###############################################################
#  Generated by:      Cadence Innovus 20.13-s083_1
#  OS:                Linux x86_64(Host ID caddyxtra)
#  Generated on:      Fri Jun 18 21:39:54 2021
#  Design:            user_project_wrapper
#  Command:           write_lef_abstract -specifyTopLayer 6 -PGPinLayers {5 6} -noCutObs -stripePin results/user_project_wrapper.lef
###############################################################

VERSION 5.8 ;

BUSBITCHARS "[]" ;
DIVIDERCHAR "/" ;

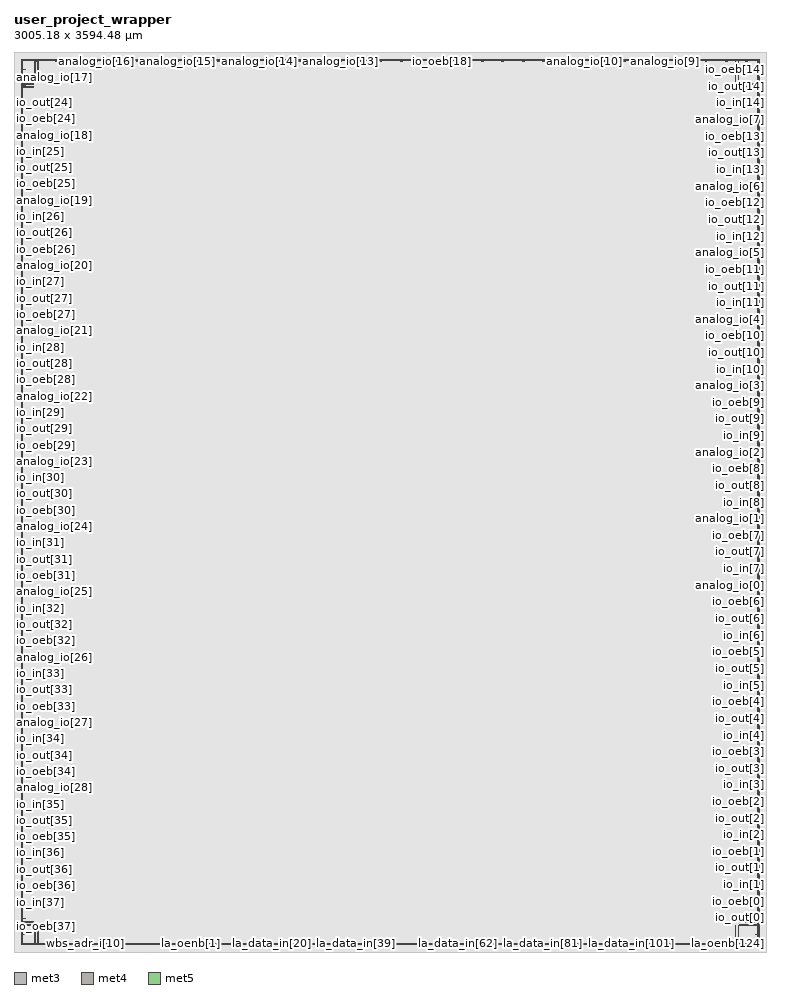
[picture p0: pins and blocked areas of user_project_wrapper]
MACRO user_project_wrapper
  CLASS BLOCK ;
  SIZE 3005.180000 BY 3594.480000 ;
  FOREIGN user_project_wrapper 0.000000 0.000000 ;
  ORIGIN 0 0 ;
  SYMMETRY X Y R90 ;
  PIN wb_clk_i
    DIRECTION INPUT ;
    USE SIGNAL ;
    ANTENNAPARTIALMETALAREA 0.2754 LAYER met3  ;
    ANTENNAPARTIALMETALSIDEAREA 1.464 LAYER met3  ;
    ANTENNAMODEL OXIDE1 ;
    ANTENNAGATEAREA 0.576 LAYER met3  ;
    ANTENNAMAXAREACAR 2.39566 LAYER met3  ;
    ANTENNAMAXSIDEAREACAR 9.93403 LAYER met3  ;
    ANTENNAMAXCUTCAR 0.158681 LAYER via3  ;
    PORT
      LAYER met3 ;
        RECT 45.490000 32.600000 52.690000 33.800000 ;
    END
  END wb_clk_i
  PIN wb_rst_i
    DIRECTION INPUT ;
    USE SIGNAL ;
    ANTENNAPARTIALMETALAREA 8.4594 LAYER met3  ;
    ANTENNAPARTIALMETALSIDEAREA 45.112 LAYER met3  ;
    ANTENNAMODEL OXIDE1 ;
    ANTENNAGATEAREA 1.33 LAYER met3  ;
    ANTENNAMAXAREACAR 19.705 LAYER met3  ;
    ANTENNAMAXSIDEAREACAR 99.8519 LAYER met3  ;
    ANTENNAMAXCUTCAR 0.0687218 LAYER via3  ;
    PORT
      LAYER met3 ;
        RECT 51.010000 32.600000 58.210000 33.800000 ;
    END
  END wb_rst_i
  PIN wbs_stb_i
    DIRECTION INPUT ;
    USE SIGNAL ;
    ANTENNAPARTIALMETALAREA 7.6608 LAYER met3  ;
    ANTENNAPARTIALMETALSIDEAREA 41.328 LAYER met3  ;
    PORT
      LAYER met3 ;
        RECT 68.950000 32.600000 76.150000 33.800000 ;
    END
  END wbs_stb_i
  PIN wbs_cyc_i
    DIRECTION INPUT ;
    USE SIGNAL ;
    ANTENNAPARTIALMETALAREA 8.2614 LAYER met3  ;
    ANTENNAPARTIALMETALSIDEAREA 44.056 LAYER met3  ;
    PORT
      LAYER met3 ;
        RECT 62.970000 32.600000 70.170000 33.800000 ;
    END
  END wbs_cyc_i
  PIN wbs_we_i
    DIRECTION INPUT ;
    USE SIGNAL ;
    ANTENNAPARTIALMETALAREA 7.4328 LAYER met3  ;
    ANTENNAPARTIALMETALSIDEAREA 40.112 LAYER met3  ;
    PORT
      LAYER met3 ;
        RECT 74.930000 32.600000 82.130000 33.800000 ;
    END
  END wbs_we_i
  PIN wbs_sel_i[3]
    DIRECTION INPUT ;
    USE SIGNAL ;
    ANTENNAPARTIALMETALAREA 7.4334 LAYER met3  ;
    ANTENNAPARTIALMETALSIDEAREA 39.64 LAYER met3  ;
    PORT
      LAYER met3 ;
        RECT 169.230000 32.600000 176.430000 33.800000 ;
    END
  END wbs_sel_i[3]
  PIN wbs_sel_i[2]
    DIRECTION INPUT ;
    USE SIGNAL ;
    ANTENNAPARTIALMETALAREA 7.2054 LAYER met3  ;
    ANTENNAPARTIALMETALSIDEAREA 38.424 LAYER met3  ;
    PORT
      LAYER met3 ;
        RECT 145.770000 32.600000 152.970000 33.800000 ;
    END
  END wbs_sel_i[2]
  PIN wbs_sel_i[1]
    DIRECTION INPUT ;
    USE SIGNAL ;
    ANTENNAPARTIALMETALAREA 7.9074 LAYER met3  ;
    ANTENNAPARTIALMETALSIDEAREA 42.168 LAYER met3  ;
    PORT
      LAYER met3 ;
        RECT 122.310000 32.600000 129.510000 33.800000 ;
    END
  END wbs_sel_i[1]
  PIN wbs_sel_i[0]
    DIRECTION INPUT ;
    USE SIGNAL ;
    PORT
      LAYER met3 ;
        RECT 98.390000 32.600000 105.590000 33.800000 ;
    END
  END wbs_sel_i[0]
  PIN wbs_dat_i[31]
    DIRECTION INPUT ;
    USE SIGNAL ;
    ANTENNAPARTIALMETALAREA 2.8494 LAYER met3  ;
    ANTENNAPARTIALMETALSIDEAREA 15.192 LAYER met3  ;
    PORT
      LAYER met3 ;
        RECT 660.050000 32.600000 667.250000 33.800000 ;
    END
  END wbs_dat_i[31]
  PIN wbs_dat_i[30]
    DIRECTION INPUT ;
    USE SIGNAL ;
    ANTENNAPARTIALMETALAREA 3.0654 LAYER met3  ;
    ANTENNAPARTIALMETALSIDEAREA 16.344 LAYER met3  ;
    PORT
      LAYER met3 ;
        RECT 642.110000 32.600000 649.310000 33.800000 ;
    END
  END wbs_dat_i[30]
  PIN wbs_dat_i[29]
    DIRECTION INPUT ;
    USE SIGNAL ;
    ANTENNAPARTIALMETALAREA 3.5694 LAYER met3  ;
    ANTENNAPARTIALMETALSIDEAREA 19.032 LAYER met3  ;
    PORT
      LAYER met3 ;
        RECT 624.630000 32.600000 631.830000 33.800000 ;
    END
  END wbs_dat_i[29]
  PIN wbs_dat_i[28]
    DIRECTION INPUT ;
    USE SIGNAL ;
    ANTENNAPARTIALMETALAREA 3.7674 LAYER met3  ;
    ANTENNAPARTIALMETALSIDEAREA 20.088 LAYER met3  ;
    PORT
      LAYER met3 ;
        RECT 606.690000 32.600000 613.890000 33.800000 ;
    END
  END wbs_dat_i[28]
  PIN wbs_dat_i[27]
    DIRECTION INPUT ;
    USE SIGNAL ;
    ANTENNAPARTIALMETALAREA 3.9054 LAYER met3  ;
    ANTENNAPARTIALMETALSIDEAREA 20.824 LAYER met3  ;
    PORT
      LAYER met3 ;
        RECT 589.210000 32.600000 596.410000 33.800000 ;
    END
  END wbs_dat_i[27]
  PIN wbs_dat_i[26]
    DIRECTION INPUT ;
    USE SIGNAL ;
    ANTENNAPARTIALMETALAREA 3.9834 LAYER met3  ;
    ANTENNAPARTIALMETALSIDEAREA 21.24 LAYER met3  ;
    PORT
      LAYER met3 ;
        RECT 571.270000 32.600000 578.470000 33.800000 ;
    END
  END wbs_dat_i[26]
  PIN wbs_dat_i[25]
    DIRECTION INPUT ;
    USE SIGNAL ;
    ANTENNAPARTIALMETALAREA 3.5874 LAYER met3  ;
    ANTENNAPARTIALMETALSIDEAREA 19.128 LAYER met3  ;
    PORT
      LAYER met3 ;
        RECT 553.790000 32.600000 560.990000 33.800000 ;
    END
  END wbs_dat_i[25]
  PIN wbs_dat_i[24]
    DIRECTION INPUT ;
    USE SIGNAL ;
    ANTENNAPARTIALMETALAREA 4.3194 LAYER met3  ;
    ANTENNAPARTIALMETALSIDEAREA 23.032 LAYER met3  ;
    PORT
      LAYER met3 ;
        RECT 535.850000 32.600000 543.050000 33.800000 ;
    END
  END wbs_dat_i[24]
  PIN wbs_dat_i[23]
    DIRECTION INPUT ;
    USE SIGNAL ;
    ANTENNAPARTIALMETALAREA 4.1364 LAYER met3  ;
    ANTENNAPARTIALMETALSIDEAREA 22.056 LAYER met3  ;
    PORT
      LAYER met3 ;
        RECT 518.370000 32.600000 525.570000 33.800000 ;
    END
  END wbs_dat_i[23]
  PIN wbs_dat_i[22]
    DIRECTION INPUT ;
    USE SIGNAL ;
    PORT
      LAYER met3 ;
        RECT 500.430000 32.600000 507.630000 33.800000 ;
    END
  END wbs_dat_i[22]
  PIN wbs_dat_i[21]
    DIRECTION INPUT ;
    USE SIGNAL ;
    ANTENNAPARTIALMETALAREA 4.8114 LAYER met3  ;
    ANTENNAPARTIALMETALSIDEAREA 25.656 LAYER met3  ;
    PORT
      LAYER met3 ;
        RECT 482.490000 32.600000 489.690000 33.800000 ;
    END
  END wbs_dat_i[21]
  PIN wbs_dat_i[20]
    DIRECTION INPUT ;
    USE SIGNAL ;
    ANTENNAPARTIALMETALAREA 4.6884 LAYER met3  ;
    ANTENNAPARTIALMETALSIDEAREA 25 LAYER met3  ;
    PORT
      LAYER met3 ;
        RECT 465.010000 32.600000 472.210000 33.800000 ;
    END
  END wbs_dat_i[20]
  PIN wbs_dat_i[19]
    DIRECTION INPUT ;
    USE SIGNAL ;
    ANTENNAPARTIALMETALAREA 4.7214 LAYER met3  ;
    ANTENNAPARTIALMETALSIDEAREA 25.176 LAYER met3  ;
    PORT
      LAYER met3 ;
        RECT 447.070000 32.600000 454.270000 33.800000 ;
    END
  END wbs_dat_i[19]
  PIN wbs_dat_i[18]
    DIRECTION INPUT ;
    USE SIGNAL ;
    ANTENNAPARTIALMETALAREA 4.6884 LAYER met3  ;
    ANTENNAPARTIALMETALSIDEAREA 25 LAYER met3  ;
    PORT
      LAYER met3 ;
        RECT 429.590000 32.600000 436.790000 33.800000 ;
    END
  END wbs_dat_i[18]
  PIN wbs_dat_i[17]
    DIRECTION INPUT ;
    USE SIGNAL ;
    ANTENNAPARTIALMETALAREA 5.4234 LAYER met3  ;
    ANTENNAPARTIALMETALSIDEAREA 28.92 LAYER met3  ;
    PORT
      LAYER met3 ;
        RECT 411.650000 32.600000 418.850000 33.800000 ;
    END
  END wbs_dat_i[17]
  PIN wbs_dat_i[16]
    DIRECTION INPUT ;
    USE SIGNAL ;
    ANTENNAPARTIALMETALAREA 5.4234 LAYER met3  ;
    ANTENNAPARTIALMETALSIDEAREA 28.92 LAYER met3  ;
    PORT
      LAYER met3 ;
        RECT 394.170000 32.600000 401.370000 33.800000 ;
    END
  END wbs_dat_i[16]
  PIN wbs_dat_i[15]
    DIRECTION INPUT ;
    USE SIGNAL ;
    PORT
      LAYER met3 ;
        RECT 376.230000 32.600000 383.430000 33.800000 ;
    END
  END wbs_dat_i[15]
  PIN wbs_dat_i[14]
    DIRECTION INPUT ;
    USE SIGNAL ;
    ANTENNAPARTIALMETALAREA 5.4114 LAYER met3  ;
    ANTENNAPARTIALMETALSIDEAREA 28.856 LAYER met3  ;
    PORT
      LAYER met3 ;
        RECT 358.750000 32.600000 365.950000 33.800000 ;
    END
  END wbs_dat_i[14]
  PIN wbs_dat_i[13]
    DIRECTION INPUT ;
    USE SIGNAL ;
    ANTENNAPARTIALMETALAREA 5.9154 LAYER met3  ;
    ANTENNAPARTIALMETALSIDEAREA 31.544 LAYER met3  ;
    PORT
      LAYER met3 ;
        RECT 340.810000 32.600000 348.010000 33.800000 ;
    END
  END wbs_dat_i[13]
  PIN wbs_dat_i[12]
    DIRECTION INPUT ;
    USE SIGNAL ;
    ANTENNAPARTIALMETALAREA 5.9118 LAYER met3  ;
    ANTENNAPARTIALMETALSIDEAREA 32 LAYER met3  ;
    PORT
      LAYER met3 ;
        RECT 322.870000 32.600000 330.070000 33.800000 ;
    END
  END wbs_dat_i[12]
  PIN wbs_dat_i[11]
    DIRECTION INPUT ;
    USE SIGNAL ;
    PORT
      LAYER met3 ;
        RECT 305.390000 32.600000 312.590000 33.800000 ;
    END
  END wbs_dat_i[11]
  PIN wbs_dat_i[10]
    DIRECTION INPUT ;
    USE SIGNAL ;
    ANTENNAPARTIALMETALAREA 6.1014 LAYER met3  ;
    ANTENNAPARTIALMETALSIDEAREA 32.536 LAYER met3  ;
    PORT
      LAYER met3 ;
        RECT 287.450000 32.600000 294.650000 33.800000 ;
    END
  END wbs_dat_i[10]
  PIN wbs_dat_i[9]
    DIRECTION INPUT ;
    USE SIGNAL ;
    ANTENNAPARTIALMETALAREA 6.5274 LAYER met3  ;
    ANTENNAPARTIALMETALSIDEAREA 34.808 LAYER met3  ;
    PORT
      LAYER met3 ;
        RECT 269.970000 32.600000 277.170000 33.800000 ;
    END
  END wbs_dat_i[9]
  PIN wbs_dat_i[8]
    DIRECTION INPUT ;
    USE SIGNAL ;
    PORT
      LAYER met3 ;
        RECT 252.030000 32.600000 259.230000 33.800000 ;
    END
  END wbs_dat_i[8]
  PIN wbs_dat_i[7]
    DIRECTION INPUT ;
    USE SIGNAL ;
    ANTENNAPARTIALMETALAREA 6.6462 LAYER met3  ;
    ANTENNAPARTIALMETALSIDEAREA 35.912 LAYER met3  ;
    PORT
      LAYER met3 ;
        RECT 234.550000 32.600000 241.750000 33.800000 ;
    END
  END wbs_dat_i[7]
  PIN wbs_dat_i[6]
    DIRECTION INPUT ;
    USE SIGNAL ;
    PORT
      LAYER met3 ;
        RECT 216.610000 32.600000 223.810000 33.800000 ;
    END
  END wbs_dat_i[6]
  PIN wbs_dat_i[5]
    DIRECTION INPUT ;
    USE SIGNAL ;
    ANTENNAPARTIALMETALAREA 6.6498 LAYER met3  ;
    ANTENNAPARTIALMETALSIDEAREA 35.936 LAYER met3  ;
    PORT
      LAYER met3 ;
        RECT 199.130000 32.600000 206.330000 33.800000 ;
    END
  END wbs_dat_i[5]
  PIN wbs_dat_i[4]
    DIRECTION INPUT ;
    USE SIGNAL ;
    ANTENNAPARTIALMETALAREA 6.5304 LAYER met3  ;
    ANTENNAPARTIALMETALSIDEAREA 34.824 LAYER met3  ;
    PORT
      LAYER met3 ;
        RECT 181.190000 32.600000 188.390000 33.800000 ;
    END
  END wbs_dat_i[4]
  PIN wbs_dat_i[3]
    DIRECTION INPUT ;
    USE SIGNAL ;
    ANTENNAPARTIALMETALAREA 6.6498 LAYER met3  ;
    ANTENNAPARTIALMETALSIDEAREA 35.936 LAYER met3  ;
    PORT
      LAYER met3 ;
        RECT 157.730000 32.600000 164.930000 33.800000 ;
    END
  END wbs_dat_i[3]
  PIN wbs_dat_i[2]
    DIRECTION INPUT ;
    USE SIGNAL ;
    PORT
      LAYER met3 ;
        RECT 133.810000 32.600000 141.010000 33.800000 ;
    END
  END wbs_dat_i[2]
  PIN wbs_dat_i[1]
    DIRECTION INPUT ;
    USE SIGNAL ;
    ANTENNAPARTIALMETALAREA 7.2948 LAYER met3  ;
    ANTENNAPARTIALMETALSIDEAREA 39.376 LAYER met3  ;
    PORT
      LAYER met3 ;
        RECT 110.350000 32.600000 117.550000 33.800000 ;
    END
  END wbs_dat_i[1]
  PIN wbs_dat_i[0]
    DIRECTION INPUT ;
    USE SIGNAL ;
    ANTENNAPARTIALMETALAREA 7.3584 LAYER met3  ;
    ANTENNAPARTIALMETALSIDEAREA 39.24 LAYER met3  ;
    PORT
      LAYER met3 ;
        RECT 86.430000 32.600000 93.630000 33.800000 ;
    END
  END wbs_dat_i[0]
  PIN wbs_adr_i[31]
    DIRECTION INPUT ;
    USE SIGNAL ;
    ANTENNAPARTIALMETALAREA 2.9274 LAYER met3  ;
    ANTENNAPARTIALMETALSIDEAREA 15.608 LAYER met3  ;
    PORT
      LAYER met3 ;
        RECT 654.070000 32.600000 661.270000 33.800000 ;
    END
  END wbs_adr_i[31]
  PIN wbs_adr_i[30]
    DIRECTION INPUT ;
    USE SIGNAL ;
    ANTENNAPARTIALMETALAREA 3.1254 LAYER met3  ;
    ANTENNAPARTIALMETALSIDEAREA 16.664 LAYER met3  ;
    PORT
      LAYER met3 ;
        RECT 636.590000 32.600000 643.790000 33.800000 ;
    END
  END wbs_adr_i[30]
  PIN wbs_adr_i[29]
    DIRECTION INPUT ;
    USE SIGNAL ;
    ANTENNAPARTIALMETALAREA 3.6294 LAYER met3  ;
    ANTENNAPARTIALMETALSIDEAREA 19.352 LAYER met3  ;
    PORT
      LAYER met3 ;
        RECT 618.650000 32.600000 625.850000 33.800000 ;
    END
  END wbs_adr_i[29]
  PIN wbs_adr_i[28]
    DIRECTION INPUT ;
    USE SIGNAL ;
    ANTENNAPARTIALMETALAREA 3.8454 LAYER met3  ;
    ANTENNAPARTIALMETALSIDEAREA 20.504 LAYER met3  ;
    PORT
      LAYER met3 ;
        RECT 600.710000 32.600000 607.910000 33.800000 ;
    END
  END wbs_adr_i[28]
  PIN wbs_adr_i[27]
    DIRECTION INPUT ;
    USE SIGNAL ;
    ANTENNAPARTIALMETALAREA 3.8454 LAYER met3  ;
    ANTENNAPARTIALMETALSIDEAREA 20.504 LAYER met3  ;
    PORT
      LAYER met3 ;
        RECT 583.230000 32.600000 590.430000 33.800000 ;
    END
  END wbs_adr_i[27]
  PIN wbs_adr_i[26]
    DIRECTION INPUT ;
    USE SIGNAL ;
    ANTENNAPARTIALMETALAREA 4.1814 LAYER met3  ;
    ANTENNAPARTIALMETALSIDEAREA 22.296 LAYER met3  ;
    PORT
      LAYER met3 ;
        RECT 565.290000 32.600000 572.490000 33.800000 ;
    END
  END wbs_adr_i[26]
  PIN wbs_adr_i[25]
    DIRECTION INPUT ;
    USE SIGNAL ;
    ANTENNAPARTIALMETALAREA 3.6774 LAYER met3  ;
    ANTENNAPARTIALMETALSIDEAREA 19.608 LAYER met3  ;
    PORT
      LAYER met3 ;
        RECT 547.810000 32.600000 555.010000 33.800000 ;
    END
  END wbs_adr_i[25]
  PIN wbs_adr_i[24]
    DIRECTION INPUT ;
    USE SIGNAL ;
    ANTENNAPARTIALMETALAREA 3.7068 LAYER met3  ;
    ANTENNAPARTIALMETALSIDEAREA 20.24 LAYER met3  ;
    PORT
      LAYER met3 ;
        RECT 529.870000 32.600000 537.070000 33.800000 ;
    END
  END wbs_adr_i[24]
  PIN wbs_adr_i[23]
    DIRECTION INPUT ;
    USE SIGNAL ;
    ANTENNAPARTIALMETALAREA 4.3974 LAYER met3  ;
    ANTENNAPARTIALMETALSIDEAREA 23.448 LAYER met3  ;
    PORT
      LAYER met3 ;
        RECT 512.390000 32.600000 519.590000 33.800000 ;
    END
  END wbs_adr_i[23]
  PIN wbs_adr_i[22]
    DIRECTION INPUT ;
    USE SIGNAL ;
    ANTENNAPARTIALMETALAREA 4.7334 LAYER met3  ;
    ANTENNAPARTIALMETALSIDEAREA 25.24 LAYER met3  ;
    PORT
      LAYER met3 ;
        RECT 494.450000 32.600000 501.650000 33.800000 ;
    END
  END wbs_adr_i[22]
  PIN wbs_adr_i[21]
    DIRECTION INPUT ;
    USE SIGNAL ;
    ANTENNAPARTIALMETALAREA 4.4124 LAYER met3  ;
    ANTENNAPARTIALMETALSIDEAREA 23.528 LAYER met3  ;
    PORT
      LAYER met3 ;
        RECT 476.970000 32.600000 484.170000 33.800000 ;
    END
  END wbs_adr_i[21]
  PIN wbs_adr_i[20]
    DIRECTION INPUT ;
    USE SIGNAL ;
    ANTENNAPARTIALMETALAREA 4.9494 LAYER met3  ;
    ANTENNAPARTIALMETALSIDEAREA 26.392 LAYER met3  ;
    PORT
      LAYER met3 ;
        RECT 459.030000 32.600000 466.230000 33.800000 ;
    END
  END wbs_adr_i[20]
  PIN wbs_adr_i[19]
    DIRECTION INPUT ;
    USE SIGNAL ;
    PORT
      LAYER met3 ;
        RECT 441.090000 32.600000 448.290000 33.800000 ;
    END
  END wbs_adr_i[19]
  PIN wbs_adr_i[18]
    DIRECTION INPUT ;
    USE SIGNAL ;
    ANTENNAPARTIALMETALAREA 5.2254 LAYER met3  ;
    ANTENNAPARTIALMETALSIDEAREA 27.864 LAYER met3  ;
    PORT
      LAYER met3 ;
        RECT 423.610000 32.600000 430.810000 33.800000 ;
    END
  END wbs_adr_i[18]
  PIN wbs_adr_i[17]
    DIRECTION INPUT ;
    USE SIGNAL ;
    ANTENNAPARTIALMETALAREA 4.9008 LAYER met3  ;
    ANTENNAPARTIALMETALSIDEAREA 26.608 LAYER met3  ;
    PORT
      LAYER met3 ;
        RECT 405.670000 32.600000 412.870000 33.800000 ;
    END
  END wbs_adr_i[17]
  PIN wbs_adr_i[16]
    DIRECTION INPUT ;
    USE SIGNAL ;
    ANTENNAPARTIALMETALAREA 5.5014 LAYER met3  ;
    ANTENNAPARTIALMETALSIDEAREA 29.336 LAYER met3  ;
    PORT
      LAYER met3 ;
        RECT 388.190000 32.600000 395.390000 33.800000 ;
    END
  END wbs_adr_i[16]
  PIN wbs_adr_i[15]
    DIRECTION INPUT ;
    USE SIGNAL ;
    ANTENNAPARTIALMETALAREA 5.6994 LAYER met3  ;
    ANTENNAPARTIALMETALSIDEAREA 30.392 LAYER met3  ;
    PORT
      LAYER met3 ;
        RECT 370.250000 32.600000 377.450000 33.800000 ;
    END
  END wbs_adr_i[15]
  PIN wbs_adr_i[14]
    DIRECTION INPUT ;
    USE SIGNAL ;
    ANTENNAPARTIALMETALAREA 5.8374 LAYER met3  ;
    ANTENNAPARTIALMETALSIDEAREA 31.128 LAYER met3  ;
    PORT
      LAYER met3 ;
        RECT 352.770000 32.600000 359.970000 33.800000 ;
    END
  END wbs_adr_i[14]
  PIN wbs_adr_i[13]
    DIRECTION INPUT ;
    USE SIGNAL ;
    ANTENNAPARTIALMETALAREA 5.7924 LAYER met3  ;
    ANTENNAPARTIALMETALSIDEAREA 30.888 LAYER met3  ;
    PORT
      LAYER met3 ;
        RECT 334.830000 32.600000 342.030000 33.800000 ;
    END
  END wbs_adr_i[13]
  PIN wbs_adr_i[12]
    DIRECTION INPUT ;
    USE SIGNAL ;
    ANTENNAPARTIALMETALAREA 5.65343 LAYER met3  ;
    ANTENNAPARTIALMETALSIDEAREA 30.144 LAYER met3  ;
    PORT
      LAYER met3 ;
        RECT 317.350000 32.600000 324.550000 33.800000 ;
    END
  END wbs_adr_i[12]
  PIN wbs_adr_i[11]
    DIRECTION INPUT ;
    USE SIGNAL ;
    ANTENNAPARTIALMETALAREA 6.3894 LAYER met3  ;
    ANTENNAPARTIALMETALSIDEAREA 34.072 LAYER met3  ;
    PORT
      LAYER met3 ;
        RECT 299.410000 32.600000 306.610000 33.800000 ;
    END
  END wbs_adr_i[11]
  PIN wbs_adr_i[10]
    DIRECTION INPUT ;
    USE SIGNAL ;
    ANTENNAPARTIALMETALAREA 6.4638 LAYER met3  ;
    ANTENNAPARTIALMETALSIDEAREA 34.944 LAYER met3  ;
    PORT
      LAYER met3 ;
        RECT 281.930000 32.600000 289.130000 33.800000 ;
    END
  END wbs_adr_i[10]
  PIN wbs_adr_i[9]
    DIRECTION INPUT ;
    USE SIGNAL ;
    ANTENNAPARTIALMETALAREA 6.6054 LAYER met3  ;
    ANTENNAPARTIALMETALSIDEAREA 35.224 LAYER met3  ;
    PORT
      LAYER met3 ;
        RECT 263.990000 32.600000 271.190000 33.800000 ;
    END
  END wbs_adr_i[9]
  PIN wbs_adr_i[8]
    DIRECTION INPUT ;
    USE SIGNAL ;
    ANTENNAPARTIALMETALAREA 6.8034 LAYER met3  ;
    ANTENNAPARTIALMETALSIDEAREA 36.28 LAYER met3  ;
    PORT
      LAYER met3 ;
        RECT 246.050000 32.600000 253.250000 33.800000 ;
    END
  END wbs_adr_i[8]
  PIN wbs_adr_i[7]
    DIRECTION INPUT ;
    USE SIGNAL ;
    PORT
      LAYER met3 ;
        RECT 228.570000 32.600000 235.770000 33.800000 ;
    END
  END wbs_adr_i[7]
  PIN wbs_adr_i[6]
    DIRECTION INPUT ;
    USE SIGNAL ;
    ANTENNAPARTIALMETALAREA 7.0794 LAYER met3  ;
    ANTENNAPARTIALMETALSIDEAREA 37.752 LAYER met3  ;
    PORT
      LAYER met3 ;
        RECT 210.630000 32.600000 217.830000 33.800000 ;
    END
  END wbs_adr_i[6]
  PIN wbs_adr_i[5]
    DIRECTION INPUT ;
    USE SIGNAL ;
    ANTENNAPARTIALMETALAREA 6.3708 LAYER met3  ;
    ANTENNAPARTIALMETALSIDEAREA 34.448 LAYER met3  ;
    PORT
      LAYER met3 ;
        RECT 193.150000 32.600000 200.350000 33.800000 ;
    END
  END wbs_adr_i[5]
  PIN wbs_adr_i[4]
    DIRECTION INPUT ;
    USE SIGNAL ;
    ANTENNAPARTIALMETALAREA 7.1244 LAYER met3  ;
    ANTENNAPARTIALMETALSIDEAREA 37.992 LAYER met3  ;
    PORT
      LAYER met3 ;
        RECT 175.210000 32.600000 182.410000 33.800000 ;
    END
  END wbs_adr_i[4]
  PIN wbs_adr_i[3]
    DIRECTION INPUT ;
    USE SIGNAL ;
    ANTENNAPARTIALMETALAREA 6.8328 LAYER met3  ;
    ANTENNAPARTIALMETALSIDEAREA 36.912 LAYER met3  ;
    PORT
      LAYER met3 ;
        RECT 151.750000 32.600000 158.950000 33.800000 ;
    END
  END wbs_adr_i[3]
  PIN wbs_adr_i[2]
    DIRECTION INPUT ;
    USE SIGNAL ;
    PORT
      LAYER met3 ;
        RECT 127.830000 32.600000 135.030000 33.800000 ;
    END
  END wbs_adr_i[2]
  PIN wbs_adr_i[1]
    DIRECTION INPUT ;
    USE SIGNAL ;
    ANTENNAPARTIALMETALAREA 7.4814 LAYER met3  ;
    ANTENNAPARTIALMETALSIDEAREA 39.896 LAYER met3  ;
    PORT
      LAYER met3 ;
        RECT 104.370000 32.600000 111.570000 33.800000 ;
    END
  END wbs_adr_i[1]
  PIN wbs_adr_i[0]
    DIRECTION INPUT ;
    USE SIGNAL ;
    ANTENNAPARTIALMETALAREA 8.0904 LAYER met3  ;
    ANTENNAPARTIALMETALSIDEAREA 43.144 LAYER met3  ;
    PORT
      LAYER met3 ;
        RECT 80.910000 32.600000 88.110000 33.800000 ;
    END
  END wbs_adr_i[0]
  PIN wbs_ack_o
    DIRECTION OUTPUT ;
    USE SIGNAL ;
    PORT
      LAYER met3 ;
        RECT 56.990000 32.600000 64.190000 33.800000 ;
    END
  END wbs_ack_o
  PIN wbs_dat_o[31]
    DIRECTION OUTPUT ;
    USE SIGNAL ;
    PORT
      LAYER met3 ;
        RECT 666.030000 32.600000 673.230000 33.800000 ;
    END
  END wbs_dat_o[31]
  PIN wbs_dat_o[30]
    DIRECTION OUTPUT ;
    USE SIGNAL ;
    PORT
      LAYER met3 ;
        RECT 648.090000 32.600000 655.290000 33.800000 ;
    END
  END wbs_dat_o[30]
  PIN wbs_dat_o[29]
    DIRECTION OUTPUT ;
    USE SIGNAL ;
    PORT
      LAYER met3 ;
        RECT 630.610000 32.600000 637.810000 33.800000 ;
    END
  END wbs_dat_o[29]
  PIN wbs_dat_o[28]
    DIRECTION OUTPUT ;
    USE SIGNAL ;
    PORT
      LAYER met3 ;
        RECT 612.670000 32.600000 619.870000 33.800000 ;
    END
  END wbs_dat_o[28]
  PIN wbs_dat_o[27]
    DIRECTION OUTPUT ;
    USE SIGNAL ;
    PORT
      LAYER met3 ;
        RECT 595.190000 32.600000 602.390000 33.800000 ;
    END
  END wbs_dat_o[27]
  PIN wbs_dat_o[26]
    DIRECTION OUTPUT ;
    USE SIGNAL ;
    PORT
      LAYER met3 ;
        RECT 577.250000 32.600000 584.450000 33.800000 ;
    END
  END wbs_dat_o[26]
  PIN wbs_dat_o[25]
    DIRECTION OUTPUT ;
    USE SIGNAL ;
    PORT
      LAYER met3 ;
        RECT 559.310000 32.600000 566.510000 33.800000 ;
    END
  END wbs_dat_o[25]
  PIN wbs_dat_o[24]
    DIRECTION OUTPUT ;
    USE SIGNAL ;
    PORT
      LAYER met3 ;
        RECT 541.830000 32.600000 549.030000 33.800000 ;
    END
  END wbs_dat_o[24]
  PIN wbs_dat_o[23]
    DIRECTION OUTPUT ;
    USE SIGNAL ;
    PORT
      LAYER met3 ;
        RECT 523.890000 32.600000 531.090000 33.800000 ;
    END
  END wbs_dat_o[23]
  PIN wbs_dat_o[22]
    DIRECTION OUTPUT ;
    USE SIGNAL ;
    PORT
      LAYER met3 ;
        RECT 506.410000 32.600000 513.610000 33.800000 ;
    END
  END wbs_dat_o[22]
  PIN wbs_dat_o[21]
    DIRECTION OUTPUT ;
    USE SIGNAL ;
    PORT
      LAYER met3 ;
        RECT 488.470000 32.600000 495.670000 33.800000 ;
    END
  END wbs_dat_o[21]
  PIN wbs_dat_o[20]
    DIRECTION OUTPUT ;
    USE SIGNAL ;
    PORT
      LAYER met3 ;
        RECT 470.990000 32.600000 478.190000 33.800000 ;
    END
  END wbs_dat_o[20]
  PIN wbs_dat_o[19]
    DIRECTION OUTPUT ;
    USE SIGNAL ;
    PORT
      LAYER met3 ;
        RECT 453.050000 32.600000 460.250000 33.800000 ;
    END
  END wbs_dat_o[19]
  PIN wbs_dat_o[18]
    DIRECTION OUTPUT ;
    USE SIGNAL ;
    PORT
      LAYER met3 ;
        RECT 435.570000 32.600000 442.770000 33.800000 ;
    END
  END wbs_dat_o[18]
  PIN wbs_dat_o[17]
    DIRECTION OUTPUT ;
    USE SIGNAL ;
    PORT
      LAYER met3 ;
        RECT 417.630000 32.600000 424.830000 33.800000 ;
    END
  END wbs_dat_o[17]
  PIN wbs_dat_o[16]
    DIRECTION OUTPUT ;
    USE SIGNAL ;
    PORT
      LAYER met3 ;
        RECT 400.150000 32.600000 407.350000 33.800000 ;
    END
  END wbs_dat_o[16]
  PIN wbs_dat_o[15]
    DIRECTION OUTPUT ;
    USE SIGNAL ;
    PORT
      LAYER met3 ;
        RECT 382.210000 32.600000 389.410000 33.800000 ;
    END
  END wbs_dat_o[15]
  PIN wbs_dat_o[14]
    DIRECTION OUTPUT ;
    USE SIGNAL ;
    PORT
      LAYER met3 ;
        RECT 364.270000 32.600000 371.470000 33.800000 ;
    END
  END wbs_dat_o[14]
  PIN wbs_dat_o[13]
    DIRECTION OUTPUT ;
    USE SIGNAL ;
    PORT
      LAYER met3 ;
        RECT 346.790000 32.600000 353.990000 33.800000 ;
    END
  END wbs_dat_o[13]
  PIN wbs_dat_o[12]
    DIRECTION OUTPUT ;
    USE SIGNAL ;
    PORT
      LAYER met3 ;
        RECT 328.850000 32.600000 336.050000 33.800000 ;
    END
  END wbs_dat_o[12]
  PIN wbs_dat_o[11]
    DIRECTION OUTPUT ;
    USE SIGNAL ;
    PORT
      LAYER met3 ;
        RECT 311.370000 32.600000 318.570000 33.800000 ;
    END
  END wbs_dat_o[11]
  PIN wbs_dat_o[10]
    DIRECTION OUTPUT ;
    USE SIGNAL ;
    PORT
      LAYER met3 ;
        RECT 293.430000 32.600000 300.630000 33.800000 ;
    END
  END wbs_dat_o[10]
  PIN wbs_dat_o[9]
    DIRECTION OUTPUT ;
    USE SIGNAL ;
    PORT
      LAYER met3 ;
        RECT 275.950000 32.600000 283.150000 33.800000 ;
    END
  END wbs_dat_o[9]
  PIN wbs_dat_o[8]
    DIRECTION OUTPUT ;
    USE SIGNAL ;
    PORT
      LAYER met3 ;
        RECT 258.010000 32.600000 265.210000 33.800000 ;
    END
  END wbs_dat_o[8]
  PIN wbs_dat_o[7]
    DIRECTION OUTPUT ;
    USE SIGNAL ;
    PORT
      LAYER met3 ;
        RECT 240.530000 32.600000 247.730000 33.800000 ;
    END
  END wbs_dat_o[7]
  PIN wbs_dat_o[6]
    DIRECTION OUTPUT ;
    USE SIGNAL ;
    PORT
      LAYER met3 ;
        RECT 222.590000 32.600000 229.790000 33.800000 ;
    END
  END wbs_dat_o[6]
  PIN wbs_dat_o[5]
    DIRECTION OUTPUT ;
    USE SIGNAL ;
    PORT
      LAYER met3 ;
        RECT 204.650000 32.600000 211.850000 33.800000 ;
    END
  END wbs_dat_o[5]
  PIN wbs_dat_o[4]
    DIRECTION OUTPUT ;
    USE SIGNAL ;
    PORT
      LAYER met3 ;
        RECT 187.170000 32.600000 194.370000 33.800000 ;
    END
  END wbs_dat_o[4]
  PIN wbs_dat_o[3]
    DIRECTION OUTPUT ;
    USE SIGNAL ;
    PORT
      LAYER met3 ;
        RECT 163.710000 32.600000 170.910000 33.800000 ;
    END
  END wbs_dat_o[3]
  PIN wbs_dat_o[2]
    DIRECTION OUTPUT ;
    USE SIGNAL ;
    PORT
      LAYER met3 ;
        RECT 139.790000 32.600000 146.990000 33.800000 ;
    END
  END wbs_dat_o[2]
  PIN wbs_dat_o[1]
    DIRECTION OUTPUT ;
    USE SIGNAL ;
    PORT
      LAYER met3 ;
        RECT 116.330000 32.600000 123.530000 33.800000 ;
    END
  END wbs_dat_o[1]
  PIN wbs_dat_o[0]
    DIRECTION OUTPUT ;
    USE SIGNAL ;
    PORT
      LAYER met3 ;
        RECT 92.410000 32.600000 99.610000 33.800000 ;
    END
  END wbs_dat_o[0]
  PIN la_data_in[127]
    DIRECTION INPUT ;
    USE SIGNAL ;
    ANTENNAPARTIALMETALAREA 16.6794 LAYER met3  ;
    ANTENNAPARTIALMETALSIDEAREA 88.952 LAYER met3  ;
    PORT
      LAYER met3 ;
        RECT 2924.170000 32.600000 2931.370000 33.800000 ;
    END
  END la_data_in[127]
  PIN la_data_in[126]
    DIRECTION INPUT ;
    USE SIGNAL ;
    ANTENNAPARTIALMETALAREA 0.2754 LAYER met3  ;
    ANTENNAPARTIALMETALSIDEAREA 1.464 LAYER met3  ;
    PORT
      LAYER met3 ;
        RECT 2906.230000 32.600000 2913.430000 33.800000 ;
    END
  END la_data_in[126]
  PIN la_data_in[125]
    DIRECTION INPUT ;
    USE SIGNAL ;
    ANTENNAPARTIALMETALAREA 0.4584 LAYER met3  ;
    ANTENNAPARTIALMETALSIDEAREA 2.44 LAYER met3  ;
    PORT
      LAYER met3 ;
        RECT 2888.290000 32.600000 2895.490000 33.800000 ;
    END
  END la_data_in[125]
  PIN la_data_in[124]
    DIRECTION INPUT ;
    USE SIGNAL ;
    ANTENNAPARTIALMETALAREA 0.2754 LAYER met3  ;
    ANTENNAPARTIALMETALSIDEAREA 1.464 LAYER met3  ;
    PORT
      LAYER met3 ;
        RECT 2870.810000 32.600000 2878.010000 33.800000 ;
    END
  END la_data_in[124]
  PIN la_data_in[123]
    DIRECTION INPUT ;
    USE SIGNAL ;
    ANTENNAPARTIALMETALAREA 15.8064 LAYER met3  ;
    ANTENNAPARTIALMETALSIDEAREA 84.296 LAYER met3  ;
    PORT
      LAYER met3 ;
        RECT 2852.870000 32.600000 2860.070000 33.800000 ;
    END
  END la_data_in[123]
  PIN la_data_in[122]
    DIRECTION INPUT ;
    USE SIGNAL ;
    ANTENNAPARTIALMETALAREA 16.1082 LAYER met3  ;
    ANTENNAPARTIALMETALSIDEAREA 86.376 LAYER met3  ;
    PORT
      LAYER met3 ;
        RECT 2835.390000 32.600000 2842.590000 33.800000 ;
    END
  END la_data_in[122]
  PIN la_data_in[121]
    DIRECTION INPUT ;
    USE SIGNAL ;
    ANTENNAPARTIALMETALAREA 0.2754 LAYER met3  ;
    ANTENNAPARTIALMETALSIDEAREA 1.464 LAYER met3  ;
    PORT
      LAYER met3 ;
        RECT 2817.450000 32.600000 2824.650000 33.800000 ;
    END
  END la_data_in[121]
  PIN la_data_in[120]
    DIRECTION INPUT ;
    USE SIGNAL ;
    ANTENNAPARTIALMETALAREA 14.6088 LAYER met3  ;
    ANTENNAPARTIALMETALSIDEAREA 78.384 LAYER met3  ;
    PORT
      LAYER met3 ;
        RECT 2799.970000 32.600000 2807.170000 33.800000 ;
    END
  END la_data_in[120]
  PIN la_data_in[119]
    DIRECTION INPUT ;
    USE SIGNAL ;
    ANTENNAPARTIALMETALAREA 14.3748 LAYER met3  ;
    ANTENNAPARTIALMETALSIDEAREA 77.136 LAYER met3  ;
    PORT
      LAYER met3 ;
        RECT 2782.030000 32.600000 2789.230000 33.800000 ;
    END
  END la_data_in[119]
  PIN la_data_in[118]
    DIRECTION INPUT ;
    USE SIGNAL ;
    ANTENNAPARTIALMETALAREA 15.7992 LAYER met3  ;
    ANTENNAPARTIALMETALSIDEAREA 84.728 LAYER met3  ;
    PORT
      LAYER met3 ;
        RECT 2764.550000 32.600000 2771.750000 33.800000 ;
    END
  END la_data_in[118]
  PIN la_data_in[117]
    DIRECTION INPUT ;
    USE SIGNAL ;
    ANTENNAPARTIALMETALAREA 0.2754 LAYER met3  ;
    ANTENNAPARTIALMETALSIDEAREA 1.464 LAYER met3  ;
    PORT
      LAYER met3 ;
        RECT 2746.610000 32.600000 2753.810000 33.800000 ;
    END
  END la_data_in[117]
  PIN la_data_in[116]
    DIRECTION INPUT ;
    USE SIGNAL ;
    ANTENNAPARTIALMETALAREA 0.2754 LAYER met3  ;
    ANTENNAPARTIALMETALSIDEAREA 1.464 LAYER met3  ;
    PORT
      LAYER met3 ;
        RECT 2728.670000 32.600000 2735.870000 33.800000 ;
    END
  END la_data_in[116]
  PIN la_data_in[115]
    DIRECTION INPUT ;
    USE SIGNAL ;
    ANTENNAPARTIALMETALAREA 14.9268 LAYER met3  ;
    ANTENNAPARTIALMETALSIDEAREA 80.08 LAYER met3  ;
    PORT
      LAYER met3 ;
        RECT 2711.190000 32.600000 2718.390000 33.800000 ;
    END
  END la_data_in[115]
  PIN la_data_in[114]
    DIRECTION INPUT ;
    USE SIGNAL ;
    PORT
      LAYER met3 ;
        RECT 2693.250000 32.600000 2700.450000 33.800000 ;
    END
  END la_data_in[114]
  PIN la_data_in[113]
    DIRECTION INPUT ;
    USE SIGNAL ;
    ANTENNAPARTIALMETALAREA 15.2922 LAYER met3  ;
    ANTENNAPARTIALMETALSIDEAREA 82.024 LAYER met3  ;
    PORT
      LAYER met3 ;
        RECT 2675.770000 32.600000 2682.970000 33.800000 ;
    END
  END la_data_in[113]
  PIN la_data_in[112]
    DIRECTION INPUT ;
    USE SIGNAL ;
    ANTENNAPARTIALMETALAREA 0.2754 LAYER met3  ;
    ANTENNAPARTIALMETALSIDEAREA 1.464 LAYER met3  ;
    PORT
      LAYER met3 ;
        RECT 2657.830000 32.600000 2665.030000 33.800000 ;
    END
  END la_data_in[112]
  PIN la_data_in[111]
    DIRECTION INPUT ;
    USE SIGNAL ;
    ANTENNAPARTIALMETALAREA 13.6848 LAYER met3  ;
    ANTENNAPARTIALMETALSIDEAREA 73.456 LAYER met3  ;
    PORT
      LAYER met3 ;
        RECT 2640.350000 32.600000 2647.550000 33.800000 ;
    END
  END la_data_in[111]
  PIN la_data_in[110]
    DIRECTION INPUT ;
    USE SIGNAL ;
    ANTENNAPARTIALMETALAREA 3.7674 LAYER met3  ;
    ANTENNAPARTIALMETALSIDEAREA 20.088 LAYER met3  ;
    PORT
      LAYER met3 ;
        RECT 2622.410000 32.600000 2629.610000 33.800000 ;
    END
  END la_data_in[110]
  PIN la_data_in[109]
    DIRECTION INPUT ;
    USE SIGNAL ;
    ANTENNAPARTIALMETALAREA 14.1438 LAYER met3  ;
    ANTENNAPARTIALMETALSIDEAREA 75.904 LAYER met3  ;
    PORT
      LAYER met3 ;
        RECT 2604.930000 32.600000 2612.130000 33.800000 ;
    END
  END la_data_in[109]
  PIN la_data_in[108]
    DIRECTION INPUT ;
    USE SIGNAL ;
    ANTENNAPARTIALMETALAREA 13.5984 LAYER met3  ;
    ANTENNAPARTIALMETALSIDEAREA 72.52 LAYER met3  ;
    PORT
      LAYER met3 ;
        RECT 2586.990000 32.600000 2594.190000 33.800000 ;
    END
  END la_data_in[108]
  PIN la_data_in[107]
    DIRECTION INPUT ;
    USE SIGNAL ;
    ANTENNAPARTIALMETALAREA 12.9077 LAYER met3  ;
    ANTENNAPARTIALMETALSIDEAREA 69.288 LAYER met3  ;
    PORT
      LAYER met3 ;
        RECT 2569.510000 32.600000 2576.710000 33.800000 ;
    END
  END la_data_in[107]
  PIN la_data_in[106]
    DIRECTION INPUT ;
    USE SIGNAL ;
    PORT
      LAYER met3 ;
        RECT 2551.570000 32.600000 2558.770000 33.800000 ;
    END
  END la_data_in[106]
  PIN la_data_in[105]
    DIRECTION INPUT ;
    USE SIGNAL ;
    ANTENNAPARTIALMETALAREA 0.2754 LAYER met3  ;
    ANTENNAPARTIALMETALSIDEAREA 1.464 LAYER met3  ;
    PORT
      LAYER met3 ;
        RECT 2533.630000 32.600000 2540.830000 33.800000 ;
    END
  END la_data_in[105]
  PIN la_data_in[104]
    DIRECTION INPUT ;
    USE SIGNAL ;
    ANTENNAPARTIALMETALAREA 13.0878 LAYER met3  ;
    ANTENNAPARTIALMETALSIDEAREA 70.272 LAYER met3  ;
    PORT
      LAYER met3 ;
        RECT 2516.150000 32.600000 2523.350000 33.800000 ;
    END
  END la_data_in[104]
  PIN la_data_in[103]
    DIRECTION INPUT ;
    USE SIGNAL ;
    ANTENNAPARTIALMETALAREA 0.2754 LAYER met3  ;
    ANTENNAPARTIALMETALSIDEAREA 1.464 LAYER met3  ;
    PORT
      LAYER met3 ;
        RECT 2498.210000 32.600000 2505.410000 33.800000 ;
    END
  END la_data_in[103]
  PIN la_data_in[102]
    DIRECTION INPUT ;
    USE SIGNAL ;
    ANTENNAPARTIALMETALAREA 12.2628 LAYER met3  ;
    ANTENNAPARTIALMETALSIDEAREA 65.872 LAYER met3  ;
    PORT
      LAYER met3 ;
        RECT 2480.730000 32.600000 2487.930000 33.800000 ;
    END
  END la_data_in[102]
  PIN la_data_in[101]
    DIRECTION INPUT ;
    USE SIGNAL ;
    ANTENNAPARTIALMETALAREA 12.3114 LAYER met3  ;
    ANTENNAPARTIALMETALSIDEAREA 65.656 LAYER met3  ;
    PORT
      LAYER met3 ;
        RECT 2462.790000 32.600000 2469.990000 33.800000 ;
    END
  END la_data_in[101]
  PIN la_data_in[100]
    DIRECTION INPUT ;
    USE SIGNAL ;
    PORT
      LAYER met3 ;
        RECT 2445.310000 32.600000 2452.510000 33.800000 ;
    END
  END la_data_in[100]
  PIN la_data_in[99]
    DIRECTION INPUT ;
    USE SIGNAL ;
    ANTENNAPARTIALMETALAREA 12.7182 LAYER met3  ;
    ANTENNAPARTIALMETALSIDEAREA 68.296 LAYER met3  ;
    PORT
      LAYER met3 ;
        RECT 2427.370000 32.600000 2434.570000 33.800000 ;
    END
  END la_data_in[99]
  PIN la_data_in[98]
    DIRECTION INPUT ;
    USE SIGNAL ;
    ANTENNAPARTIALMETALAREA 0.2754 LAYER met3  ;
    ANTENNAPARTIALMETALSIDEAREA 1.464 LAYER met3  ;
    PORT
      LAYER met3 ;
        RECT 2409.890000 32.600000 2417.090000 33.800000 ;
    END
  END la_data_in[98]
  PIN la_data_in[97]
    DIRECTION INPUT ;
    USE SIGNAL ;
    ANTENNAPARTIALMETALAREA 12.4422 LAYER met3  ;
    ANTENNAPARTIALMETALSIDEAREA 66.824 LAYER met3  ;
    PORT
      LAYER met3 ;
        RECT 2391.950000 32.600000 2399.150000 33.800000 ;
    END
  END la_data_in[97]
  PIN la_data_in[96]
    DIRECTION INPUT ;
    USE SIGNAL ;
    ANTENNAPARTIALMETALAREA 0.2754 LAYER met3  ;
    ANTENNAPARTIALMETALSIDEAREA 1.464 LAYER met3  ;
    PORT
      LAYER met3 ;
        RECT 2374.010000 32.600000 2381.210000 33.800000 ;
    END
  END la_data_in[96]
  PIN la_data_in[95]
    DIRECTION INPUT ;
    USE SIGNAL ;
    ANTENNAPARTIALMETALAREA 12.4134 LAYER met3  ;
    ANTENNAPARTIALMETALSIDEAREA 66.2 LAYER met3  ;
    PORT
      LAYER met3 ;
        RECT 2356.530000 32.600000 2363.730000 33.800000 ;
    END
  END la_data_in[95]
  PIN la_data_in[94]
    DIRECTION INPUT ;
    USE SIGNAL ;
    ANTENNAPARTIALMETALAREA 11.4318 LAYER met3  ;
    ANTENNAPARTIALMETALSIDEAREA 61.44 LAYER met3  ;
    PORT
      LAYER met3 ;
        RECT 2338.590000 32.600000 2345.790000 33.800000 ;
    END
  END la_data_in[94]
  PIN la_data_in[93]
    DIRECTION INPUT ;
    USE SIGNAL ;
    ANTENNAPARTIALMETALAREA 11.7114 LAYER met3  ;
    ANTENNAPARTIALMETALSIDEAREA 62.456 LAYER met3  ;
    PORT
      LAYER met3 ;
        RECT 2321.110000 32.600000 2328.310000 33.800000 ;
    END
  END la_data_in[93]
  PIN la_data_in[92]
    DIRECTION INPUT ;
    USE SIGNAL ;
    ANTENNAPARTIALMETALAREA 11.2482 LAYER met3  ;
    ANTENNAPARTIALMETALSIDEAREA 60.456 LAYER met3  ;
    PORT
      LAYER met3 ;
        RECT 2303.170000 32.600000 2310.370000 33.800000 ;
    END
  END la_data_in[92]
  PIN la_data_in[91]
    DIRECTION INPUT ;
    USE SIGNAL ;
    ANTENNAPARTIALMETALAREA 11.2482 LAYER met3  ;
    ANTENNAPARTIALMETALSIDEAREA 60.456 LAYER met3  ;
    PORT
      LAYER met3 ;
        RECT 2285.690000 32.600000 2292.890000 33.800000 ;
    END
  END la_data_in[91]
  PIN la_data_in[90]
    DIRECTION INPUT ;
    USE SIGNAL ;
    PORT
      LAYER met3 ;
        RECT 2267.750000 32.600000 2274.950000 33.800000 ;
    END
  END la_data_in[90]
  PIN la_data_in[89]
    DIRECTION INPUT ;
    USE SIGNAL ;
    ANTENNAPARTIALMETALAREA 10.6554 LAYER met3  ;
    ANTENNAPARTIALMETALSIDEAREA 56.824 LAYER met3  ;
    PORT
      LAYER met3 ;
        RECT 2250.270000 32.600000 2257.470000 33.800000 ;
    END
  END la_data_in[89]
  PIN la_data_in[88]
    DIRECTION INPUT ;
    USE SIGNAL ;
    PORT
      LAYER met3 ;
        RECT 2232.330000 32.600000 2239.530000 33.800000 ;
    END
  END la_data_in[88]
  PIN la_data_in[87]
    DIRECTION INPUT ;
    USE SIGNAL ;
    ANTENNAPARTIALMETALAREA 7.8504 LAYER met3  ;
    ANTENNAPARTIALMETALSIDEAREA 41.864 LAYER met3  ;
    PORT
      LAYER met3 ;
        RECT 2214.850000 32.600000 2222.050000 33.800000 ;
    END
  END la_data_in[87]
  PIN la_data_in[86]
    DIRECTION INPUT ;
    USE SIGNAL ;
    ANTENNAPARTIALMETALAREA 10.3464 LAYER met3  ;
    ANTENNAPARTIALMETALSIDEAREA 55.176 LAYER met3  ;
    PORT
      LAYER met3 ;
        RECT 2196.910000 32.600000 2204.110000 33.800000 ;
    END
  END la_data_in[86]
  PIN la_data_in[85]
    DIRECTION INPUT ;
    USE SIGNAL ;
    ANTENNAPARTIALMETALAREA 9.9168 LAYER met3  ;
    ANTENNAPARTIALMETALSIDEAREA 53.36 LAYER met3  ;
    PORT
      LAYER met3 ;
        RECT 2178.970000 32.600000 2186.170000 33.800000 ;
    END
  END la_data_in[85]
  PIN la_data_in[84]
    DIRECTION INPUT ;
    USE SIGNAL ;
    ANTENNAPARTIALMETALAREA 2.1924 LAYER met3  ;
    ANTENNAPARTIALMETALSIDEAREA 11.688 LAYER met3  ;
    PORT
      LAYER met3 ;
        RECT 2161.490000 32.600000 2168.690000 33.800000 ;
    END
  END la_data_in[84]
  PIN la_data_in[83]
    DIRECTION INPUT ;
    USE SIGNAL ;
    PORT
      LAYER met3 ;
        RECT 2143.550000 32.600000 2150.750000 33.800000 ;
    END
  END la_data_in[83]
  PIN la_data_in[82]
    DIRECTION INPUT ;
    USE SIGNAL ;
    ANTENNAPARTIALMETALAREA 5.6808 LAYER met3  ;
    ANTENNAPARTIALMETALSIDEAREA 30.768 LAYER met3  ;
    PORT
      LAYER met3 ;
        RECT 2126.070000 32.600000 2133.270000 33.800000 ;
    END
  END la_data_in[82]
  PIN la_data_in[81]
    DIRECTION INPUT ;
    USE SIGNAL ;
    PORT
      LAYER met3 ;
        RECT 2108.130000 32.600000 2115.330000 33.800000 ;
    END
  END la_data_in[81]
  PIN la_data_in[80]
    DIRECTION INPUT ;
    USE SIGNAL ;
    ANTENNAPARTIALMETALAREA 10.5714 LAYER met3  ;
    ANTENNAPARTIALMETALSIDEAREA 56.376 LAYER met3  ;
    PORT
      LAYER met3 ;
        RECT 2090.650000 32.600000 2097.850000 33.800000 ;
    END
  END la_data_in[80]
  PIN la_data_in[79]
    DIRECTION INPUT ;
    USE SIGNAL ;
    ANTENNAPARTIALMETALAREA 9.7464 LAYER met3  ;
    ANTENNAPARTIALMETALSIDEAREA 51.976 LAYER met3  ;
    PORT
      LAYER met3 ;
        RECT 2072.710000 32.600000 2079.910000 33.800000 ;
    END
  END la_data_in[79]
  PIN la_data_in[78]
    DIRECTION INPUT ;
    USE SIGNAL ;
    PORT
      LAYER met3 ;
        RECT 2055.230000 32.600000 2062.430000 33.800000 ;
    END
  END la_data_in[78]
  PIN la_data_in[77]
    DIRECTION INPUT ;
    USE SIGNAL ;
    ANTENNAPARTIALMETALAREA 8.0334 LAYER met3  ;
    ANTENNAPARTIALMETALSIDEAREA 42.84 LAYER met3  ;
    PORT
      LAYER met3 ;
        RECT 2037.290000 32.600000 2044.490000 33.800000 ;
    END
  END la_data_in[77]
  PIN la_data_in[76]
    DIRECTION INPUT ;
    USE SIGNAL ;
    PORT
      LAYER met3 ;
        RECT 2019.350000 32.600000 2026.550000 33.800000 ;
    END
  END la_data_in[76]
  PIN la_data_in[75]
    DIRECTION INPUT ;
    USE SIGNAL ;
    ANTENNAPARTIALMETALAREA 8.0334 LAYER met3  ;
    ANTENNAPARTIALMETALSIDEAREA 42.84 LAYER met3  ;
    PORT
      LAYER met3 ;
        RECT 2001.870000 32.600000 2009.070000 33.800000 ;
    END
  END la_data_in[75]
  PIN la_data_in[74]
    DIRECTION INPUT ;
    USE SIGNAL ;
    ANTENNAPARTIALMETALAREA 9.0114 LAYER met3  ;
    ANTENNAPARTIALMETALSIDEAREA 48.056 LAYER met3  ;
    PORT
      LAYER met3 ;
        RECT 1983.930000 32.600000 1991.130000 33.800000 ;
    END
  END la_data_in[74]
  PIN la_data_in[73]
    DIRECTION INPUT ;
    USE SIGNAL ;
    ANTENNAPARTIALMETALAREA 8.3094 LAYER met3  ;
    ANTENNAPARTIALMETALSIDEAREA 44.312 LAYER met3  ;
    PORT
      LAYER met3 ;
        RECT 1966.450000 32.600000 1973.650000 33.800000 ;
    END
  END la_data_in[73]
  PIN la_data_in[72]
    DIRECTION INPUT ;
    USE SIGNAL ;
    ANTENNAPARTIALMETALAREA 8.9634 LAYER met3  ;
    ANTENNAPARTIALMETALSIDEAREA 47.8 LAYER met3  ;
    PORT
      LAYER met3 ;
        RECT 1948.510000 32.600000 1955.710000 33.800000 ;
    END
  END la_data_in[72]
  PIN la_data_in[71]
    DIRECTION INPUT ;
    USE SIGNAL ;
    PORT
      LAYER met3 ;
        RECT 1931.030000 32.600000 1938.230000 33.800000 ;
    END
  END la_data_in[71]
  PIN la_data_in[70]
    DIRECTION INPUT ;
    USE SIGNAL ;
    ANTENNAPARTIALMETALAREA 8.1234 LAYER met3  ;
    ANTENNAPARTIALMETALSIDEAREA 43.32 LAYER met3  ;
    PORT
      LAYER met3 ;
        RECT 1913.090000 32.600000 1920.290000 33.800000 ;
    END
  END la_data_in[70]
  PIN la_data_in[69]
    DIRECTION INPUT ;
    USE SIGNAL ;
    ANTENNAPARTIALMETALAREA 7.4034 LAYER met3  ;
    ANTENNAPARTIALMETALSIDEAREA 39.48 LAYER met3  ;
    PORT
      LAYER met3 ;
        RECT 1895.610000 32.600000 1902.810000 33.800000 ;
    END
  END la_data_in[69]
  PIN la_data_in[68]
    DIRECTION INPUT ;
    USE SIGNAL ;
    ANTENNAPARTIALMETALAREA 8.1642 LAYER met3  ;
    ANTENNAPARTIALMETALSIDEAREA 44.008 LAYER met3  ;
    PORT
      LAYER met3 ;
        RECT 1877.670000 32.600000 1884.870000 33.800000 ;
    END
  END la_data_in[68]
  PIN la_data_in[67]
    DIRECTION INPUT ;
    USE SIGNAL ;
    ANTENNAPARTIALMETALAREA 7.7244 LAYER met3  ;
    ANTENNAPARTIALMETALSIDEAREA 41.192 LAYER met3  ;
    PORT
      LAYER met3 ;
        RECT 1860.190000 32.600000 1867.390000 33.800000 ;
    END
  END la_data_in[67]
  PIN la_data_in[66]
    DIRECTION INPUT ;
    USE SIGNAL ;
    ANTENNAPARTIALMETALAREA 7.4484 LAYER met3  ;
    ANTENNAPARTIALMETALSIDEAREA 39.72 LAYER met3  ;
    PORT
      LAYER met3 ;
        RECT 1842.250000 32.600000 1849.450000 33.800000 ;
    END
  END la_data_in[66]
  PIN la_data_in[65]
    DIRECTION INPUT ;
    USE SIGNAL ;
    ANTENNAPARTIALMETALAREA 7.9374 LAYER met3  ;
    ANTENNAPARTIALMETALSIDEAREA 42.328 LAYER met3  ;
    PORT
      LAYER met3 ;
        RECT 1824.310000 32.600000 1831.510000 33.800000 ;
    END
  END la_data_in[65]
  PIN la_data_in[64]
    DIRECTION INPUT ;
    USE SIGNAL ;
    ANTENNAPARTIALMETALAREA 7.4934 LAYER met3  ;
    ANTENNAPARTIALMETALSIDEAREA 39.96 LAYER met3  ;
    PORT
      LAYER met3 ;
        RECT 1806.830000 32.600000 1814.030000 33.800000 ;
    END
  END la_data_in[64]
  PIN la_data_in[63]
    DIRECTION INPUT ;
    USE SIGNAL ;
    ANTENNAPARTIALMETALAREA 6.8778 LAYER met3  ;
    ANTENNAPARTIALMETALSIDEAREA 37.152 LAYER met3  ;
    PORT
      LAYER met3 ;
        RECT 1788.890000 32.600000 1796.090000 33.800000 ;
    END
  END la_data_in[63]
  PIN la_data_in[62]
    DIRECTION INPUT ;
    USE SIGNAL ;
    PORT
      LAYER met3 ;
        RECT 1771.410000 32.600000 1778.610000 33.800000 ;
    END
  END la_data_in[62]
  PIN la_data_in[61]
    DIRECTION INPUT ;
    USE SIGNAL ;
    ANTENNAPARTIALMETALAREA 6.5154 LAYER met3  ;
    ANTENNAPARTIALMETALSIDEAREA 34.744 LAYER met3  ;
    PORT
      LAYER met3 ;
        RECT 1753.470000 32.600000 1760.670000 33.800000 ;
    END
  END la_data_in[61]
  PIN la_data_in[60]
    DIRECTION INPUT ;
    USE SIGNAL ;
    ANTENNAPARTIALMETALAREA 6.8034 LAYER met3  ;
    ANTENNAPARTIALMETALSIDEAREA 36.28 LAYER met3  ;
    PORT
      LAYER met3 ;
        RECT 1735.990000 32.600000 1743.190000 33.800000 ;
    END
  END la_data_in[60]
  PIN la_data_in[59]
    DIRECTION INPUT ;
    USE SIGNAL ;
    PORT
      LAYER met3 ;
        RECT 1718.050000 32.600000 1725.250000 33.800000 ;
    END
  END la_data_in[59]
  PIN la_data_in[58]
    DIRECTION INPUT ;
    USE SIGNAL ;
    ANTENNAPARTIALMETALAREA 6.5274 LAYER met3  ;
    ANTENNAPARTIALMETALSIDEAREA 34.808 LAYER met3  ;
    PORT
      LAYER met3 ;
        RECT 1700.570000 32.600000 1707.770000 33.800000 ;
    END
  END la_data_in[58]
  PIN la_data_in[57]
    DIRECTION INPUT ;
    USE SIGNAL ;
    PORT
      LAYER met3 ;
        RECT 1682.630000 32.600000 1689.830000 33.800000 ;
    END
  END la_data_in[57]
  PIN la_data_in[56]
    DIRECTION INPUT ;
    USE SIGNAL ;
    ANTENNAPARTIALMETALAREA 5.4402 LAYER met3  ;
    ANTENNAPARTIALMETALSIDEAREA 29.48 LAYER met3  ;
    PORT
      LAYER met3 ;
        RECT 1664.690000 32.600000 1671.890000 33.800000 ;
    END
  END la_data_in[56]
  PIN la_data_in[55]
    DIRECTION INPUT ;
    USE SIGNAL ;
    PORT
      LAYER met3 ;
        RECT 1647.210000 32.600000 1654.410000 33.800000 ;
    END
  END la_data_in[55]
  PIN la_data_in[54]
    DIRECTION INPUT ;
    USE SIGNAL ;
    ANTENNAPARTIALMETALAREA 5.6544 LAYER met3  ;
    ANTENNAPARTIALMETALSIDEAREA 30.152 LAYER met3  ;
    PORT
      LAYER met3 ;
        RECT 1629.270000 32.600000 1636.470000 33.800000 ;
    END
  END la_data_in[54]
  PIN la_data_in[53]
    DIRECTION INPUT ;
    USE SIGNAL ;
    ANTENNAPARTIALMETALAREA 5.7444 LAYER met3  ;
    ANTENNAPARTIALMETALSIDEAREA 30.632 LAYER met3  ;
    PORT
      LAYER met3 ;
        RECT 1611.790000 32.600000 1618.990000 33.800000 ;
    END
  END la_data_in[53]
  PIN la_data_in[52]
    DIRECTION INPUT ;
    USE SIGNAL ;
    ANTENNAPARTIALMETALAREA 5.5014 LAYER met3  ;
    ANTENNAPARTIALMETALSIDEAREA 29.336 LAYER met3  ;
    PORT
      LAYER met3 ;
        RECT 1593.850000 32.600000 1601.050000 33.800000 ;
    END
  END la_data_in[52]
  PIN la_data_in[51]
    DIRECTION INPUT ;
    USE SIGNAL ;
    PORT
      LAYER met3 ;
        RECT 1576.370000 32.600000 1583.570000 33.800000 ;
    END
  END la_data_in[51]
  PIN la_data_in[50]
    DIRECTION INPUT ;
    USE SIGNAL ;
    ANTENNAPARTIALMETALAREA 5.2854 LAYER met3  ;
    ANTENNAPARTIALMETALSIDEAREA 28.184 LAYER met3  ;
    PORT
      LAYER met3 ;
        RECT 1558.430000 32.600000 1565.630000 33.800000 ;
    END
  END la_data_in[50]
  PIN la_data_in[49]
    DIRECTION INPUT ;
    USE SIGNAL ;
    ANTENNAPARTIALMETALAREA 4.8594 LAYER met3  ;
    ANTENNAPARTIALMETALSIDEAREA 25.912 LAYER met3  ;
    PORT
      LAYER met3 ;
        RECT 1540.950000 32.600000 1548.150000 33.800000 ;
    END
  END la_data_in[49]
  PIN la_data_in[48]
    DIRECTION INPUT ;
    USE SIGNAL ;
    ANTENNAPARTIALMETALAREA 4.9494 LAYER met3  ;
    ANTENNAPARTIALMETALSIDEAREA 26.392 LAYER met3  ;
    PORT
      LAYER met3 ;
        RECT 1523.010000 32.600000 1530.210000 33.800000 ;
    END
  END la_data_in[48]
  PIN la_data_in[47]
    DIRECTION INPUT ;
    USE SIGNAL ;
    PORT
      LAYER met3 ;
        RECT 1505.530000 32.600000 1512.730000 33.800000 ;
    END
  END la_data_in[47]
  PIN la_data_in[46]
    DIRECTION INPUT ;
    USE SIGNAL ;
    ANTENNAPARTIALMETALAREA 4.6404 LAYER met3  ;
    ANTENNAPARTIALMETALSIDEAREA 24.744 LAYER met3  ;
    PORT
      LAYER met3 ;
        RECT 1487.590000 32.600000 1494.790000 33.800000 ;
    END
  END la_data_in[46]
  PIN la_data_in[45]
    DIRECTION INPUT ;
    USE SIGNAL ;
    ANTENNAPARTIALMETALAREA 4.5354 LAYER met3  ;
    ANTENNAPARTIALMETALSIDEAREA 24.184 LAYER met3  ;
    PORT
      LAYER met3 ;
        RECT 1469.650000 32.600000 1476.850000 33.800000 ;
    END
  END la_data_in[45]
  PIN la_data_in[44]
    DIRECTION INPUT ;
    USE SIGNAL ;
    ANTENNAPARTIALMETALAREA 4.4574 LAYER met3  ;
    ANTENNAPARTIALMETALSIDEAREA 23.768 LAYER met3  ;
    PORT
      LAYER met3 ;
        RECT 1452.170000 32.600000 1459.370000 33.800000 ;
    END
  END la_data_in[44]
  PIN la_data_in[43]
    DIRECTION INPUT ;
    USE SIGNAL ;
    ANTENNAPARTIALMETALAREA 3.6774 LAYER met3  ;
    ANTENNAPARTIALMETALSIDEAREA 19.608 LAYER met3  ;
    PORT
      LAYER met3 ;
        RECT 1434.230000 32.600000 1441.430000 33.800000 ;
    END
  END la_data_in[43]
  PIN la_data_in[42]
    DIRECTION INPUT ;
    USE SIGNAL ;
    ANTENNAPARTIALMETALAREA 4.1814 LAYER met3  ;
    ANTENNAPARTIALMETALSIDEAREA 22.296 LAYER met3  ;
    PORT
      LAYER met3 ;
        RECT 1416.750000 32.600000 1423.950000 33.800000 ;
    END
  END la_data_in[42]
  PIN la_data_in[41]
    DIRECTION INPUT ;
    USE SIGNAL ;
    ANTENNAPARTIALMETALAREA 3.8454 LAYER met3  ;
    ANTENNAPARTIALMETALSIDEAREA 20.504 LAYER met3  ;
    PORT
      LAYER met3 ;
        RECT 1398.810000 32.600000 1406.010000 33.800000 ;
    END
  END la_data_in[41]
  PIN la_data_in[40]
    DIRECTION INPUT ;
    USE SIGNAL ;
    ANTENNAPARTIALMETALAREA 3.8454 LAYER met3  ;
    ANTENNAPARTIALMETALSIDEAREA 20.504 LAYER met3  ;
    PORT
      LAYER met3 ;
        RECT 1381.330000 32.600000 1388.530000 33.800000 ;
    END
  END la_data_in[40]
  PIN la_data_in[39]
    DIRECTION INPUT ;
    USE SIGNAL ;
    ANTENNAPARTIALMETALAREA 3.5694 LAYER met3  ;
    ANTENNAPARTIALMETALSIDEAREA 19.032 LAYER met3  ;
    PORT
      LAYER met3 ;
        RECT 1363.390000 32.600000 1370.590000 33.800000 ;
    END
  END la_data_in[39]
  PIN la_data_in[38]
    DIRECTION INPUT ;
    USE SIGNAL ;
    ANTENNAPARTIALMETALAREA 3.1254 LAYER met3  ;
    ANTENNAPARTIALMETALSIDEAREA 16.664 LAYER met3  ;
    PORT
      LAYER met3 ;
        RECT 1345.910000 32.600000 1353.110000 33.800000 ;
    END
  END la_data_in[38]
  PIN la_data_in[37]
    DIRECTION INPUT ;
    USE SIGNAL ;
    ANTENNAPARTIALMETALAREA 2.9874 LAYER met3  ;
    ANTENNAPARTIALMETALSIDEAREA 15.928 LAYER met3  ;
    PORT
      LAYER met3 ;
        RECT 1327.970000 32.600000 1335.170000 33.800000 ;
    END
  END la_data_in[37]
  PIN la_data_in[36]
    DIRECTION INPUT ;
    USE SIGNAL ;
    ANTENNAPARTIALMETALAREA 2.9274 LAYER met3  ;
    ANTENNAPARTIALMETALSIDEAREA 15.608 LAYER met3  ;
    PORT
      LAYER met3 ;
        RECT 1310.030000 32.600000 1317.230000 33.800000 ;
    END
  END la_data_in[36]
  PIN la_data_in[35]
    DIRECTION INPUT ;
    USE SIGNAL ;
    ANTENNAPARTIALMETALAREA 2.5734 LAYER met3  ;
    ANTENNAPARTIALMETALSIDEAREA 13.72 LAYER met3  ;
    PORT
      LAYER met3 ;
        RECT 1292.550000 32.600000 1299.750000 33.800000 ;
    END
  END la_data_in[35]
  PIN la_data_in[34]
    DIRECTION INPUT ;
    USE SIGNAL ;
    ANTENNAPARTIALMETALAREA 2.1474 LAYER met3  ;
    ANTENNAPARTIALMETALSIDEAREA 11.448 LAYER met3  ;
    PORT
      LAYER met3 ;
        RECT 1274.610000 32.600000 1281.810000 33.800000 ;
    END
  END la_data_in[34]
  PIN la_data_in[33]
    DIRECTION INPUT ;
    USE SIGNAL ;
    ANTENNAPARTIALMETALAREA 2.1144 LAYER met3  ;
    ANTENNAPARTIALMETALSIDEAREA 11.272 LAYER met3  ;
    PORT
      LAYER met3 ;
        RECT 1257.130000 32.600000 1264.330000 33.800000 ;
    END
  END la_data_in[33]
  PIN la_data_in[32]
    DIRECTION INPUT ;
    USE SIGNAL ;
    ANTENNAPARTIALMETALAREA 1.9764 LAYER met3  ;
    ANTENNAPARTIALMETALSIDEAREA 10.536 LAYER met3  ;
    PORT
      LAYER met3 ;
        RECT 1239.190000 32.600000 1246.390000 33.800000 ;
    END
  END la_data_in[32]
  PIN la_data_in[31]
    DIRECTION INPUT ;
    USE SIGNAL ;
    ANTENNAPARTIALMETALAREA 1.7934 LAYER met3  ;
    ANTENNAPARTIALMETALSIDEAREA 9.56 LAYER met3  ;
    PORT
      LAYER met3 ;
        RECT 1221.710000 32.600000 1228.910000 33.800000 ;
    END
  END la_data_in[31]
  PIN la_data_in[30]
    DIRECTION INPUT ;
    USE SIGNAL ;
    ANTENNAPARTIALMETALAREA 1.5174 LAYER met3  ;
    ANTENNAPARTIALMETALSIDEAREA 8.088 LAYER met3  ;
    PORT
      LAYER met3 ;
        RECT 1203.770000 32.600000 1210.970000 33.800000 ;
    END
  END la_data_in[30]
  PIN la_data_in[29]
    DIRECTION INPUT ;
    USE SIGNAL ;
    ANTENNAPARTIALMETALAREA 1.5174 LAYER met3  ;
    ANTENNAPARTIALMETALSIDEAREA 8.088 LAYER met3  ;
    PORT
      LAYER met3 ;
        RECT 1186.290000 32.600000 1193.490000 33.800000 ;
    END
  END la_data_in[29]
  PIN la_data_in[28]
    DIRECTION INPUT ;
    USE SIGNAL ;
    ANTENNAPARTIALMETALAREA 1.2414 LAYER met3  ;
    ANTENNAPARTIALMETALSIDEAREA 6.616 LAYER met3  ;
    PORT
      LAYER met3 ;
        RECT 1168.350000 32.600000 1175.550000 33.800000 ;
    END
  END la_data_in[28]
  PIN la_data_in[27]
    DIRECTION INPUT ;
    USE SIGNAL ;
    ANTENNAPARTIALMETALAREA 1.2414 LAYER met3  ;
    ANTENNAPARTIALMETALSIDEAREA 6.616 LAYER met3  ;
    PORT
      LAYER met3 ;
        RECT 1150.410000 32.600000 1157.610000 33.800000 ;
    END
  END la_data_in[27]
  PIN la_data_in[26]
    DIRECTION INPUT ;
    USE SIGNAL ;
    ANTENNAPARTIALMETALAREA 0.9654 LAYER met3  ;
    ANTENNAPARTIALMETALSIDEAREA 5.144 LAYER met3  ;
    PORT
      LAYER met3 ;
        RECT 1132.930000 32.600000 1140.130000 33.800000 ;
    END
  END la_data_in[26]
  PIN la_data_in[25]
    DIRECTION INPUT ;
    USE SIGNAL ;
    ANTENNAPARTIALMETALAREA 0.9654 LAYER met3  ;
    ANTENNAPARTIALMETALSIDEAREA 5.144 LAYER met3  ;
    PORT
      LAYER met3 ;
        RECT 1114.990000 32.600000 1122.190000 33.800000 ;
    END
  END la_data_in[25]
  PIN la_data_in[24]
    DIRECTION INPUT ;
    USE SIGNAL ;
    ANTENNAPARTIALMETALAREA 0.6894 LAYER met3  ;
    ANTENNAPARTIALMETALSIDEAREA 3.672 LAYER met3  ;
    PORT
      LAYER met3 ;
        RECT 1097.510000 32.600000 1104.710000 33.800000 ;
    END
  END la_data_in[24]
  PIN la_data_in[23]
    DIRECTION INPUT ;
    USE SIGNAL ;
    PORT
      LAYER met3 ;
        RECT 1079.570000 32.600000 1086.770000 33.800000 ;
    END
  END la_data_in[23]
  PIN la_data_in[22]
    DIRECTION INPUT ;
    USE SIGNAL ;
    PORT
      LAYER met3 ;
        RECT 1062.090000 32.600000 1069.290000 33.800000 ;
    END
  END la_data_in[22]
  PIN la_data_in[21]
    DIRECTION INPUT ;
    USE SIGNAL ;
    ANTENNAPARTIALMETALAREA 0.4584 LAYER met3  ;
    ANTENNAPARTIALMETALSIDEAREA 2.44 LAYER met3  ;
    PORT
      LAYER met3 ;
        RECT 1044.150000 32.600000 1051.350000 33.800000 ;
    END
  END la_data_in[21]
  PIN la_data_in[20]
    DIRECTION INPUT ;
    USE SIGNAL ;
    ANTENNAPARTIALMETALAREA 0.4584 LAYER met3  ;
    ANTENNAPARTIALMETALSIDEAREA 2.44 LAYER met3  ;
    PORT
      LAYER met3 ;
        RECT 1026.670000 32.600000 1033.870000 33.800000 ;
    END
  END la_data_in[20]
  PIN la_data_in[19]
    DIRECTION INPUT ;
    USE SIGNAL ;
    ANTENNAPARTIALMETALAREA 0.2754 LAYER met3  ;
    ANTENNAPARTIALMETALSIDEAREA 1.464 LAYER met3  ;
    PORT
      LAYER met3 ;
        RECT 1008.730000 32.600000 1015.930000 33.800000 ;
    END
  END la_data_in[19]
  PIN la_data_in[18]
    DIRECTION INPUT ;
    USE SIGNAL ;
    PORT
      LAYER met3 ;
        RECT 991.250000 32.600000 998.450000 33.800000 ;
    END
  END la_data_in[18]
  PIN la_data_in[17]
    DIRECTION INPUT ;
    USE SIGNAL ;
    ANTENNAPARTIALMETALAREA 0.2754 LAYER met3  ;
    ANTENNAPARTIALMETALSIDEAREA 1.464 LAYER met3  ;
    PORT
      LAYER met3 ;
        RECT 973.310000 32.600000 980.510000 33.800000 ;
    END
  END la_data_in[17]
  PIN la_data_in[16]
    DIRECTION INPUT ;
    USE SIGNAL ;
    ANTENNAPARTIALMETALAREA 0.2754 LAYER met3  ;
    ANTENNAPARTIALMETALSIDEAREA 1.464 LAYER met3  ;
    PORT
      LAYER met3 ;
        RECT 955.370000 32.600000 962.570000 33.800000 ;
    END
  END la_data_in[16]
  PIN la_data_in[15]
    DIRECTION INPUT ;
    USE SIGNAL ;
    ANTENNAPARTIALMETALAREA 0.2754 LAYER met3  ;
    ANTENNAPARTIALMETALSIDEAREA 1.464 LAYER met3  ;
    PORT
      LAYER met3 ;
        RECT 937.890000 32.600000 945.090000 33.800000 ;
    END
  END la_data_in[15]
  PIN la_data_in[14]
    DIRECTION INPUT ;
    USE SIGNAL ;
    ANTENNAPARTIALMETALAREA 0.4584 LAYER met3  ;
    ANTENNAPARTIALMETALSIDEAREA 2.44 LAYER met3  ;
    PORT
      LAYER met3 ;
        RECT 919.950000 32.600000 927.150000 33.800000 ;
    END
  END la_data_in[14]
  PIN la_data_in[13]
    DIRECTION INPUT ;
    USE SIGNAL ;
    ANTENNAPARTIALMETALAREA 0.2754 LAYER met3  ;
    ANTENNAPARTIALMETALSIDEAREA 1.464 LAYER met3  ;
    PORT
      LAYER met3 ;
        RECT 902.470000 32.600000 909.670000 33.800000 ;
    END
  END la_data_in[13]
  PIN la_data_in[12]
    DIRECTION INPUT ;
    USE SIGNAL ;
    PORT
      LAYER met3 ;
        RECT 884.530000 32.600000 891.730000 33.800000 ;
    END
  END la_data_in[12]
  PIN la_data_in[11]
    DIRECTION INPUT ;
    USE SIGNAL ;
    ANTENNAPARTIALMETALAREA 0.2754 LAYER met3  ;
    ANTENNAPARTIALMETALSIDEAREA 1.464 LAYER met3  ;
    PORT
      LAYER met3 ;
        RECT 867.050000 32.600000 874.250000 33.800000 ;
    END
  END la_data_in[11]
  PIN la_data_in[10]
    DIRECTION INPUT ;
    USE SIGNAL ;
    ANTENNAPARTIALMETALAREA 0.6894 LAYER met3  ;
    ANTENNAPARTIALMETALSIDEAREA 3.672 LAYER met3  ;
    PORT
      LAYER met3 ;
        RECT 849.110000 32.600000 856.310000 33.800000 ;
    END
  END la_data_in[10]
  PIN la_data_in[9]
    DIRECTION INPUT ;
    USE SIGNAL ;
    ANTENNAPARTIALMETALAREA 0.2754 LAYER met3  ;
    ANTENNAPARTIALMETALSIDEAREA 1.464 LAYER met3  ;
    PORT
      LAYER met3 ;
        RECT 831.630000 32.600000 838.830000 33.800000 ;
    END
  END la_data_in[9]
  PIN la_data_in[8]
    DIRECTION INPUT ;
    USE SIGNAL ;
    ANTENNAPARTIALMETALAREA 1.2414 LAYER met3  ;
    ANTENNAPARTIALMETALSIDEAREA 6.616 LAYER met3  ;
    PORT
      LAYER met3 ;
        RECT 813.690000 32.600000 820.890000 33.800000 ;
    END
  END la_data_in[8]
  PIN la_data_in[7]
    DIRECTION INPUT ;
    USE SIGNAL ;
    ANTENNAPARTIALMETALAREA 0.4584 LAYER met3  ;
    ANTENNAPARTIALMETALSIDEAREA 2.44 LAYER met3  ;
    PORT
      LAYER met3 ;
        RECT 795.750000 32.600000 802.950000 33.800000 ;
    END
  END la_data_in[7]
  PIN la_data_in[6]
    DIRECTION INPUT ;
    USE SIGNAL ;
    ANTENNAPARTIALMETALAREA 1.5174 LAYER met3  ;
    ANTENNAPARTIALMETALSIDEAREA 8.088 LAYER met3  ;
    PORT
      LAYER met3 ;
        RECT 778.270000 32.600000 785.470000 33.800000 ;
    END
  END la_data_in[6]
  PIN la_data_in[5]
    DIRECTION INPUT ;
    USE SIGNAL ;
    PORT
      LAYER met3 ;
        RECT 760.330000 32.600000 767.530000 33.800000 ;
    END
  END la_data_in[5]
  PIN la_data_in[4]
    DIRECTION INPUT ;
    USE SIGNAL ;
    ANTENNAPARTIALMETALAREA 1.7934 LAYER met3  ;
    ANTENNAPARTIALMETALSIDEAREA 9.56 LAYER met3  ;
    PORT
      LAYER met3 ;
        RECT 742.850000 32.600000 750.050000 33.800000 ;
    END
  END la_data_in[4]
  PIN la_data_in[3]
    DIRECTION INPUT ;
    USE SIGNAL ;
    ANTENNAPARTIALMETALAREA 0.6894 LAYER met3  ;
    ANTENNAPARTIALMETALSIDEAREA 3.672 LAYER met3  ;
    PORT
      LAYER met3 ;
        RECT 724.910000 32.600000 732.110000 33.800000 ;
    END
  END la_data_in[3]
  PIN la_data_in[2]
    DIRECTION INPUT ;
    USE SIGNAL ;
    ANTENNAPARTIALMETALAREA 2.0094 LAYER met3  ;
    ANTENNAPARTIALMETALSIDEAREA 10.712 LAYER met3  ;
    PORT
      LAYER met3 ;
        RECT 707.430000 32.600000 714.630000 33.800000 ;
    END
  END la_data_in[2]
  PIN la_data_in[1]
    DIRECTION INPUT ;
    USE SIGNAL ;
    ANTENNAPARTIALMETALAREA 2.3454 LAYER met3  ;
    ANTENNAPARTIALMETALSIDEAREA 12.504 LAYER met3  ;
    PORT
      LAYER met3 ;
        RECT 689.490000 32.600000 696.690000 33.800000 ;
    END
  END la_data_in[1]
  PIN la_data_in[0]
    DIRECTION INPUT ;
    USE SIGNAL ;
    ANTENNAPARTIALMETALAREA 2.8494 LAYER met3  ;
    ANTENNAPARTIALMETALSIDEAREA 15.192 LAYER met3  ;
    PORT
      LAYER met3 ;
        RECT 672.010000 32.600000 679.210000 33.800000 ;
    END
  END la_data_in[0]
  PIN la_data_out[127]
    DIRECTION OUTPUT ;
    USE SIGNAL ;
    PORT
      LAYER met3 ;
        RECT 2929.690000 32.600000 2936.890000 33.800000 ;
    END
  END la_data_out[127]
  PIN la_data_out[126]
    DIRECTION OUTPUT ;
    USE SIGNAL ;
    PORT
      LAYER met3 ;
        RECT 2912.210000 32.600000 2919.410000 33.800000 ;
    END
  END la_data_out[126]
  PIN la_data_out[125]
    DIRECTION OUTPUT ;
    USE SIGNAL ;
    PORT
      LAYER met3 ;
        RECT 2894.270000 32.600000 2901.470000 33.800000 ;
    END
  END la_data_out[125]
  PIN la_data_out[124]
    DIRECTION OUTPUT ;
    USE SIGNAL ;
    PORT
      LAYER met3 ;
        RECT 2876.790000 32.600000 2883.990000 33.800000 ;
    END
  END la_data_out[124]
  PIN la_data_out[123]
    DIRECTION OUTPUT ;
    USE SIGNAL ;
    PORT
      LAYER met3 ;
        RECT 2858.850000 32.600000 2866.050000 33.800000 ;
    END
  END la_data_out[123]
  PIN la_data_out[122]
    DIRECTION OUTPUT ;
    USE SIGNAL ;
    PORT
      LAYER met3 ;
        RECT 2841.370000 32.600000 2848.570000 33.800000 ;
    END
  END la_data_out[122]
  PIN la_data_out[121]
    DIRECTION OUTPUT ;
    USE SIGNAL ;
    PORT
      LAYER met3 ;
        RECT 2823.430000 32.600000 2830.630000 33.800000 ;
    END
  END la_data_out[121]
  PIN la_data_out[120]
    DIRECTION OUTPUT ;
    USE SIGNAL ;
    PORT
      LAYER met3 ;
        RECT 2805.950000 32.600000 2813.150000 33.800000 ;
    END
  END la_data_out[120]
  PIN la_data_out[119]
    DIRECTION OUTPUT ;
    USE SIGNAL ;
    PORT
      LAYER met3 ;
        RECT 2788.010000 32.600000 2795.210000 33.800000 ;
    END
  END la_data_out[119]
  PIN la_data_out[118]
    DIRECTION OUTPUT ;
    USE SIGNAL ;
    PORT
      LAYER met3 ;
        RECT 2770.070000 32.600000 2777.270000 33.800000 ;
    END
  END la_data_out[118]
  PIN la_data_out[117]
    DIRECTION OUTPUT ;
    USE SIGNAL ;
    PORT
      LAYER met3 ;
        RECT 2752.590000 32.600000 2759.790000 33.800000 ;
    END
  END la_data_out[117]
  PIN la_data_out[116]
    DIRECTION OUTPUT ;
    USE SIGNAL ;
    PORT
      LAYER met3 ;
        RECT 2734.650000 32.600000 2741.850000 33.800000 ;
    END
  END la_data_out[116]
  PIN la_data_out[115]
    DIRECTION OUTPUT ;
    USE SIGNAL ;
    PORT
      LAYER met3 ;
        RECT 2717.170000 32.600000 2724.370000 33.800000 ;
    END
  END la_data_out[115]
  PIN la_data_out[114]
    DIRECTION OUTPUT ;
    USE SIGNAL ;
    PORT
      LAYER met3 ;
        RECT 2699.230000 32.600000 2706.430000 33.800000 ;
    END
  END la_data_out[114]
  PIN la_data_out[113]
    DIRECTION OUTPUT ;
    USE SIGNAL ;
    PORT
      LAYER met3 ;
        RECT 2681.750000 32.600000 2688.950000 33.800000 ;
    END
  END la_data_out[113]
  PIN la_data_out[112]
    DIRECTION OUTPUT ;
    USE SIGNAL ;
    PORT
      LAYER met3 ;
        RECT 2663.810000 32.600000 2671.010000 33.800000 ;
    END
  END la_data_out[112]
  PIN la_data_out[111]
    DIRECTION OUTPUT ;
    USE SIGNAL ;
    PORT
      LAYER met3 ;
        RECT 2646.330000 32.600000 2653.530000 33.800000 ;
    END
  END la_data_out[111]
  PIN la_data_out[110]
    DIRECTION OUTPUT ;
    USE SIGNAL ;
    PORT
      LAYER met3 ;
        RECT 2628.390000 32.600000 2635.590000 33.800000 ;
    END
  END la_data_out[110]
  PIN la_data_out[109]
    DIRECTION OUTPUT ;
    USE SIGNAL ;
    PORT
      LAYER met3 ;
        RECT 2610.450000 32.600000 2617.650000 33.800000 ;
    END
  END la_data_out[109]
  PIN la_data_out[108]
    DIRECTION OUTPUT ;
    USE SIGNAL ;
    PORT
      LAYER met3 ;
        RECT 2592.970000 32.600000 2600.170000 33.800000 ;
    END
  END la_data_out[108]
  PIN la_data_out[107]
    DIRECTION OUTPUT ;
    USE SIGNAL ;
    PORT
      LAYER met3 ;
        RECT 2575.030000 32.600000 2582.230000 33.800000 ;
    END
  END la_data_out[107]
  PIN la_data_out[106]
    DIRECTION OUTPUT ;
    USE SIGNAL ;
    PORT
      LAYER met3 ;
        RECT 2557.550000 32.600000 2564.750000 33.800000 ;
    END
  END la_data_out[106]
  PIN la_data_out[105]
    DIRECTION OUTPUT ;
    USE SIGNAL ;
    PORT
      LAYER met3 ;
        RECT 2539.610000 32.600000 2546.810000 33.800000 ;
    END
  END la_data_out[105]
  PIN la_data_out[104]
    DIRECTION OUTPUT ;
    USE SIGNAL ;
    PORT
      LAYER met3 ;
        RECT 2522.130000 32.600000 2529.330000 33.800000 ;
    END
  END la_data_out[104]
  PIN la_data_out[103]
    DIRECTION OUTPUT ;
    USE SIGNAL ;
    PORT
      LAYER met3 ;
        RECT 2504.190000 32.600000 2511.390000 33.800000 ;
    END
  END la_data_out[103]
  PIN la_data_out[102]
    DIRECTION OUTPUT ;
    USE SIGNAL ;
    PORT
      LAYER met3 ;
        RECT 2486.710000 32.600000 2493.910000 33.800000 ;
    END
  END la_data_out[102]
  PIN la_data_out[101]
    DIRECTION OUTPUT ;
    USE SIGNAL ;
    PORT
      LAYER met3 ;
        RECT 2468.770000 32.600000 2475.970000 33.800000 ;
    END
  END la_data_out[101]
  PIN la_data_out[100]
    DIRECTION OUTPUT ;
    USE SIGNAL ;
    PORT
      LAYER met3 ;
        RECT 2451.290000 32.600000 2458.490000 33.800000 ;
    END
  END la_data_out[100]
  PIN la_data_out[99]
    DIRECTION OUTPUT ;
    USE SIGNAL ;
    PORT
      LAYER met3 ;
        RECT 2433.350000 32.600000 2440.550000 33.800000 ;
    END
  END la_data_out[99]
  PIN la_data_out[98]
    DIRECTION OUTPUT ;
    USE SIGNAL ;
    PORT
      LAYER met3 ;
        RECT 2415.410000 32.600000 2422.610000 33.800000 ;
    END
  END la_data_out[98]
  PIN la_data_out[97]
    DIRECTION OUTPUT ;
    USE SIGNAL ;
    PORT
      LAYER met3 ;
        RECT 2397.930000 32.600000 2405.130000 33.800000 ;
    END
  END la_data_out[97]
  PIN la_data_out[96]
    DIRECTION OUTPUT ;
    USE SIGNAL ;
    PORT
      LAYER met3 ;
        RECT 2379.990000 32.600000 2387.190000 33.800000 ;
    END
  END la_data_out[96]
  PIN la_data_out[95]
    DIRECTION OUTPUT ;
    USE SIGNAL ;
    PORT
      LAYER met3 ;
        RECT 2362.510000 32.600000 2369.710000 33.800000 ;
    END
  END la_data_out[95]
  PIN la_data_out[94]
    DIRECTION OUTPUT ;
    USE SIGNAL ;
    PORT
      LAYER met3 ;
        RECT 2344.570000 32.600000 2351.770000 33.800000 ;
    END
  END la_data_out[94]
  PIN la_data_out[93]
    DIRECTION OUTPUT ;
    USE SIGNAL ;
    PORT
      LAYER met3 ;
        RECT 2327.090000 32.600000 2334.290000 33.800000 ;
    END
  END la_data_out[93]
  PIN la_data_out[92]
    DIRECTION OUTPUT ;
    USE SIGNAL ;
    PORT
      LAYER met3 ;
        RECT 2309.150000 32.600000 2316.350000 33.800000 ;
    END
  END la_data_out[92]
  PIN la_data_out[91]
    DIRECTION OUTPUT ;
    USE SIGNAL ;
    PORT
      LAYER met3 ;
        RECT 2291.670000 32.600000 2298.870000 33.800000 ;
    END
  END la_data_out[91]
  PIN la_data_out[90]
    DIRECTION OUTPUT ;
    USE SIGNAL ;
    PORT
      LAYER met3 ;
        RECT 2273.730000 32.600000 2280.930000 33.800000 ;
    END
  END la_data_out[90]
  PIN la_data_out[89]
    DIRECTION OUTPUT ;
    USE SIGNAL ;
    PORT
      LAYER met3 ;
        RECT 2255.790000 32.600000 2262.990000 33.800000 ;
    END
  END la_data_out[89]
  PIN la_data_out[88]
    DIRECTION OUTPUT ;
    USE SIGNAL ;
    PORT
      LAYER met3 ;
        RECT 2238.310000 32.600000 2245.510000 33.800000 ;
    END
  END la_data_out[88]
  PIN la_data_out[87]
    DIRECTION OUTPUT ;
    USE SIGNAL ;
    PORT
      LAYER met3 ;
        RECT 2220.370000 32.600000 2227.570000 33.800000 ;
    END
  END la_data_out[87]
  PIN la_data_out[86]
    DIRECTION OUTPUT ;
    USE SIGNAL ;
    PORT
      LAYER met3 ;
        RECT 2202.890000 32.600000 2210.090000 33.800000 ;
    END
  END la_data_out[86]
  PIN la_data_out[85]
    DIRECTION OUTPUT ;
    USE SIGNAL ;
    PORT
      LAYER met3 ;
        RECT 2184.950000 32.600000 2192.150000 33.800000 ;
    END
  END la_data_out[85]
  PIN la_data_out[84]
    DIRECTION OUTPUT ;
    USE SIGNAL ;
    PORT
      LAYER met3 ;
        RECT 2167.470000 32.600000 2174.670000 33.800000 ;
    END
  END la_data_out[84]
  PIN la_data_out[83]
    DIRECTION OUTPUT ;
    USE SIGNAL ;
    PORT
      LAYER met3 ;
        RECT 2149.530000 32.600000 2156.730000 33.800000 ;
    END
  END la_data_out[83]
  PIN la_data_out[82]
    DIRECTION OUTPUT ;
    USE SIGNAL ;
    PORT
      LAYER met3 ;
        RECT 2132.050000 32.600000 2139.250000 33.800000 ;
    END
  END la_data_out[82]
  PIN la_data_out[81]
    DIRECTION OUTPUT ;
    USE SIGNAL ;
    PORT
      LAYER met3 ;
        RECT 2114.110000 32.600000 2121.310000 33.800000 ;
    END
  END la_data_out[81]
  PIN la_data_out[80]
    DIRECTION OUTPUT ;
    USE SIGNAL ;
    PORT
      LAYER met3 ;
        RECT 2096.630000 32.600000 2103.830000 33.800000 ;
    END
  END la_data_out[80]
  PIN la_data_out[79]
    DIRECTION OUTPUT ;
    USE SIGNAL ;
    PORT
      LAYER met3 ;
        RECT 2078.690000 32.600000 2085.890000 33.800000 ;
    END
  END la_data_out[79]
  PIN la_data_out[78]
    DIRECTION OUTPUT ;
    USE SIGNAL ;
    PORT
      LAYER met3 ;
        RECT 2060.750000 32.600000 2067.950000 33.800000 ;
    END
  END la_data_out[78]
  PIN la_data_out[77]
    DIRECTION OUTPUT ;
    USE SIGNAL ;
    PORT
      LAYER met3 ;
        RECT 2043.270000 32.600000 2050.470000 33.800000 ;
    END
  END la_data_out[77]
  PIN la_data_out[76]
    DIRECTION OUTPUT ;
    USE SIGNAL ;
    PORT
      LAYER met3 ;
        RECT 2025.330000 32.600000 2032.530000 33.800000 ;
    END
  END la_data_out[76]
  PIN la_data_out[75]
    DIRECTION OUTPUT ;
    USE SIGNAL ;
    PORT
      LAYER met3 ;
        RECT 2007.850000 32.600000 2015.050000 33.800000 ;
    END
  END la_data_out[75]
  PIN la_data_out[74]
    DIRECTION OUTPUT ;
    USE SIGNAL ;
    PORT
      LAYER met3 ;
        RECT 1989.910000 32.600000 1997.110000 33.800000 ;
    END
  END la_data_out[74]
  PIN la_data_out[73]
    DIRECTION OUTPUT ;
    USE SIGNAL ;
    PORT
      LAYER met3 ;
        RECT 1972.430000 32.600000 1979.630000 33.800000 ;
    END
  END la_data_out[73]
  PIN la_data_out[72]
    DIRECTION OUTPUT ;
    USE SIGNAL ;
    PORT
      LAYER met3 ;
        RECT 1954.490000 32.600000 1961.690000 33.800000 ;
    END
  END la_data_out[72]
  PIN la_data_out[71]
    DIRECTION OUTPUT ;
    USE SIGNAL ;
    PORT
      LAYER met3 ;
        RECT 1937.010000 32.600000 1944.210000 33.800000 ;
    END
  END la_data_out[71]
  PIN la_data_out[70]
    DIRECTION OUTPUT ;
    USE SIGNAL ;
    PORT
      LAYER met3 ;
        RECT 1919.070000 32.600000 1926.270000 33.800000 ;
    END
  END la_data_out[70]
  PIN la_data_out[69]
    DIRECTION OUTPUT ;
    USE SIGNAL ;
    PORT
      LAYER met3 ;
        RECT 1901.130000 32.600000 1908.330000 33.800000 ;
    END
  END la_data_out[69]
  PIN la_data_out[68]
    DIRECTION OUTPUT ;
    USE SIGNAL ;
    PORT
      LAYER met3 ;
        RECT 1883.650000 32.600000 1890.850000 33.800000 ;
    END
  END la_data_out[68]
  PIN la_data_out[67]
    DIRECTION OUTPUT ;
    USE SIGNAL ;
    PORT
      LAYER met3 ;
        RECT 1865.710000 32.600000 1872.910000 33.800000 ;
    END
  END la_data_out[67]
  PIN la_data_out[66]
    DIRECTION OUTPUT ;
    USE SIGNAL ;
    PORT
      LAYER met3 ;
        RECT 1848.230000 32.600000 1855.430000 33.800000 ;
    END
  END la_data_out[66]
  PIN la_data_out[65]
    DIRECTION OUTPUT ;
    USE SIGNAL ;
    PORT
      LAYER met3 ;
        RECT 1830.290000 32.600000 1837.490000 33.800000 ;
    END
  END la_data_out[65]
  PIN la_data_out[64]
    DIRECTION OUTPUT ;
    USE SIGNAL ;
    PORT
      LAYER met3 ;
        RECT 1812.810000 32.600000 1820.010000 33.800000 ;
    END
  END la_data_out[64]
  PIN la_data_out[63]
    DIRECTION OUTPUT ;
    USE SIGNAL ;
    PORT
      LAYER met3 ;
        RECT 1794.870000 32.600000 1802.070000 33.800000 ;
    END
  END la_data_out[63]
  PIN la_data_out[62]
    DIRECTION OUTPUT ;
    USE SIGNAL ;
    PORT
      LAYER met3 ;
        RECT 1777.390000 32.600000 1784.590000 33.800000 ;
    END
  END la_data_out[62]
  PIN la_data_out[61]
    DIRECTION OUTPUT ;
    USE SIGNAL ;
    PORT
      LAYER met3 ;
        RECT 1759.450000 32.600000 1766.650000 33.800000 ;
    END
  END la_data_out[61]
  PIN la_data_out[60]
    DIRECTION OUTPUT ;
    USE SIGNAL ;
    PORT
      LAYER met3 ;
        RECT 1741.970000 32.600000 1749.170000 33.800000 ;
    END
  END la_data_out[60]
  PIN la_data_out[59]
    DIRECTION OUTPUT ;
    USE SIGNAL ;
    PORT
      LAYER met3 ;
        RECT 1724.030000 32.600000 1731.230000 33.800000 ;
    END
  END la_data_out[59]
  PIN la_data_out[58]
    DIRECTION OUTPUT ;
    USE SIGNAL ;
    PORT
      LAYER met3 ;
        RECT 1706.090000 32.600000 1713.290000 33.800000 ;
    END
  END la_data_out[58]
  PIN la_data_out[57]
    DIRECTION OUTPUT ;
    USE SIGNAL ;
    PORT
      LAYER met3 ;
        RECT 1688.610000 32.600000 1695.810000 33.800000 ;
    END
  END la_data_out[57]
  PIN la_data_out[56]
    DIRECTION OUTPUT ;
    USE SIGNAL ;
    PORT
      LAYER met3 ;
        RECT 1670.670000 32.600000 1677.870000 33.800000 ;
    END
  END la_data_out[56]
  PIN la_data_out[55]
    DIRECTION OUTPUT ;
    USE SIGNAL ;
    PORT
      LAYER met3 ;
        RECT 1653.190000 32.600000 1660.390000 33.800000 ;
    END
  END la_data_out[55]
  PIN la_data_out[54]
    DIRECTION OUTPUT ;
    USE SIGNAL ;
    PORT
      LAYER met3 ;
        RECT 1635.250000 32.600000 1642.450000 33.800000 ;
    END
  END la_data_out[54]
  PIN la_data_out[53]
    DIRECTION OUTPUT ;
    USE SIGNAL ;
    PORT
      LAYER met3 ;
        RECT 1617.770000 32.600000 1624.970000 33.800000 ;
    END
  END la_data_out[53]
  PIN la_data_out[52]
    DIRECTION OUTPUT ;
    USE SIGNAL ;
    PORT
      LAYER met3 ;
        RECT 1599.830000 32.600000 1607.030000 33.800000 ;
    END
  END la_data_out[52]
  PIN la_data_out[51]
    DIRECTION OUTPUT ;
    USE SIGNAL ;
    PORT
      LAYER met3 ;
        RECT 1582.350000 32.600000 1589.550000 33.800000 ;
    END
  END la_data_out[51]
  PIN la_data_out[50]
    DIRECTION OUTPUT ;
    USE SIGNAL ;
    PORT
      LAYER met3 ;
        RECT 1564.410000 32.600000 1571.610000 33.800000 ;
    END
  END la_data_out[50]
  PIN la_data_out[49]
    DIRECTION OUTPUT ;
    USE SIGNAL ;
    PORT
      LAYER met3 ;
        RECT 1546.470000 32.600000 1553.670000 33.800000 ;
    END
  END la_data_out[49]
  PIN la_data_out[48]
    DIRECTION OUTPUT ;
    USE SIGNAL ;
    PORT
      LAYER met3 ;
        RECT 1528.990000 32.600000 1536.190000 33.800000 ;
    END
  END la_data_out[48]
  PIN la_data_out[47]
    DIRECTION OUTPUT ;
    USE SIGNAL ;
    PORT
      LAYER met3 ;
        RECT 1511.050000 32.600000 1518.250000 33.800000 ;
    END
  END la_data_out[47]
  PIN la_data_out[46]
    DIRECTION OUTPUT ;
    USE SIGNAL ;
    PORT
      LAYER met3 ;
        RECT 1493.570000 32.600000 1500.770000 33.800000 ;
    END
  END la_data_out[46]
  PIN la_data_out[45]
    DIRECTION OUTPUT ;
    USE SIGNAL ;
    PORT
      LAYER met3 ;
        RECT 1475.630000 32.600000 1482.830000 33.800000 ;
    END
  END la_data_out[45]
  PIN la_data_out[44]
    DIRECTION OUTPUT ;
    USE SIGNAL ;
    PORT
      LAYER met3 ;
        RECT 1458.150000 32.600000 1465.350000 33.800000 ;
    END
  END la_data_out[44]
  PIN la_data_out[43]
    DIRECTION OUTPUT ;
    USE SIGNAL ;
    PORT
      LAYER met3 ;
        RECT 1440.210000 32.600000 1447.410000 33.800000 ;
    END
  END la_data_out[43]
  PIN la_data_out[42]
    DIRECTION OUTPUT ;
    USE SIGNAL ;
    PORT
      LAYER met3 ;
        RECT 1422.730000 32.600000 1429.930000 33.800000 ;
    END
  END la_data_out[42]
  PIN la_data_out[41]
    DIRECTION OUTPUT ;
    USE SIGNAL ;
    PORT
      LAYER met3 ;
        RECT 1404.790000 32.600000 1411.990000 33.800000 ;
    END
  END la_data_out[41]
  PIN la_data_out[40]
    DIRECTION OUTPUT ;
    USE SIGNAL ;
    PORT
      LAYER met3 ;
        RECT 1386.850000 32.600000 1394.050000 33.800000 ;
    END
  END la_data_out[40]
  PIN la_data_out[39]
    DIRECTION OUTPUT ;
    USE SIGNAL ;
    PORT
      LAYER met3 ;
        RECT 1369.370000 32.600000 1376.570000 33.800000 ;
    END
  END la_data_out[39]
  PIN la_data_out[38]
    DIRECTION OUTPUT ;
    USE SIGNAL ;
    PORT
      LAYER met3 ;
        RECT 1351.430000 32.600000 1358.630000 33.800000 ;
    END
  END la_data_out[38]
  PIN la_data_out[37]
    DIRECTION OUTPUT ;
    USE SIGNAL ;
    PORT
      LAYER met3 ;
        RECT 1333.950000 32.600000 1341.150000 33.800000 ;
    END
  END la_data_out[37]
  PIN la_data_out[36]
    DIRECTION OUTPUT ;
    USE SIGNAL ;
    PORT
      LAYER met3 ;
        RECT 1316.010000 32.600000 1323.210000 33.800000 ;
    END
  END la_data_out[36]
  PIN la_data_out[35]
    DIRECTION OUTPUT ;
    USE SIGNAL ;
    PORT
      LAYER met3 ;
        RECT 1298.530000 32.600000 1305.730000 33.800000 ;
    END
  END la_data_out[35]
  PIN la_data_out[34]
    DIRECTION OUTPUT ;
    USE SIGNAL ;
    PORT
      LAYER met3 ;
        RECT 1280.590000 32.600000 1287.790000 33.800000 ;
    END
  END la_data_out[34]
  PIN la_data_out[33]
    DIRECTION OUTPUT ;
    USE SIGNAL ;
    PORT
      LAYER met3 ;
        RECT 1263.110000 32.600000 1270.310000 33.800000 ;
    END
  END la_data_out[33]
  PIN la_data_out[32]
    DIRECTION OUTPUT ;
    USE SIGNAL ;
    PORT
      LAYER met3 ;
        RECT 1245.170000 32.600000 1252.370000 33.800000 ;
    END
  END la_data_out[32]
  PIN la_data_out[31]
    DIRECTION OUTPUT ;
    USE SIGNAL ;
    PORT
      LAYER met3 ;
        RECT 1227.690000 32.600000 1234.890000 33.800000 ;
    END
  END la_data_out[31]
  PIN la_data_out[30]
    DIRECTION OUTPUT ;
    USE SIGNAL ;
    PORT
      LAYER met3 ;
        RECT 1209.750000 32.600000 1216.950000 33.800000 ;
    END
  END la_data_out[30]
  PIN la_data_out[29]
    DIRECTION OUTPUT ;
    USE SIGNAL ;
    PORT
      LAYER met3 ;
        RECT 1191.810000 32.600000 1199.010000 33.800000 ;
    END
  END la_data_out[29]
  PIN la_data_out[28]
    DIRECTION OUTPUT ;
    USE SIGNAL ;
    PORT
      LAYER met3 ;
        RECT 1174.330000 32.600000 1181.530000 33.800000 ;
    END
  END la_data_out[28]
  PIN la_data_out[27]
    DIRECTION OUTPUT ;
    USE SIGNAL ;
    PORT
      LAYER met3 ;
        RECT 1156.390000 32.600000 1163.590000 33.800000 ;
    END
  END la_data_out[27]
  PIN la_data_out[26]
    DIRECTION OUTPUT ;
    USE SIGNAL ;
    PORT
      LAYER met3 ;
        RECT 1138.910000 32.600000 1146.110000 33.800000 ;
    END
  END la_data_out[26]
  PIN la_data_out[25]
    DIRECTION OUTPUT ;
    USE SIGNAL ;
    PORT
      LAYER met3 ;
        RECT 1120.970000 32.600000 1128.170000 33.800000 ;
    END
  END la_data_out[25]
  PIN la_data_out[24]
    DIRECTION OUTPUT ;
    USE SIGNAL ;
    PORT
      LAYER met3 ;
        RECT 1103.490000 32.600000 1110.690000 33.800000 ;
    END
  END la_data_out[24]
  PIN la_data_out[23]
    DIRECTION OUTPUT ;
    USE SIGNAL ;
    PORT
      LAYER met3 ;
        RECT 1085.550000 32.600000 1092.750000 33.800000 ;
    END
  END la_data_out[23]
  PIN la_data_out[22]
    DIRECTION OUTPUT ;
    USE SIGNAL ;
    PORT
      LAYER met3 ;
        RECT 1068.070000 32.600000 1075.270000 33.800000 ;
    END
  END la_data_out[22]
  PIN la_data_out[21]
    DIRECTION OUTPUT ;
    USE SIGNAL ;
    PORT
      LAYER met3 ;
        RECT 1050.130000 32.600000 1057.330000 33.800000 ;
    END
  END la_data_out[21]
  PIN la_data_out[20]
    DIRECTION OUTPUT ;
    USE SIGNAL ;
    PORT
      LAYER met3 ;
        RECT 1032.190000 32.600000 1039.390000 33.800000 ;
    END
  END la_data_out[20]
  PIN la_data_out[19]
    DIRECTION OUTPUT ;
    USE SIGNAL ;
    PORT
      LAYER met3 ;
        RECT 1014.710000 32.600000 1021.910000 33.800000 ;
    END
  END la_data_out[19]
  PIN la_data_out[18]
    DIRECTION OUTPUT ;
    USE SIGNAL ;
    PORT
      LAYER met3 ;
        RECT 996.770000 32.600000 1003.970000 33.800000 ;
    END
  END la_data_out[18]
  PIN la_data_out[17]
    DIRECTION OUTPUT ;
    USE SIGNAL ;
    PORT
      LAYER met3 ;
        RECT 979.290000 32.600000 986.490000 33.800000 ;
    END
  END la_data_out[17]
  PIN la_data_out[16]
    DIRECTION OUTPUT ;
    USE SIGNAL ;
    PORT
      LAYER met3 ;
        RECT 961.350000 32.600000 968.550000 33.800000 ;
    END
  END la_data_out[16]
  PIN la_data_out[15]
    DIRECTION OUTPUT ;
    USE SIGNAL ;
    PORT
      LAYER met3 ;
        RECT 943.870000 32.600000 951.070000 33.800000 ;
    END
  END la_data_out[15]
  PIN la_data_out[14]
    DIRECTION OUTPUT ;
    USE SIGNAL ;
    PORT
      LAYER met3 ;
        RECT 925.930000 32.600000 933.130000 33.800000 ;
    END
  END la_data_out[14]
  PIN la_data_out[13]
    DIRECTION OUTPUT ;
    USE SIGNAL ;
    PORT
      LAYER met3 ;
        RECT 908.450000 32.600000 915.650000 33.800000 ;
    END
  END la_data_out[13]
  PIN la_data_out[12]
    DIRECTION OUTPUT ;
    USE SIGNAL ;
    PORT
      LAYER met3 ;
        RECT 890.510000 32.600000 897.710000 33.800000 ;
    END
  END la_data_out[12]
  PIN la_data_out[11]
    DIRECTION OUTPUT ;
    USE SIGNAL ;
    PORT
      LAYER met3 ;
        RECT 873.030000 32.600000 880.230000 33.800000 ;
    END
  END la_data_out[11]
  PIN la_data_out[10]
    DIRECTION OUTPUT ;
    USE SIGNAL ;
    PORT
      LAYER met3 ;
        RECT 855.090000 32.600000 862.290000 33.800000 ;
    END
  END la_data_out[10]
  PIN la_data_out[9]
    DIRECTION OUTPUT ;
    USE SIGNAL ;
    PORT
      LAYER met3 ;
        RECT 837.150000 32.600000 844.350000 33.800000 ;
    END
  END la_data_out[9]
  PIN la_data_out[8]
    DIRECTION OUTPUT ;
    USE SIGNAL ;
    PORT
      LAYER met3 ;
        RECT 819.670000 32.600000 826.870000 33.800000 ;
    END
  END la_data_out[8]
  PIN la_data_out[7]
    DIRECTION OUTPUT ;
    USE SIGNAL ;
    PORT
      LAYER met3 ;
        RECT 801.730000 32.600000 808.930000 33.800000 ;
    END
  END la_data_out[7]
  PIN la_data_out[6]
    DIRECTION OUTPUT ;
    USE SIGNAL ;
    PORT
      LAYER met3 ;
        RECT 784.250000 32.600000 791.450000 33.800000 ;
    END
  END la_data_out[6]
  PIN la_data_out[5]
    DIRECTION OUTPUT ;
    USE SIGNAL ;
    PORT
      LAYER met3 ;
        RECT 766.310000 32.600000 773.510000 33.800000 ;
    END
  END la_data_out[5]
  PIN la_data_out[4]
    DIRECTION OUTPUT ;
    USE SIGNAL ;
    PORT
      LAYER met3 ;
        RECT 748.830000 32.600000 756.030000 33.800000 ;
    END
  END la_data_out[4]
  PIN la_data_out[3]
    DIRECTION OUTPUT ;
    USE SIGNAL ;
    PORT
      LAYER met3 ;
        RECT 730.890000 32.600000 738.090000 33.800000 ;
    END
  END la_data_out[3]
  PIN la_data_out[2]
    DIRECTION OUTPUT ;
    USE SIGNAL ;
    PORT
      LAYER met3 ;
        RECT 713.410000 32.600000 720.610000 33.800000 ;
    END
  END la_data_out[2]
  PIN la_data_out[1]
    DIRECTION OUTPUT ;
    USE SIGNAL ;
    PORT
      LAYER met3 ;
        RECT 695.470000 32.600000 702.670000 33.800000 ;
    END
  END la_data_out[1]
  PIN la_data_out[0]
    DIRECTION OUTPUT ;
    USE SIGNAL ;
    PORT
      LAYER met3 ;
        RECT 677.530000 32.600000 684.730000 33.800000 ;
    END
  END la_data_out[0]
  PIN la_oenb[127]
    DIRECTION INPUT ;
    USE SIGNAL ;
    ANTENNAPARTIALMETALAREA 16.3548 LAYER met3  ;
    ANTENNAPARTIALMETALSIDEAREA 87.696 LAYER met3  ;
    PORT
      LAYER met3 ;
        RECT 2935.670000 32.600000 2942.870000 33.800000 ;
    END
  END la_oenb[127]
  PIN la_oenb[126]
    DIRECTION INPUT ;
    USE SIGNAL ;
    ANTENNAPARTIALMETALAREA 16.7208 LAYER met3  ;
    ANTENNAPARTIALMETALSIDEAREA 89.648 LAYER met3  ;
    PORT
      LAYER met3 ;
        RECT 2918.190000 32.600000 2925.390000 33.800000 ;
    END
  END la_oenb[126]
  PIN la_oenb[125]
    DIRECTION INPUT ;
    USE SIGNAL ;
    ANTENNAPARTIALMETALAREA 15.8952 LAYER met3  ;
    ANTENNAPARTIALMETALSIDEAREA 85.24 LAYER met3  ;
    PORT
      LAYER met3 ;
        RECT 2900.250000 32.600000 2907.450000 33.800000 ;
    END
  END la_oenb[125]
  PIN la_oenb[124]
    DIRECTION INPUT ;
    USE SIGNAL ;
    ANTENNAPARTIALMETALAREA 16.9482 LAYER met3  ;
    ANTENNAPARTIALMETALSIDEAREA 90.856 LAYER met3  ;
    PORT
      LAYER met3 ;
        RECT 2882.770000 32.600000 2889.970000 33.800000 ;
    END
  END la_oenb[124]
  PIN la_oenb[123]
    DIRECTION INPUT ;
    USE SIGNAL ;
    ANTENNAPARTIALMETALAREA 16.1082 LAYER met3  ;
    ANTENNAPARTIALMETALSIDEAREA 86.376 LAYER met3  ;
    PORT
      LAYER met3 ;
        RECT 2864.830000 32.600000 2872.030000 33.800000 ;
    END
  END la_oenb[123]
  PIN la_oenb[122]
    DIRECTION INPUT ;
    USE SIGNAL ;
    ANTENNAPARTIALMETALAREA 0.4584 LAYER met3  ;
    ANTENNAPARTIALMETALSIDEAREA 2.44 LAYER met3  ;
    PORT
      LAYER met3 ;
        RECT 2846.890000 32.600000 2854.090000 33.800000 ;
    END
  END la_oenb[122]
  PIN la_oenb[121]
    DIRECTION INPUT ;
    USE SIGNAL ;
    ANTENNAPARTIALMETALAREA 15.4404 LAYER met3  ;
    ANTENNAPARTIALMETALSIDEAREA 82.344 LAYER met3  ;
    PORT
      LAYER met3 ;
        RECT 2829.410000 32.600000 2836.610000 33.800000 ;
    END
  END la_oenb[121]
  PIN la_oenb[120]
    DIRECTION INPUT ;
    USE SIGNAL ;
    ANTENNAPARTIALMETALAREA 0.2754 LAYER met3  ;
    ANTENNAPARTIALMETALSIDEAREA 1.464 LAYER met3  ;
    PORT
      LAYER met3 ;
        RECT 2811.470000 32.600000 2818.670000 33.800000 ;
    END
  END la_oenb[120]
  PIN la_oenb[119]
    DIRECTION INPUT ;
    USE SIGNAL ;
    ANTENNAPARTIALMETALAREA 15.4338 LAYER met3  ;
    ANTENNAPARTIALMETALSIDEAREA 82.784 LAYER met3  ;
    PORT
      LAYER met3 ;
        RECT 2793.990000 32.600000 2801.190000 33.800000 ;
    END
  END la_oenb[119]
  PIN la_oenb[118]
    DIRECTION INPUT ;
    USE SIGNAL ;
    ANTENNAPARTIALMETALAREA 0.2754 LAYER met3  ;
    ANTENNAPARTIALMETALSIDEAREA 1.464 LAYER met3  ;
    PORT
      LAYER met3 ;
        RECT 2776.050000 32.600000 2783.250000 33.800000 ;
    END
  END la_oenb[118]
  PIN la_oenb[117]
    DIRECTION INPUT ;
    USE SIGNAL ;
    ANTENNAPARTIALMETALAREA 15.8898 LAYER met3  ;
    ANTENNAPARTIALMETALSIDEAREA 85.216 LAYER met3  ;
    PORT
      LAYER met3 ;
        RECT 2758.570000 32.600000 2765.770000 33.800000 ;
    END
  END la_oenb[117]
  PIN la_oenb[116]
    DIRECTION INPUT ;
    USE SIGNAL ;
    ANTENNAPARTIALMETALAREA 15.3858 LAYER met3  ;
    ANTENNAPARTIALMETALSIDEAREA 82.528 LAYER met3  ;
    PORT
      LAYER met3 ;
        RECT 2740.630000 32.600000 2747.830000 33.800000 ;
    END
  END la_oenb[116]
  PIN la_oenb[115]
    DIRECTION INPUT ;
    USE SIGNAL ;
    ANTENNAPARTIALMETALAREA 15.5274 LAYER met3  ;
    ANTENNAPARTIALMETALSIDEAREA 82.808 LAYER met3  ;
    PORT
      LAYER met3 ;
        RECT 2723.150000 32.600000 2730.350000 33.800000 ;
    END
  END la_oenb[115]
  PIN la_oenb[114]
    DIRECTION INPUT ;
    USE SIGNAL ;
    ANTENNAPARTIALMETALAREA 0.2754 LAYER met3  ;
    ANTENNAPARTIALMETALSIDEAREA 1.464 LAYER met3  ;
    PORT
      LAYER met3 ;
        RECT 2705.210000 32.600000 2712.410000 33.800000 ;
    END
  END la_oenb[114]
  PIN la_oenb[113]
    DIRECTION INPUT ;
    USE SIGNAL ;
    ANTENNAPARTIALMETALAREA 14.5608 LAYER met3  ;
    ANTENNAPARTIALMETALSIDEAREA 78.128 LAYER met3  ;
    PORT
      LAYER met3 ;
        RECT 2687.730000 32.600000 2694.930000 33.800000 ;
    END
  END la_oenb[113]
  PIN la_oenb[112]
    DIRECTION INPUT ;
    USE SIGNAL ;
    ANTENNAPARTIALMETALAREA 14.4264 LAYER met3  ;
    ANTENNAPARTIALMETALSIDEAREA 76.936 LAYER met3  ;
    PORT
      LAYER met3 ;
        RECT 2669.790000 32.600000 2676.990000 33.800000 ;
    END
  END la_oenb[112]
  PIN la_oenb[111]
    DIRECTION INPUT ;
    USE SIGNAL ;
    ANTENNAPARTIALMETALAREA 0.2754 LAYER met3  ;
    ANTENNAPARTIALMETALSIDEAREA 1.464 LAYER met3  ;
    PORT
      LAYER met3 ;
        RECT 2651.850000 32.600000 2659.050000 33.800000 ;
    END
  END la_oenb[111]
  PIN la_oenb[110]
    DIRECTION INPUT ;
    USE SIGNAL ;
    ANTENNAPARTIALMETALAREA 14.7402 LAYER met3  ;
    ANTENNAPARTIALMETALSIDEAREA 79.08 LAYER met3  ;
    PORT
      LAYER met3 ;
        RECT 2634.370000 32.600000 2641.570000 33.800000 ;
    END
  END la_oenb[110]
  PIN la_oenb[109]
    DIRECTION INPUT ;
    USE SIGNAL ;
    ANTENNAPARTIALMETALAREA 13.7328 LAYER met3  ;
    ANTENNAPARTIALMETALSIDEAREA 73.712 LAYER met3  ;
    PORT
      LAYER met3 ;
        RECT 2616.430000 32.600000 2623.630000 33.800000 ;
    END
  END la_oenb[109]
  PIN la_oenb[108]
    DIRECTION INPUT ;
    USE SIGNAL ;
    ANTENNAPARTIALMETALAREA 14.0052 LAYER met3  ;
    ANTENNAPARTIALMETALSIDEAREA 75.16 LAYER met3  ;
    PORT
      LAYER met3 ;
        RECT 2598.950000 32.600000 2606.150000 33.800000 ;
    END
  END la_oenb[108]
  PIN la_oenb[107]
    DIRECTION INPUT ;
    USE SIGNAL ;
    ANTENNAPARTIALMETALAREA 0.2754 LAYER met3  ;
    ANTENNAPARTIALMETALSIDEAREA 1.464 LAYER met3  ;
    PORT
      LAYER met3 ;
        RECT 2581.010000 32.600000 2588.210000 33.800000 ;
    END
  END la_oenb[107]
  PIN la_oenb[106]
    DIRECTION INPUT ;
    USE SIGNAL ;
    ANTENNAPARTIALMETALAREA 13.9602 LAYER met3  ;
    ANTENNAPARTIALMETALSIDEAREA 74.92 LAYER met3  ;
    PORT
      LAYER met3 ;
        RECT 2563.530000 32.600000 2570.730000 33.800000 ;
    END
  END la_oenb[106]
  PIN la_oenb[105]
    DIRECTION INPUT ;
    USE SIGNAL ;
    ANTENNAPARTIALMETALAREA 9.7788 LAYER met3  ;
    ANTENNAPARTIALMETALSIDEAREA 52.624 LAYER met3  ;
    PORT
      LAYER met3 ;
        RECT 2545.590000 32.600000 2552.790000 33.800000 ;
    END
  END la_oenb[105]
  PIN la_oenb[104]
    DIRECTION INPUT ;
    USE SIGNAL ;
    ANTENNAPARTIALMETALAREA 14.1144 LAYER met3  ;
    ANTENNAPARTIALMETALSIDEAREA 75.272 LAYER met3  ;
    PORT
      LAYER met3 ;
        RECT 2528.110000 32.600000 2535.310000 33.800000 ;
    END
  END la_oenb[104]
  PIN la_oenb[103]
    DIRECTION INPUT ;
    USE SIGNAL ;
    ANTENNAPARTIALMETALAREA 12.7254 LAYER met3  ;
    ANTENNAPARTIALMETALSIDEAREA 67.864 LAYER met3  ;
    PORT
      LAYER met3 ;
        RECT 2510.170000 32.600000 2517.370000 33.800000 ;
    END
  END la_oenb[103]
  PIN la_oenb[102]
    DIRECTION INPUT ;
    USE SIGNAL ;
    ANTENNAPARTIALMETALAREA 0.2754 LAYER met3  ;
    ANTENNAPARTIALMETALSIDEAREA 1.464 LAYER met3  ;
    PORT
      LAYER met3 ;
        RECT 2492.230000 32.600000 2499.430000 33.800000 ;
    END
  END la_oenb[102]
  PIN la_oenb[101]
    DIRECTION INPUT ;
    USE SIGNAL ;
    ANTENNAPARTIALMETALAREA 11.9388 LAYER met3  ;
    ANTENNAPARTIALMETALSIDEAREA 64.144 LAYER met3  ;
    PORT
      LAYER met3 ;
        RECT 2474.750000 32.600000 2481.950000 33.800000 ;
    END
  END la_oenb[101]
  PIN la_oenb[100]
    DIRECTION INPUT ;
    USE SIGNAL ;
    ANTENNAPARTIALMETALAREA 12.3528 LAYER met3  ;
    ANTENNAPARTIALMETALSIDEAREA 66.352 LAYER met3  ;
    PORT
      LAYER met3 ;
        RECT 2456.810000 32.600000 2464.010000 33.800000 ;
    END
  END la_oenb[100]
  PIN la_oenb[99]
    DIRECTION INPUT ;
    USE SIGNAL ;
    ANTENNAPARTIALMETALAREA 12.6894 LAYER met3  ;
    ANTENNAPARTIALMETALSIDEAREA 67.672 LAYER met3  ;
    PORT
      LAYER met3 ;
        RECT 2439.330000 32.600000 2446.530000 33.800000 ;
    END
  END la_oenb[99]
  PIN la_oenb[98]
    DIRECTION INPUT ;
    USE SIGNAL ;
    ANTENNAPARTIALMETALAREA 12.7224 LAYER met3  ;
    ANTENNAPARTIALMETALSIDEAREA 67.848 LAYER met3  ;
    PORT
      LAYER met3 ;
        RECT 2421.390000 32.600000 2428.590000 33.800000 ;
    END
  END la_oenb[98]
  PIN la_oenb[97]
    DIRECTION INPUT ;
    USE SIGNAL ;
    ANTENNAPARTIALMETALAREA 12.4134 LAYER met3  ;
    ANTENNAPARTIALMETALSIDEAREA 66.2 LAYER met3  ;
    PORT
      LAYER met3 ;
        RECT 2403.910000 32.600000 2411.110000 33.800000 ;
    END
  END la_oenb[97]
  PIN la_oenb[96]
    DIRECTION INPUT ;
    USE SIGNAL ;
    ANTENNAPARTIALMETALAREA 11.8944 LAYER met3  ;
    ANTENNAPARTIALMETALSIDEAREA 63.432 LAYER met3  ;
    PORT
      LAYER met3 ;
        RECT 2385.970000 32.600000 2393.170000 33.800000 ;
    END
  END la_oenb[96]
  PIN la_oenb[95]
    DIRECTION INPUT ;
    USE SIGNAL ;
    ANTENNAPARTIALMETALAREA 11.4798 LAYER met3  ;
    ANTENNAPARTIALMETALSIDEAREA 61.696 LAYER met3  ;
    PORT
      LAYER met3 ;
        RECT 2368.490000 32.600000 2375.690000 33.800000 ;
    END
  END la_oenb[95]
  PIN la_oenb[94]
    DIRECTION INPUT ;
    USE SIGNAL ;
    ANTENNAPARTIALMETALAREA 11.8494 LAYER met3  ;
    ANTENNAPARTIALMETALSIDEAREA 63.192 LAYER met3  ;
    PORT
      LAYER met3 ;
        RECT 2350.550000 32.600000 2357.750000 33.800000 ;
    END
  END la_oenb[94]
  PIN la_oenb[93]
    DIRECTION INPUT ;
    USE SIGNAL ;
    ANTENNAPARTIALMETALAREA 12.2754 LAYER met3  ;
    ANTENNAPARTIALMETALSIDEAREA 65.464 LAYER met3  ;
    PORT
      LAYER met3 ;
        RECT 2333.070000 32.600000 2340.270000 33.800000 ;
    END
  END la_oenb[93]
  PIN la_oenb[92]
    DIRECTION INPUT ;
    USE SIGNAL ;
    PORT
      LAYER met3 ;
        RECT 2315.130000 32.600000 2322.330000 33.800000 ;
    END
  END la_oenb[92]
  PIN la_oenb[91]
    DIRECTION INPUT ;
    USE SIGNAL ;
    ANTENNAPARTIALMETALAREA 10.8822 LAYER met3  ;
    ANTENNAPARTIALMETALSIDEAREA 58.504 LAYER met3  ;
    PORT
      LAYER met3 ;
        RECT 2297.190000 32.600000 2304.390000 33.800000 ;
    END
  END la_oenb[91]
  PIN la_oenb[90]
    DIRECTION INPUT ;
    USE SIGNAL ;
    ANTENNAPARTIALMETALAREA 10.8984 LAYER met3  ;
    ANTENNAPARTIALMETALSIDEAREA 58.12 LAYER met3  ;
    PORT
      LAYER met3 ;
        RECT 2279.710000 32.600000 2286.910000 33.800000 ;
    END
  END la_oenb[90]
  PIN la_oenb[89]
    DIRECTION INPUT ;
    USE SIGNAL ;
    ANTENNAPARTIALMETALAREA 10.1448 LAYER met3  ;
    ANTENNAPARTIALMETALSIDEAREA 54.576 LAYER met3  ;
    PORT
      LAYER met3 ;
        RECT 2261.770000 32.600000 2268.970000 33.800000 ;
    END
  END la_oenb[89]
  PIN la_oenb[88]
    DIRECTION INPUT ;
    USE SIGNAL ;
    ANTENNAPARTIALMETALAREA 10.5588 LAYER met3  ;
    ANTENNAPARTIALMETALSIDEAREA 56.784 LAYER met3  ;
    PORT
      LAYER met3 ;
        RECT 2244.290000 32.600000 2251.490000 33.800000 ;
    END
  END la_oenb[88]
  PIN la_oenb[87]
    DIRECTION INPUT ;
    USE SIGNAL ;
    ANTENNAPARTIALMETALAREA 10.7604 LAYER met3  ;
    ANTENNAPARTIALMETALSIDEAREA 57.384 LAYER met3  ;
    PORT
      LAYER met3 ;
        RECT 2226.350000 32.600000 2233.550000 33.800000 ;
    END
  END la_oenb[87]
  PIN la_oenb[86]
    DIRECTION INPUT ;
    USE SIGNAL ;
    ANTENNAPARTIALMETALAREA 10.2828 LAYER met3  ;
    ANTENNAPARTIALMETALSIDEAREA 55.312 LAYER met3  ;
    PORT
      LAYER met3 ;
        RECT 2208.870000 32.600000 2216.070000 33.800000 ;
    END
  END la_oenb[86]
  PIN la_oenb[85]
    DIRECTION INPUT ;
    USE SIGNAL ;
    PORT
      LAYER met3 ;
        RECT 2190.930000 32.600000 2198.130000 33.800000 ;
    END
  END la_oenb[85]
  PIN la_oenb[84]
    DIRECTION INPUT ;
    USE SIGNAL ;
    ANTENNAPARTIALMETALAREA 9.8688 LAYER met3  ;
    ANTENNAPARTIALMETALSIDEAREA 53.104 LAYER met3  ;
    PORT
      LAYER met3 ;
        RECT 2173.450000 32.600000 2180.650000 33.800000 ;
    END
  END la_oenb[84]
  PIN la_oenb[83]
    DIRECTION INPUT ;
    USE SIGNAL ;
    ANTENNAPARTIALMETALAREA 10.0704 LAYER met3  ;
    ANTENNAPARTIALMETALSIDEAREA 53.704 LAYER met3  ;
    PORT
      LAYER met3 ;
        RECT 2155.510000 32.600000 2162.710000 33.800000 ;
    END
  END la_oenb[83]
  PIN la_oenb[82]
    DIRECTION INPUT ;
    USE SIGNAL ;
    ANTENNAPARTIALMETALAREA 9.3648 LAYER met3  ;
    ANTENNAPARTIALMETALSIDEAREA 50.416 LAYER met3  ;
    PORT
      LAYER met3 ;
        RECT 2137.570000 32.600000 2144.770000 33.800000 ;
    END
  END la_oenb[82]
  PIN la_oenb[81]
    DIRECTION INPUT ;
    USE SIGNAL ;
    ANTENNAPARTIALMETALAREA 9.8724 LAYER met3  ;
    ANTENNAPARTIALMETALSIDEAREA 52.648 LAYER met3  ;
    PORT
      LAYER met3 ;
        RECT 2120.090000 32.600000 2127.290000 33.800000 ;
    END
  END la_oenb[81]
  PIN la_oenb[80]
    DIRECTION INPUT ;
    USE SIGNAL ;
    ANTENNAPARTIALMETALAREA 9.9294 LAYER met3  ;
    ANTENNAPARTIALMETALSIDEAREA 52.952 LAYER met3  ;
    PORT
      LAYER met3 ;
        RECT 2102.150000 32.600000 2109.350000 33.800000 ;
    END
  END la_oenb[80]
  PIN la_oenb[79]
    DIRECTION INPUT ;
    USE SIGNAL ;
    ANTENNAPARTIALMETALAREA 9.9624 LAYER met3  ;
    ANTENNAPARTIALMETALSIDEAREA 53.128 LAYER met3  ;
    PORT
      LAYER met3 ;
        RECT 2084.670000 32.600000 2091.870000 33.800000 ;
    END
  END la_oenb[79]
  PIN la_oenb[78]
    DIRECTION INPUT ;
    USE SIGNAL ;
    ANTENNAPARTIALMETALAREA 9.8694 LAYER met3  ;
    ANTENNAPARTIALMETALSIDEAREA 52.632 LAYER met3  ;
    PORT
      LAYER met3 ;
        RECT 2066.730000 32.600000 2073.930000 33.800000 ;
    END
  END la_oenb[78]
  PIN la_oenb[77]
    DIRECTION INPUT ;
    USE SIGNAL ;
    ANTENNAPARTIALMETALAREA 7.2018 LAYER met3  ;
    ANTENNAPARTIALMETALSIDEAREA 38.88 LAYER met3  ;
    PORT
      LAYER met3 ;
        RECT 2049.250000 32.600000 2056.450000 33.800000 ;
    END
  END la_oenb[77]
  PIN la_oenb[76]
    DIRECTION INPUT ;
    USE SIGNAL ;
    ANTENNAPARTIALMETALAREA 9.2874 LAYER met3  ;
    ANTENNAPARTIALMETALSIDEAREA 49.528 LAYER met3  ;
    PORT
      LAYER met3 ;
        RECT 2031.310000 32.600000 2038.510000 33.800000 ;
    END
  END la_oenb[76]
  PIN la_oenb[75]
    DIRECTION INPUT ;
    USE SIGNAL ;
    PORT
      LAYER met3 ;
        RECT 2013.830000 32.600000 2021.030000 33.800000 ;
    END
  END la_oenb[75]
  PIN la_oenb[74]
    DIRECTION INPUT ;
    USE SIGNAL ;
    ANTENNAPARTIALMETALAREA 8.4888 LAYER met3  ;
    ANTENNAPARTIALMETALSIDEAREA 45.744 LAYER met3  ;
    PORT
      LAYER met3 ;
        RECT 1995.890000 32.600000 2003.090000 33.800000 ;
    END
  END la_oenb[74]
  PIN la_oenb[73]
    DIRECTION INPUT ;
    USE SIGNAL ;
    PORT
      LAYER met3 ;
        RECT 1978.410000 32.600000 1985.610000 33.800000 ;
    END
  END la_oenb[73]
  PIN la_oenb[72]
    DIRECTION INPUT ;
    USE SIGNAL ;
    ANTENNAPARTIALMETALAREA 8.3958 LAYER met3  ;
    ANTENNAPARTIALMETALSIDEAREA 45.248 LAYER met3  ;
    PORT
      LAYER met3 ;
        RECT 1960.470000 32.600000 1967.670000 33.800000 ;
    END
  END la_oenb[72]
  PIN la_oenb[71]
    DIRECTION INPUT ;
    USE SIGNAL ;
    ANTENNAPARTIALMETALAREA 7.8174 LAYER met3  ;
    ANTENNAPARTIALMETALSIDEAREA 41.688 LAYER met3  ;
    PORT
      LAYER met3 ;
        RECT 1942.530000 32.600000 1949.730000 33.800000 ;
    END
  END la_oenb[71]
  PIN la_oenb[70]
    DIRECTION INPUT ;
    USE SIGNAL ;
    ANTENNAPARTIALMETALAREA 8.4594 LAYER met3  ;
    ANTENNAPARTIALMETALSIDEAREA 45.112 LAYER met3  ;
    PORT
      LAYER met3 ;
        RECT 1925.050000 32.600000 1932.250000 33.800000 ;
    END
  END la_oenb[70]
  PIN la_oenb[69]
    DIRECTION INPUT ;
    USE SIGNAL ;
    PORT
      LAYER met3 ;
        RECT 1907.110000 32.600000 1914.310000 33.800000 ;
    END
  END la_oenb[69]
  PIN la_oenb[68]
    DIRECTION INPUT ;
    USE SIGNAL ;
    PORT
      LAYER met3 ;
        RECT 1889.630000 32.600000 1896.830000 33.800000 ;
    END
  END la_oenb[68]
  PIN la_oenb[67]
    DIRECTION INPUT ;
    USE SIGNAL ;
    ANTENNAPARTIALMETALAREA 6.7428 LAYER met3  ;
    ANTENNAPARTIALMETALSIDEAREA 36.432 LAYER met3  ;
    PORT
      LAYER met3 ;
        RECT 1871.690000 32.600000 1878.890000 33.800000 ;
    END
  END la_oenb[67]
  PIN la_oenb[66]
    DIRECTION INPUT ;
    USE SIGNAL ;
    PORT
      LAYER met3 ;
        RECT 1854.210000 32.600000 1861.410000 33.800000 ;
    END
  END la_oenb[66]
  PIN la_oenb[65]
    DIRECTION INPUT ;
    USE SIGNAL ;
    ANTENNAPARTIALMETALAREA 7.7544 LAYER met3  ;
    ANTENNAPARTIALMETALSIDEAREA 41.352 LAYER met3  ;
    PORT
      LAYER met3 ;
        RECT 1836.270000 32.600000 1843.470000 33.800000 ;
    END
  END la_oenb[65]
  PIN la_oenb[64]
    DIRECTION INPUT ;
    USE SIGNAL ;
    ANTENNAPARTIALMETALAREA 7.3554 LAYER met3  ;
    ANTENNAPARTIALMETALSIDEAREA 39.224 LAYER met3  ;
    PORT
      LAYER met3 ;
        RECT 1818.790000 32.600000 1825.990000 33.800000 ;
    END
  END la_oenb[64]
  PIN la_oenb[63]
    DIRECTION INPUT ;
    USE SIGNAL ;
    ANTENNAPARTIALMETALAREA 7.2954 LAYER met3  ;
    ANTENNAPARTIALMETALSIDEAREA 38.904 LAYER met3  ;
    PORT
      LAYER met3 ;
        RECT 1800.850000 32.600000 1808.050000 33.800000 ;
    END
  END la_oenb[63]
  PIN la_oenb[62]
    DIRECTION INPUT ;
    USE SIGNAL ;
    ANTENNAPARTIALMETALAREA 6.8964 LAYER met3  ;
    ANTENNAPARTIALMETALSIDEAREA 36.776 LAYER met3  ;
    PORT
      LAYER met3 ;
        RECT 1782.910000 32.600000 1790.110000 33.800000 ;
    END
  END la_oenb[62]
  PIN la_oenb[61]
    DIRECTION INPUT ;
    USE SIGNAL ;
    PORT
      LAYER met3 ;
        RECT 1765.430000 32.600000 1772.630000 33.800000 ;
    END
  END la_oenb[61]
  PIN la_oenb[60]
    DIRECTION INPUT ;
    USE SIGNAL ;
    ANTENNAPARTIALMETALAREA 6.8328 LAYER met3  ;
    ANTENNAPARTIALMETALSIDEAREA 36.912 LAYER met3  ;
    PORT
      LAYER met3 ;
        RECT 1747.490000 32.600000 1754.690000 33.800000 ;
    END
  END la_oenb[60]
  PIN la_oenb[59]
    DIRECTION INPUT ;
    USE SIGNAL ;
    PORT
      LAYER met3 ;
        RECT 1730.010000 32.600000 1737.210000 33.800000 ;
    END
  END la_oenb[59]
  PIN la_oenb[58]
    DIRECTION INPUT ;
    USE SIGNAL ;
    ANTENNAPARTIALMETALAREA 6.4674 LAYER met3  ;
    ANTENNAPARTIALMETALSIDEAREA 34.488 LAYER met3  ;
    PORT
      LAYER met3 ;
        RECT 1712.070000 32.600000 1719.270000 33.800000 ;
    END
  END la_oenb[58]
  PIN la_oenb[57]
    DIRECTION INPUT ;
    USE SIGNAL ;
    PORT
      LAYER met3 ;
        RECT 1694.590000 32.600000 1701.790000 33.800000 ;
    END
  END la_oenb[57]
  PIN la_oenb[56]
    DIRECTION INPUT ;
    USE SIGNAL ;
    ANTENNAPARTIALMETALAREA 5.7924 LAYER met3  ;
    ANTENNAPARTIALMETALSIDEAREA 30.888 LAYER met3  ;
    PORT
      LAYER met3 ;
        RECT 1676.650000 32.600000 1683.850000 33.800000 ;
    END
  END la_oenb[56]
  PIN la_oenb[55]
    DIRECTION INPUT ;
    USE SIGNAL ;
    ANTENNAPARTIALMETALAREA 6.2514 LAYER met3  ;
    ANTENNAPARTIALMETALSIDEAREA 33.336 LAYER met3  ;
    PORT
      LAYER met3 ;
        RECT 1659.170000 32.600000 1666.370000 33.800000 ;
    END
  END la_oenb[55]
  PIN la_oenb[54]
    DIRECTION INPUT ;
    USE SIGNAL ;
    ANTENNAPARTIALMETALAREA 5.7774 LAYER met3  ;
    ANTENNAPARTIALMETALSIDEAREA 30.808 LAYER met3  ;
    PORT
      LAYER met3 ;
        RECT 1641.230000 32.600000 1648.430000 33.800000 ;
    END
  END la_oenb[54]
  PIN la_oenb[53]
    DIRECTION INPUT ;
    USE SIGNAL ;
    ANTENNAPARTIALMETALAREA 5.9154 LAYER met3  ;
    ANTENNAPARTIALMETALSIDEAREA 31.544 LAYER met3  ;
    PORT
      LAYER met3 ;
        RECT 1623.750000 32.600000 1630.950000 33.800000 ;
    END
  END la_oenb[53]
  PIN la_oenb[52]
    DIRECTION INPUT ;
    USE SIGNAL ;
    ANTENNAPARTIALMETALAREA 4.8744 LAYER met3  ;
    ANTENNAPARTIALMETALSIDEAREA 25.992 LAYER met3  ;
    PORT
      LAYER met3 ;
        RECT 1605.810000 32.600000 1613.010000 33.800000 ;
    END
  END la_oenb[52]
  PIN la_oenb[51]
    DIRECTION INPUT ;
    USE SIGNAL ;
    ANTENNAPARTIALMETALAREA 5.2404 LAYER met3  ;
    ANTENNAPARTIALMETALSIDEAREA 27.944 LAYER met3  ;
    PORT
      LAYER met3 ;
        RECT 1587.870000 32.600000 1595.070000 33.800000 ;
    END
  END la_oenb[51]
  PIN la_oenb[50]
    DIRECTION INPUT ;
    USE SIGNAL ;
    ANTENNAPARTIALMETALAREA 5.3634 LAYER met3  ;
    ANTENNAPARTIALMETALSIDEAREA 28.6 LAYER met3  ;
    PORT
      LAYER met3 ;
        RECT 1570.390000 32.600000 1577.590000 33.800000 ;
    END
  END la_oenb[50]
  PIN la_oenb[49]
    DIRECTION INPUT ;
    USE SIGNAL ;
    PORT
      LAYER met3 ;
        RECT 1552.450000 32.600000 1559.650000 33.800000 ;
    END
  END la_oenb[49]
  PIN la_oenb[48]
    DIRECTION INPUT ;
    USE SIGNAL ;
    ANTENNAPARTIALMETALAREA 5.1474 LAYER met3  ;
    ANTENNAPARTIALMETALSIDEAREA 27.448 LAYER met3  ;
    PORT
      LAYER met3 ;
        RECT 1534.970000 32.600000 1542.170000 33.800000 ;
    END
  END la_oenb[48]
  PIN la_oenb[47]
    DIRECTION INPUT ;
    USE SIGNAL ;
    ANTENNAPARTIALMETALAREA 5.0094 LAYER met3  ;
    ANTENNAPARTIALMETALSIDEAREA 26.712 LAYER met3  ;
    PORT
      LAYER met3 ;
        RECT 1517.030000 32.600000 1524.230000 33.800000 ;
    END
  END la_oenb[47]
  PIN la_oenb[46]
    DIRECTION INPUT ;
    USE SIGNAL ;
    ANTENNAPARTIALMETALAREA 4.8114 LAYER met3  ;
    ANTENNAPARTIALMETALSIDEAREA 25.656 LAYER met3  ;
    PORT
      LAYER met3 ;
        RECT 1499.550000 32.600000 1506.750000 33.800000 ;
    END
  END la_oenb[46]
  PIN la_oenb[45]
    DIRECTION INPUT ;
    USE SIGNAL ;
    ANTENNAPARTIALMETALAREA 3.7704 LAYER met3  ;
    ANTENNAPARTIALMETALSIDEAREA 20.104 LAYER met3  ;
    PORT
      LAYER met3 ;
        RECT 1481.610000 32.600000 1488.810000 33.800000 ;
    END
  END la_oenb[45]
  PIN la_oenb[44]
    DIRECTION INPUT ;
    USE SIGNAL ;
    ANTENNAPARTIALMETALAREA 4.2744 LAYER met3  ;
    ANTENNAPARTIALMETALSIDEAREA 22.792 LAYER met3  ;
    PORT
      LAYER met3 ;
        RECT 1464.130000 32.600000 1471.330000 33.800000 ;
    END
  END la_oenb[44]
  PIN la_oenb[43]
    DIRECTION INPUT ;
    USE SIGNAL ;
    ANTENNAPARTIALMETALAREA 4.2594 LAYER met3  ;
    ANTENNAPARTIALMETALSIDEAREA 22.712 LAYER met3  ;
    PORT
      LAYER met3 ;
        RECT 1446.190000 32.600000 1453.390000 33.800000 ;
    END
  END la_oenb[43]
  PIN la_oenb[42]
    DIRECTION INPUT ;
    USE SIGNAL ;
    ANTENNAPARTIALMETALAREA 3.5874 LAYER met3  ;
    ANTENNAPARTIALMETALSIDEAREA 19.128 LAYER met3  ;
    PORT
      LAYER met3 ;
        RECT 1428.250000 32.600000 1435.450000 33.800000 ;
    END
  END la_oenb[42]
  PIN la_oenb[41]
    DIRECTION INPUT ;
    USE SIGNAL ;
    ANTENNAPARTIALMETALAREA 3.9834 LAYER met3  ;
    ANTENNAPARTIALMETALSIDEAREA 21.24 LAYER met3  ;
    PORT
      LAYER met3 ;
        RECT 1410.770000 32.600000 1417.970000 33.800000 ;
    END
  END la_oenb[41]
  PIN la_oenb[40]
    DIRECTION INPUT ;
    USE SIGNAL ;
    ANTENNAPARTIALMETALAREA 3.9054 LAYER met3  ;
    ANTENNAPARTIALMETALSIDEAREA 20.824 LAYER met3  ;
    PORT
      LAYER met3 ;
        RECT 1392.830000 32.600000 1400.030000 33.800000 ;
    END
  END la_oenb[40]
  PIN la_oenb[39]
    DIRECTION INPUT ;
    USE SIGNAL ;
    ANTENNAPARTIALMETALAREA 3.7674 LAYER met3  ;
    ANTENNAPARTIALMETALSIDEAREA 20.088 LAYER met3  ;
    PORT
      LAYER met3 ;
        RECT 1375.350000 32.600000 1382.550000 33.800000 ;
    END
  END la_oenb[39]
  PIN la_oenb[38]
    DIRECTION INPUT ;
    USE SIGNAL ;
    ANTENNAPARTIALMETALAREA 3.3084 LAYER met3  ;
    ANTENNAPARTIALMETALSIDEAREA 17.64 LAYER met3  ;
    PORT
      LAYER met3 ;
        RECT 1357.410000 32.600000 1364.610000 33.800000 ;
    END
  END la_oenb[38]
  PIN la_oenb[37]
    DIRECTION INPUT ;
    USE SIGNAL ;
    ANTENNAPARTIALMETALAREA 2.7594 LAYER met3  ;
    ANTENNAPARTIALMETALSIDEAREA 14.712 LAYER met3  ;
    PORT
      LAYER met3 ;
        RECT 1339.930000 32.600000 1347.130000 33.800000 ;
    END
  END la_oenb[37]
  PIN la_oenb[36]
    DIRECTION INPUT ;
    USE SIGNAL ;
    ANTENNAPARTIALMETALAREA 2.9274 LAYER met3  ;
    ANTENNAPARTIALMETALSIDEAREA 15.608 LAYER met3  ;
    PORT
      LAYER met3 ;
        RECT 1321.990000 32.600000 1329.190000 33.800000 ;
    END
  END la_oenb[36]
  PIN la_oenb[35]
    DIRECTION INPUT ;
    USE SIGNAL ;
    ANTENNAPARTIALMETALAREA 2.8494 LAYER met3  ;
    ANTENNAPARTIALMETALSIDEAREA 15.192 LAYER met3  ;
    PORT
      LAYER met3 ;
        RECT 1304.510000 32.600000 1311.710000 33.800000 ;
    END
  END la_oenb[35]
  PIN la_oenb[34]
    DIRECTION INPUT ;
    USE SIGNAL ;
    ANTENNAPARTIALMETALAREA 2.3454 LAYER met3  ;
    ANTENNAPARTIALMETALSIDEAREA 12.504 LAYER met3  ;
    PORT
      LAYER met3 ;
        RECT 1286.570000 32.600000 1293.770000 33.800000 ;
    END
  END la_oenb[34]
  PIN la_oenb[33]
    DIRECTION INPUT ;
    USE SIGNAL ;
    ANTENNAPARTIALMETALAREA 2.2074 LAYER met3  ;
    ANTENNAPARTIALMETALSIDEAREA 11.768 LAYER met3  ;
    PORT
      LAYER met3 ;
        RECT 1268.630000 32.600000 1275.830000 33.800000 ;
    END
  END la_oenb[33]
  PIN la_oenb[32]
    DIRECTION INPUT ;
    USE SIGNAL ;
    ANTENNAPARTIALMETALAREA 2.0694 LAYER met3  ;
    ANTENNAPARTIALMETALSIDEAREA 11.032 LAYER met3  ;
    PORT
      LAYER met3 ;
        RECT 1251.150000 32.600000 1258.350000 33.800000 ;
    END
  END la_oenb[32]
  PIN la_oenb[31]
    DIRECTION INPUT ;
    USE SIGNAL ;
    ANTENNAPARTIALMETALAREA 1.2414 LAYER met3  ;
    ANTENNAPARTIALMETALSIDEAREA 6.616 LAYER met3  ;
    PORT
      LAYER met3 ;
        RECT 1233.210000 32.600000 1240.410000 33.800000 ;
    END
  END la_oenb[31]
  PIN la_oenb[30]
    DIRECTION INPUT ;
    USE SIGNAL ;
    ANTENNAPARTIALMETALAREA 1.9314 LAYER met3  ;
    ANTENNAPARTIALMETALSIDEAREA 10.296 LAYER met3  ;
    PORT
      LAYER met3 ;
        RECT 1215.730000 32.600000 1222.930000 33.800000 ;
    END
  END la_oenb[30]
  PIN la_oenb[29]
    DIRECTION INPUT ;
    USE SIGNAL ;
    ANTENNAPARTIALMETALAREA 0.8274 LAYER met3  ;
    ANTENNAPARTIALMETALSIDEAREA 4.408 LAYER met3  ;
    PORT
      LAYER met3 ;
        RECT 1197.790000 32.600000 1204.990000 33.800000 ;
    END
  END la_oenb[29]
  PIN la_oenb[28]
    DIRECTION INPUT ;
    USE SIGNAL ;
    ANTENNAPARTIALMETALAREA 1.3794 LAYER met3  ;
    ANTENNAPARTIALMETALSIDEAREA 7.352 LAYER met3  ;
    PORT
      LAYER met3 ;
        RECT 1180.310000 32.600000 1187.510000 33.800000 ;
    END
  END la_oenb[28]
  PIN la_oenb[27]
    DIRECTION INPUT ;
    USE SIGNAL ;
    ANTENNAPARTIALMETALAREA 1.2414 LAYER met3  ;
    ANTENNAPARTIALMETALSIDEAREA 6.616 LAYER met3  ;
    PORT
      LAYER met3 ;
        RECT 1162.370000 32.600000 1169.570000 33.800000 ;
    END
  END la_oenb[27]
  PIN la_oenb[26]
    DIRECTION INPUT ;
    USE SIGNAL ;
    ANTENNAPARTIALMETALAREA 1.1034 LAYER met3  ;
    ANTENNAPARTIALMETALSIDEAREA 5.88 LAYER met3  ;
    PORT
      LAYER met3 ;
        RECT 1144.890000 32.600000 1152.090000 33.800000 ;
    END
  END la_oenb[26]
  PIN la_oenb[25]
    DIRECTION INPUT ;
    USE SIGNAL ;
    ANTENNAPARTIALMETALAREA 0.9654 LAYER met3  ;
    ANTENNAPARTIALMETALSIDEAREA 5.144 LAYER met3  ;
    PORT
      LAYER met3 ;
        RECT 1126.950000 32.600000 1134.150000 33.800000 ;
    END
  END la_oenb[25]
  PIN la_oenb[24]
    DIRECTION INPUT ;
    USE SIGNAL ;
    ANTENNAPARTIALMETALAREA 0.8274 LAYER met3  ;
    ANTENNAPARTIALMETALSIDEAREA 4.408 LAYER met3  ;
    PORT
      LAYER met3 ;
        RECT 1109.470000 32.600000 1116.670000 33.800000 ;
    END
  END la_oenb[24]
  PIN la_oenb[23]
    DIRECTION INPUT ;
    USE SIGNAL ;
    ANTENNAPARTIALMETALAREA 0.6894 LAYER met3  ;
    ANTENNAPARTIALMETALSIDEAREA 3.672 LAYER met3  ;
    PORT
      LAYER met3 ;
        RECT 1091.530000 32.600000 1098.730000 33.800000 ;
    END
  END la_oenb[23]
  PIN la_oenb[22]
    DIRECTION INPUT ;
    USE SIGNAL ;
    PORT
      LAYER met3 ;
        RECT 1073.590000 32.600000 1080.790000 33.800000 ;
    END
  END la_oenb[22]
  PIN la_oenb[21]
    DIRECTION INPUT ;
    USE SIGNAL ;
    PORT
      LAYER met3 ;
        RECT 1056.110000 32.600000 1063.310000 33.800000 ;
    END
  END la_oenb[21]
  PIN la_oenb[20]
    DIRECTION INPUT ;
    USE SIGNAL ;
    PORT
      LAYER met3 ;
        RECT 1038.170000 32.600000 1045.370000 33.800000 ;
    END
  END la_oenb[20]
  PIN la_oenb[19]
    DIRECTION INPUT ;
    USE SIGNAL ;
    ANTENNAPARTIALMETALAREA 0.4584 LAYER met3  ;
    ANTENNAPARTIALMETALSIDEAREA 2.44 LAYER met3  ;
    PORT
      LAYER met3 ;
        RECT 1020.690000 32.600000 1027.890000 33.800000 ;
    END
  END la_oenb[19]
  PIN la_oenb[18]
    DIRECTION INPUT ;
    USE SIGNAL ;
    ANTENNAPARTIALMETALAREA 0.2754 LAYER met3  ;
    ANTENNAPARTIALMETALSIDEAREA 1.464 LAYER met3  ;
    PORT
      LAYER met3 ;
        RECT 1002.750000 32.600000 1009.950000 33.800000 ;
    END
  END la_oenb[18]
  PIN la_oenb[17]
    DIRECTION INPUT ;
    USE SIGNAL ;
    ANTENNAPARTIALMETALAREA 0.2754 LAYER met3  ;
    ANTENNAPARTIALMETALSIDEAREA 1.464 LAYER met3  ;
    PORT
      LAYER met3 ;
        RECT 985.270000 32.600000 992.470000 33.800000 ;
    END
  END la_oenb[17]
  PIN la_oenb[16]
    DIRECTION INPUT ;
    USE SIGNAL ;
    ANTENNAPARTIALMETALAREA 0.2754 LAYER met3  ;
    ANTENNAPARTIALMETALSIDEAREA 1.464 LAYER met3  ;
    PORT
      LAYER met3 ;
        RECT 967.330000 32.600000 974.530000 33.800000 ;
    END
  END la_oenb[16]
  PIN la_oenb[15]
    DIRECTION INPUT ;
    USE SIGNAL ;
    ANTENNAPARTIALMETALAREA 0.2754 LAYER met3  ;
    ANTENNAPARTIALMETALSIDEAREA 1.464 LAYER met3  ;
    PORT
      LAYER met3 ;
        RECT 949.850000 32.600000 957.050000 33.800000 ;
    END
  END la_oenb[15]
  PIN la_oenb[14]
    DIRECTION INPUT ;
    USE SIGNAL ;
    ANTENNAPARTIALMETALAREA 0.2754 LAYER met3  ;
    ANTENNAPARTIALMETALSIDEAREA 1.464 LAYER met3  ;
    PORT
      LAYER met3 ;
        RECT 931.910000 32.600000 939.110000 33.800000 ;
    END
  END la_oenb[14]
  PIN la_oenb[13]
    DIRECTION INPUT ;
    USE SIGNAL ;
    ANTENNAPARTIALMETALAREA 0.2754 LAYER met3  ;
    ANTENNAPARTIALMETALSIDEAREA 1.464 LAYER met3  ;
    PORT
      LAYER met3 ;
        RECT 913.970000 32.600000 921.170000 33.800000 ;
    END
  END la_oenb[13]
  PIN la_oenb[12]
    DIRECTION INPUT ;
    USE SIGNAL ;
    ANTENNAPARTIALMETALAREA 0.2754 LAYER met3  ;
    ANTENNAPARTIALMETALSIDEAREA 1.464 LAYER met3  ;
    PORT
      LAYER met3 ;
        RECT 896.490000 32.600000 903.690000 33.800000 ;
    END
  END la_oenb[12]
  PIN la_oenb[11]
    DIRECTION INPUT ;
    USE SIGNAL ;
    ANTENNAPARTIALMETALAREA 0.4584 LAYER met3  ;
    ANTENNAPARTIALMETALSIDEAREA 2.44 LAYER met3  ;
    PORT
      LAYER met3 ;
        RECT 878.550000 32.600000 885.750000 33.800000 ;
    END
  END la_oenb[11]
  PIN la_oenb[10]
    DIRECTION INPUT ;
    USE SIGNAL ;
    ANTENNAPARTIALMETALAREA 0.2754 LAYER met3  ;
    ANTENNAPARTIALMETALSIDEAREA 1.464 LAYER met3  ;
    PORT
      LAYER met3 ;
        RECT 861.070000 32.600000 868.270000 33.800000 ;
    END
  END la_oenb[10]
  PIN la_oenb[9]
    DIRECTION INPUT ;
    USE SIGNAL ;
    PORT
      LAYER met3 ;
        RECT 843.130000 32.600000 850.330000 33.800000 ;
    END
  END la_oenb[9]
  PIN la_oenb[8]
    DIRECTION INPUT ;
    USE SIGNAL ;
    ANTENNAPARTIALMETALAREA 0.4584 LAYER met3  ;
    ANTENNAPARTIALMETALSIDEAREA 2.44 LAYER met3  ;
    PORT
      LAYER met3 ;
        RECT 825.650000 32.600000 832.850000 33.800000 ;
    END
  END la_oenb[8]
  PIN la_oenb[7]
    DIRECTION INPUT ;
    USE SIGNAL ;
    ANTENNAPARTIALMETALAREA 0.6894 LAYER met3  ;
    ANTENNAPARTIALMETALSIDEAREA 3.672 LAYER met3  ;
    PORT
      LAYER met3 ;
        RECT 807.710000 32.600000 814.910000 33.800000 ;
    END
  END la_oenb[7]
  PIN la_oenb[6]
    DIRECTION INPUT ;
    USE SIGNAL ;
    ANTENNAPARTIALMETALAREA 0.2754 LAYER met3  ;
    ANTENNAPARTIALMETALSIDEAREA 1.464 LAYER met3  ;
    PORT
      LAYER met3 ;
        RECT 790.230000 32.600000 797.430000 33.800000 ;
    END
  END la_oenb[6]
  PIN la_oenb[5]
    DIRECTION INPUT ;
    USE SIGNAL ;
    ANTENNAPARTIALMETALAREA 1.6554 LAYER met3  ;
    ANTENNAPARTIALMETALSIDEAREA 8.824 LAYER met3  ;
    PORT
      LAYER met3 ;
        RECT 772.290000 32.600000 779.490000 33.800000 ;
    END
  END la_oenb[5]
  PIN la_oenb[4]
    DIRECTION INPUT ;
    USE SIGNAL ;
    ANTENNAPARTIALMETALAREA 0.4584 LAYER met3  ;
    ANTENNAPARTIALMETALSIDEAREA 2.44 LAYER met3  ;
    PORT
      LAYER met3 ;
        RECT 754.810000 32.600000 762.010000 33.800000 ;
    END
  END la_oenb[4]
  PIN la_oenb[3]
    DIRECTION INPUT ;
    USE SIGNAL ;
    ANTENNAPARTIALMETALAREA 2.1144 LAYER met3  ;
    ANTENNAPARTIALMETALSIDEAREA 11.272 LAYER met3  ;
    PORT
      LAYER met3 ;
        RECT 736.870000 32.600000 744.070000 33.800000 ;
    END
  END la_oenb[3]
  PIN la_oenb[2]
    DIRECTION INPUT ;
    USE SIGNAL ;
    ANTENNAPARTIALMETALAREA 0.5514 LAYER met3  ;
    ANTENNAPARTIALMETALSIDEAREA 2.936 LAYER met3  ;
    PORT
      LAYER met3 ;
        RECT 718.930000 32.600000 726.130000 33.800000 ;
    END
  END la_oenb[2]
  PIN la_oenb[1]
    DIRECTION INPUT ;
    USE SIGNAL ;
    ANTENNAPARTIALMETALAREA 2.2074 LAYER met3  ;
    ANTENNAPARTIALMETALSIDEAREA 11.768 LAYER met3  ;
    PORT
      LAYER met3 ;
        RECT 701.450000 32.600000 708.650000 33.800000 ;
    END
  END la_oenb[1]
  PIN la_oenb[0]
    DIRECTION INPUT ;
    USE SIGNAL ;
    ANTENNAPARTIALMETALAREA 0.8274 LAYER met3  ;
    ANTENNAPARTIALMETALSIDEAREA 4.408 LAYER met3  ;
    PORT
      LAYER met3 ;
        RECT 683.510000 32.600000 690.710000 33.800000 ;
    END
  END la_oenb[0]
  PIN io_in[37]
    DIRECTION INPUT ;
    USE SIGNAL ;
    ANTENNAPARTIALMETALAREA 9.7518 LAYER met3  ;
    ANTENNAPARTIALMETALSIDEAREA 52.48 LAYER met3  ;
    PORT
      LAYER met3 ;
        RECT 37.980000 198.980000 45.180000 200.180000 ;
    END
  END io_in[37]
  PIN io_in[36]
    DIRECTION INPUT ;
    USE SIGNAL ;
    ANTENNAPARTIALMETALAREA 9.4308 LAYER met3  ;
    ANTENNAPARTIALMETALSIDEAREA 50.768 LAYER met3  ;
    PORT
      LAYER met3 ;
        RECT 37.980000 394.820000 45.180000 396.020000 ;
    END
  END io_in[36]
  PIN io_in[35]
    DIRECTION INPUT ;
    USE SIGNAL ;
    ANTENNAPARTIALMETALAREA 9.4308 LAYER met3  ;
    ANTENNAPARTIALMETALSIDEAREA 50.768 LAYER met3  ;
    PORT
      LAYER met3 ;
        RECT 37.980000 589.980000 45.180000 591.180000 ;
    END
  END io_in[35]
  PIN io_in[34]
    DIRECTION INPUT ;
    USE SIGNAL ;
    ANTENNAPARTIALMETALAREA 9.4308 LAYER met3  ;
    ANTENNAPARTIALMETALSIDEAREA 50.768 LAYER met3  ;
    PORT
      LAYER met3 ;
        RECT 37.980000 851.100000 45.180000 852.300000 ;
    END
  END io_in[34]
  PIN io_in[33]
    DIRECTION INPUT ;
    USE SIGNAL ;
    ANTENNAPARTIALMETALAREA 65.9542 LAYER met3  ;
    ANTENNAPARTIALMETALSIDEAREA 352.688 LAYER met3  ;
    ANTENNAPARTIALCUTAREA 0.04 LAYER via3  ;
    ANTENNAPARTIALMETALAREA 0.3258 LAYER met4  ;
    ANTENNAPARTIALMETALSIDEAREA 2.208 LAYER met4  ;
    ANTENNAMODEL OXIDE1 ;
    ANTENNAGATEAREA 0.665 LAYER met4  ;
    ANTENNAMAXAREACAR 0.489925 LAYER met4  ;
    ANTENNAMAXSIDEAREACAR 3.3203 LAYER met4  ;
    PORT
      LAYER met3 ;
        RECT 37.980000 1111.540000 45.180000 1112.740000 ;
    END
  END io_in[33]
  PIN io_in[32]
    DIRECTION INPUT ;
    USE SIGNAL ;
    ANTENNAPARTIALMETALAREA 39.9412 LAYER met3  ;
    ANTENNAPARTIALMETALSIDEAREA 213.952 LAYER met3  ;
    ANTENNAPARTIALCUTAREA 0.04 LAYER via3  ;
    ANTENNAPARTIALMETALAREA 9.6348 LAYER met4  ;
    ANTENNAPARTIALMETALSIDEAREA 51.856 LAYER met4  ;
    ANTENNAMODEL OXIDE1 ;
    ANTENNAGATEAREA 0.665 LAYER met4  ;
    ANTENNAMAXAREACAR 14.4884 LAYER met4  ;
    ANTENNAMAXSIDEAREACAR 77.979 LAYER met4  ;
    PORT
      LAYER met3 ;
        RECT 37.980000 1372.660000 45.180000 1373.860000 ;
    END
  END io_in[32]
  PIN io_in[31]
    DIRECTION INPUT ;
    USE SIGNAL ;
    ANTENNAPARTIALMETALAREA 9.5952 LAYER met3  ;
    ANTENNAPARTIALMETALSIDEAREA 51.64 LAYER met3  ;
    ANTENNAMODEL OXIDE1 ;
    ANTENNAGATEAREA 0.665 LAYER met3  ;
    ANTENNAMAXAREACAR 23.5709 LAYER met3  ;
    ANTENNAMAXSIDEAREACAR 120.961 LAYER met3  ;
    ANTENNAMAXCUTCAR 0.137444 LAYER via3  ;
    PORT
      LAYER met3 ;
        RECT 37.980000 1633.100000 45.180000 1634.300000 ;
    END
  END io_in[31]
  PIN io_in[30]
    DIRECTION INPUT ;
    USE SIGNAL ;
    ANTENNAPARTIALMETALAREA 13.3212 LAYER met3  ;
    ANTENNAPARTIALMETALSIDEAREA 71.512 LAYER met3  ;
    ANTENNAMODEL OXIDE1 ;
    ANTENNAGATEAREA 0.665 LAYER met3  ;
    ANTENNAMAXAREACAR 84.6815 LAYER met3  ;
    ANTENNAMAXSIDEAREACAR 427.166 LAYER met3  ;
    ANTENNAMAXCUTCAR 0.137444 LAYER via3  ;
    PORT
      LAYER met3 ;
        RECT 37.980000 1893.540000 45.180000 1894.740000 ;
    END
  END io_in[30]
  PIN io_in[29]
    DIRECTION INPUT ;
    USE SIGNAL ;
    ANTENNAPARTIALMETALAREA 44.9782 LAYER met3  ;
    ANTENNAPARTIALMETALSIDEAREA 240.816 LAYER met3  ;
    ANTENNAPARTIALCUTAREA 0.04 LAYER via3  ;
    ANTENNAPARTIALMETALAREA 0.6516 LAYER met4  ;
    ANTENNAPARTIALMETALSIDEAREA 4.416 LAYER met4  ;
    ANTENNAMODEL OXIDE1 ;
    ANTENNAGATEAREA 0.1965 LAYER met4  ;
    ANTENNAMAXAREACAR 3.31603 LAYER met4  ;
    ANTENNAMAXSIDEAREACAR 22.4733 LAYER met4  ;
    PORT
      LAYER met3 ;
        RECT 37.980000 2154.660000 45.180000 2155.860000 ;
    END
  END io_in[29]
  PIN io_in[28]
    DIRECTION INPUT ;
    USE SIGNAL ;
    ANTENNAPARTIALMETALAREA 28.0234 LAYER met3  ;
    ANTENNAPARTIALMETALSIDEAREA 149.92 LAYER met3  ;
    ANTENNAPARTIALCUTAREA 0.04 LAYER via3  ;
    ANTENNAPARTIALMETALAREA 63.5506 LAYER met4  ;
    ANTENNAPARTIALMETALSIDEAREA 335.752 LAYER met4  ;
    ANTENNAPARTIALCUTAREA 0.64 LAYER via4  ;
    ANTENNAPARTIALMETALAREA 18.352 LAYER met5  ;
    ANTENNAPARTIALMETALSIDEAREA 31.368 LAYER met5  ;
    ANTENNAMODEL OXIDE1 ;
    ANTENNAGATEAREA 0.1965 LAYER met5  ;
    ANTENNAMAXAREACAR 93.3944 LAYER met5  ;
    ANTENNAMAXSIDEAREACAR 159.634 LAYER met5  ;
    PORT
      LAYER met3 ;
        RECT 37.980000 2415.100000 45.180000 2416.300000 ;
    END
  END io_in[28]
  PIN io_in[27]
    DIRECTION INPUT ;
    USE SIGNAL ;
    ANTENNAPARTIALMETALAREA 16.9842 LAYER met3  ;
    ANTENNAPARTIALMETALSIDEAREA 91.048 LAYER met3  ;
    ANTENNAMODEL OXIDE1 ;
    ANTENNAGATEAREA 0.665 LAYER met3  ;
    ANTENNAMAXAREACAR 65.0411 LAYER met3  ;
    ANTENNAMAXSIDEAREACAR 331.737 LAYER met3  ;
    ANTENNAMAXCUTCAR 0.137444 LAYER via3  ;
    PORT
      LAYER met3 ;
        RECT 37.980000 2676.220000 45.180000 2677.420000 ;
    END
  END io_in[27]
  PIN io_in[26]
    DIRECTION INPUT ;
    USE SIGNAL ;
    ANTENNAPARTIALMETALAREA 10.2642 LAYER met3  ;
    ANTENNAPARTIALMETALSIDEAREA 55.656 LAYER met3  ;
    ANTENNAPARTIALCUTAREA 0.04 LAYER via3  ;
    ANTENNAPARTIALMETALAREA 5.9748 LAYER met4  ;
    ANTENNAPARTIALMETALSIDEAREA 32.336 LAYER met4  ;
    ANTENNAMODEL OXIDE1 ;
    ANTENNAGATEAREA 0.665 LAYER met4  ;
    ANTENNAMAXAREACAR 8.98466 LAYER met4  ;
    ANTENNAMAXSIDEAREACAR 48.6256 LAYER met4  ;
    PORT
      LAYER met3 ;
        RECT 37.980000 2936.660000 45.180000 2937.860000 ;
    END
  END io_in[26]
  PIN io_in[25]
    DIRECTION INPUT ;
    USE SIGNAL ;
    ANTENNAPARTIALMETALAREA 9.9882 LAYER met3  ;
    ANTENNAPARTIALMETALSIDEAREA 54.184 LAYER met3  ;
    ANTENNAPARTIALCUTAREA 0.04 LAYER via3  ;
    ANTENNAPARTIALMETALAREA 3.9618 LAYER met4  ;
    ANTENNAPARTIALMETALSIDEAREA 21.6 LAYER met4  ;
    ANTENNAMODEL OXIDE1 ;
    ANTENNAGATEAREA 0.665 LAYER met4  ;
    ANTENNAMAXAREACAR 5.95759 LAYER met4  ;
    ANTENNAMAXSIDEAREACAR 32.4812 LAYER met4  ;
    PORT
      LAYER met3 ;
        RECT 37.980000 3197.100000 45.180000 3198.300000 ;
    END
  END io_in[25]
  PIN io_in[24]
    DIRECTION INPUT ;
    USE SIGNAL ;
    ANTENNAPARTIALMETALAREA 9.7332 LAYER met3  ;
    ANTENNAPARTIALMETALSIDEAREA 52.376 LAYER met3  ;
    ANTENNAMODEL OXIDE1 ;
    ANTENNAGATEAREA 0.665 LAYER met3  ;
    ANTENNAMAXAREACAR 33.6941 LAYER met3  ;
    ANTENNAMAXSIDEAREACAR 170.253 LAYER met3  ;
    ANTENNAMAXCUTCAR 0.137444 LAYER via3  ;
    PORT
      LAYER met3 ;
        RECT 37.980000 3458.220000 45.180000 3459.420000 ;
    END
  END io_in[24]
  PIN io_in[23]
    DIRECTION INPUT ;
    USE SIGNAL ;
    ANTENNAPARTIALMETALAREA 12.0594 LAYER met3  ;
    ANTENNAPARTIALMETALSIDEAREA 64.312 LAYER met3  ;
    PORT
      LAYER met3 ;
        RECT 245.130000 3555.000000 252.330000 3556.200000 ;
    END
  END io_in[23]
  PIN io_in[22]
    DIRECTION INPUT ;
    USE SIGNAL ;
    ANTENNAPARTIALMETALAREA 12.4734 LAYER met3  ;
    ANTENNAPARTIALMETALSIDEAREA 66.52 LAYER met3  ;
    PORT
      LAYER met3 ;
        RECT 569.890000 3555.000000 577.090000 3556.200000 ;
    END
  END io_in[22]
  PIN io_in[21]
    DIRECTION INPUT ;
    USE SIGNAL ;
    ANTENNAPARTIALMETALAREA 13.0254 LAYER met3  ;
    ANTENNAPARTIALMETALSIDEAREA 69.464 LAYER met3  ;
    PORT
      LAYER met3 ;
        RECT 894.190000 3555.000000 901.390000 3556.200000 ;
    END
  END io_in[21]
  PIN io_in[20]
    DIRECTION INPUT ;
    USE SIGNAL ;
    ANTENNAPARTIALMETALAREA 13.5774 LAYER met3  ;
    ANTENNAPARTIALMETALSIDEAREA 72.408 LAYER met3  ;
    PORT
      LAYER met3 ;
        RECT 1218.490000 3555.000000 1225.690000 3556.200000 ;
    END
  END io_in[20]
  PIN io_in[19]
    DIRECTION INPUT ;
    USE SIGNAL ;
    ANTENNAPARTIALMETALAREA 13.9914 LAYER met3  ;
    ANTENNAPARTIALMETALSIDEAREA 74.616 LAYER met3  ;
    PORT
      LAYER met3 ;
        RECT 1543.250000 3555.000000 1550.450000 3556.200000 ;
    END
  END io_in[19]
  PIN io_in[18]
    DIRECTION INPUT ;
    USE SIGNAL ;
    ANTENNAPARTIALMETALAREA 14.5434 LAYER met3  ;
    ANTENNAPARTIALMETALSIDEAREA 77.56 LAYER met3  ;
    PORT
      LAYER met3 ;
        RECT 1867.550000 3555.000000 1874.750000 3556.200000 ;
    END
  END io_in[18]
  PIN io_in[17]
    DIRECTION INPUT ;
    USE SIGNAL ;
    ANTENNAPARTIALMETALAREA 15.0954 LAYER met3  ;
    ANTENNAPARTIALMETALSIDEAREA 80.504 LAYER met3  ;
    PORT
      LAYER met3 ;
        RECT 2191.850000 3555.000000 2199.050000 3556.200000 ;
    END
  END io_in[17]
  PIN io_in[16]
    DIRECTION INPUT ;
    USE SIGNAL ;
    ANTENNAPARTIALMETALAREA 15.3714 LAYER met3  ;
    ANTENNAPARTIALMETALSIDEAREA 81.976 LAYER met3  ;
    PORT
      LAYER met3 ;
        RECT 2516.610000 3555.000000 2523.810000 3556.200000 ;
    END
  END io_in[16]
  PIN io_in[15]
    DIRECTION INPUT ;
    USE SIGNAL ;
    ANTENNAPARTIALMETALAREA 16.5654 LAYER met3  ;
    ANTENNAPARTIALMETALSIDEAREA 88.344 LAYER met3  ;
    PORT
      LAYER met3 ;
        RECT 2840.910000 3555.000000 2848.110000 3556.200000 ;
    END
  END io_in[15]
  PIN io_in[14]
    DIRECTION INPUT ;
    USE SIGNAL ;
    ANTENNAPARTIALMETALAREA 17.9718 LAYER met3  ;
    ANTENNAPARTIALMETALSIDEAREA 96.32 LAYER met3  ;
    PORT
      LAYER met3 ;
        RECT 2960.380000 3390.220000 2967.580000 3391.420000 ;
    END
  END io_in[14]
  PIN io_in[13]
    DIRECTION INPUT ;
    USE SIGNAL ;
    ANTENNAPARTIALMETALAREA 18.1548 LAYER met3  ;
    ANTENNAPARTIALMETALSIDEAREA 97.296 LAYER met3  ;
    PORT
      LAYER met3 ;
        RECT 2960.380000 3124.340000 2967.580000 3125.540000 ;
    END
  END io_in[13]
  PIN io_in[12]
    DIRECTION INPUT ;
    USE SIGNAL ;
    ANTENNAPARTIALMETALAREA 19.068 LAYER met3  ;
    ANTENNAPARTIALMETALSIDEAREA 101.696 LAYER met3  ;
    PORT
      LAYER met3 ;
        RECT 2960.380000 2858.460000 2967.580000 2859.660000 ;
    END
  END io_in[12]
  PIN io_in[11]
    DIRECTION INPUT ;
    USE SIGNAL ;
    ANTENNAPARTIALMETALAREA 18.0888 LAYER met3  ;
    ANTENNAPARTIALMETALSIDEAREA 96.944 LAYER met3  ;
    PORT
      LAYER met3 ;
        RECT 2960.380000 2593.260000 2967.580000 2594.460000 ;
    END
  END io_in[11]
  PIN io_in[10]
    DIRECTION INPUT ;
    USE SIGNAL ;
    ANTENNAPARTIALMETALAREA 18.4548 LAYER met3  ;
    ANTENNAPARTIALMETALSIDEAREA 98.896 LAYER met3  ;
    PORT
      LAYER met3 ;
        RECT 2960.380000 2327.380000 2967.580000 2328.580000 ;
    END
  END io_in[10]
  PIN io_in[9]
    DIRECTION INPUT ;
    USE SIGNAL ;
    ANTENNAPARTIALMETALAREA 18.0888 LAYER met3  ;
    ANTENNAPARTIALMETALSIDEAREA 96.944 LAYER met3  ;
    PORT
      LAYER met3 ;
        RECT 2960.380000 2061.500000 2967.580000 2062.700000 ;
    END
  END io_in[9]
  PIN io_in[8]
    DIRECTION INPUT ;
    USE SIGNAL ;
    ANTENNAPARTIALMETALAREA 55.9054 LAYER met3  ;
    ANTENNAPARTIALMETALSIDEAREA 298.624 LAYER met3  ;
    ANTENNAPARTIALCUTAREA 0.04 LAYER via3  ;
    ANTENNAPARTIALMETALAREA 13.7668 LAYER met4  ;
    ANTENNAPARTIALMETALSIDEAREA 69.768 LAYER met4  ;
    ANTENNAPARTIALCUTAREA 0.64 LAYER via4  ;
    ANTENNADIFFAREA 0.4347 LAYER met5  ;
    ANTENNAPARTIALMETALAREA 835.664 LAYER met5  ;
    ANTENNAPARTIALMETALSIDEAREA 1261.18 LAYER met5  ;
    ANTENNAMODEL OXIDE1 ;
    ANTENNAGATEAREA 1.0997 LAYER met5  ;
    ANTENNAMAXAREACAR 759.902 LAYER met5  ;
    ANTENNAMAXSIDEAREACAR 1146.84 LAYER met5  ;
    PORT
      LAYER met3 ;
        RECT 2960.380000 1796.300000 2967.580000 1797.500000 ;
    END
  END io_in[8]
  PIN io_in[7]
    DIRECTION INPUT ;
    USE SIGNAL ;
    ANTENNAPARTIALMETALAREA 15.1906 LAYER met3  ;
    ANTENNAPARTIALMETALSIDEAREA 81.008 LAYER met3  ;
    ANTENNAPARTIALCUTAREA 0.04 LAYER via3  ;
    ANTENNAPARTIALMETALAREA 54.4698 LAYER met4  ;
    ANTENNAPARTIALMETALSIDEAREA 290.976 LAYER met4  ;
    PORT
      LAYER met3 ;
        RECT 2960.380000 1530.420000 2967.580000 1531.620000 ;
    END
  END io_in[7]
  PIN io_in[6]
    DIRECTION INPUT ;
    USE SIGNAL ;
    ANTENNAPARTIALMETALAREA 16.0186 LAYER met3  ;
    ANTENNAPARTIALMETALSIDEAREA 85.424 LAYER met3  ;
    ANTENNAPARTIALCUTAREA 0.04 LAYER via3  ;
    ANTENNAPARTIALMETALAREA 135.882 LAYER met4  ;
    ANTENNAPARTIALMETALSIDEAREA 721.992 LAYER met4  ;
    ANTENNAPARTIALCUTAREA 0.64 LAYER via4  ;
    ANTENNADIFFAREA 0.4347 LAYER met5  ;
    ANTENNAPARTIALMETALAREA 450.032 LAYER met5  ;
    ANTENNAPARTIALMETALSIDEAREA 682.728 LAYER met5  ;
    ANTENNAMODEL OXIDE1 ;
    ANTENNAGATEAREA 1.0997 LAYER met5  ;
    ANTENNAMAXAREACAR 409.232 LAYER met5  ;
    ANTENNAMAXSIDEAREACAR 620.831 LAYER met5  ;
    PORT
      LAYER met3 ;
        RECT 2960.380000 1264.540000 2967.580000 1265.740000 ;
    END
  END io_in[6]
  PIN io_in[5]
    DIRECTION INPUT ;
    USE SIGNAL ;
    ANTENNAPARTIALMETALAREA 16.0186 LAYER met3  ;
    ANTENNAPARTIALMETALSIDEAREA 85.424 LAYER met3  ;
    ANTENNAPARTIALCUTAREA 0.04 LAYER via3  ;
    ANTENNADIFFAREA 0.4347 LAYER met4  ;
    ANTENNAPARTIALMETALAREA 77.6472 LAYER met4  ;
    ANTENNAPARTIALMETALSIDEAREA 416 LAYER met4  ;
    ANTENNAMODEL OXIDE1 ;
    ANTENNAGATEAREA 1.0997 LAYER met4  ;
    ANTENNAMAXAREACAR 215.813 LAYER met4  ;
    ANTENNAMAXSIDEAREACAR 1134.77 LAYER met4  ;
    ANTENNAMAXCUTCAR 0.394295 LAYER via4  ;
    PORT
      LAYER met3 ;
        RECT 2960.380000 1065.300000 2967.580000 1066.500000 ;
    END
  END io_in[5]
  PIN io_in[4]
    DIRECTION INPUT ;
    USE SIGNAL ;
    ANTENNAPARTIALMETALAREA 16.8466 LAYER met3  ;
    ANTENNAPARTIALMETALSIDEAREA 89.84 LAYER met3  ;
    ANTENNAPARTIALCUTAREA 0.04 LAYER via3  ;
    ANTENNADIFFAREA 0.4347 LAYER met4  ;
    ANTENNAPARTIALMETALAREA 50.3796 LAYER met4  ;
    ANTENNAPARTIALMETALSIDEAREA 269.632 LAYER met4  ;
    ANTENNAMODEL OXIDE1 ;
    ANTENNAGATEAREA 1.0997 LAYER met4  ;
    ANTENNAMAXAREACAR 60.6592 LAYER met4  ;
    ANTENNAMAXSIDEAREACAR 306.921 LAYER met4  ;
    ANTENNAMAXCUTCAR 0.394295 LAYER via4  ;
    PORT
      LAYER met3 ;
        RECT 2960.380000 866.060000 2967.580000 867.260000 ;
    END
  END io_in[4]
  PIN io_in[3]
    DIRECTION INPUT ;
    USE SIGNAL ;
    ANTENNAPARTIALMETALAREA 18.3454 LAYER met3  ;
    ANTENNAPARTIALMETALSIDEAREA 98.304 LAYER met3  ;
    ANTENNAPARTIALCUTAREA 0.04 LAYER via3  ;
    ANTENNAPARTIALMETALAREA 246.257 LAYER met4  ;
    ANTENNAPARTIALMETALSIDEAREA 1310.18 LAYER met4  ;
    ANTENNAPARTIALCUTAREA 0.64 LAYER via4  ;
    ANTENNADIFFAREA 0.4347 LAYER met5  ;
    ANTENNAPARTIALMETALAREA 130.624 LAYER met5  ;
    ANTENNAPARTIALMETALSIDEAREA 199.776 LAYER met5  ;
    ANTENNAMODEL OXIDE1 ;
    ANTENNAGATEAREA 0.5607 LAYER met5  ;
    ANTENNAMAXAREACAR 232.966 LAYER met5  ;
    ANTENNAMAXSIDEAREACAR 356.297 LAYER met5  ;
    PORT
      LAYER met3 ;
        RECT 2960.380000 666.820000 2967.580000 668.020000 ;
    END
  END io_in[3]
  PIN io_in[2]
    DIRECTION INPUT ;
    USE SIGNAL ;
    ANTENNAPARTIALMETALAREA 43.4452 LAYER met3  ;
    ANTENNAPARTIALMETALSIDEAREA 232.64 LAYER met3  ;
    ANTENNAPARTIALCUTAREA 0.04 LAYER via3  ;
    ANTENNAPARTIALMETALAREA 14.9998 LAYER met4  ;
    ANTENNAPARTIALMETALSIDEAREA 76.344 LAYER met4  ;
    ANTENNAPARTIALCUTAREA 0.64 LAYER via4  ;
    ANTENNADIFFAREA 0.4347 LAYER met5  ;
    ANTENNAPARTIALMETALAREA 252.4 LAYER met5  ;
    ANTENNAPARTIALMETALSIDEAREA 382.44 LAYER met5  ;
    ANTENNAMODEL OXIDE1 ;
    ANTENNAGATEAREA 1.0997 LAYER met5  ;
    ANTENNAMAXAREACAR 229.517 LAYER met5  ;
    ANTENNAMAXSIDEAREACAR 347.768 LAYER met5  ;
    PORT
      LAYER met3 ;
        RECT 2960.380000 467.580000 2967.580000 468.780000 ;
    END
  END io_in[2]
  PIN io_in[1]
    DIRECTION INPUT ;
    USE SIGNAL ;
    ANTENNAPARTIALMETALAREA 18.3912 LAYER met3  ;
    ANTENNAPARTIALMETALSIDEAREA 98.552 LAYER met3  ;
    ANTENNAMODEL OXIDE1 ;
    ANTENNAGATEAREA 1.33 LAYER met3  ;
    ANTENNAMAXAREACAR 62.6749 LAYER met3  ;
    ANTENNAMAXSIDEAREACAR 317.517 LAYER met3  ;
    ANTENNAMAXCUTCAR 0.0687218 LAYER via3  ;
    PORT
      LAYER met3 ;
        RECT 2960.380000 268.340000 2967.580000 269.540000 ;
    END
  END io_in[1]
  PIN io_in[0]
    DIRECTION INPUT ;
    USE SIGNAL ;
    ANTENNAPARTIALMETALAREA 3.7344 LAYER met3  ;
    ANTENNAPARTIALMETALSIDEAREA 19.912 LAYER met3  ;
    ANTENNAMODEL OXIDE1 ;
    ANTENNAGATEAREA 0.576 LAYER met3  ;
    ANTENNAMAXAREACAR 7.53316 LAYER met3  ;
    ANTENNAMAXSIDEAREACAR 37.6233 LAYER met3  ;
    ANTENNAMAXCUTCAR 0.158681 LAYER via3  ;
    PORT
      LAYER met3 ;
        RECT 2960.380000 69.780000 2967.580000 70.980000 ;
    END
  END io_in[0]
  PIN io_out[37]
    DIRECTION OUTPUT ;
    USE SIGNAL ;
    ANTENNAPARTIALMETALAREA 0.2364 LAYER met3  ;
    ANTENNAPARTIALMETALSIDEAREA 1.256 LAYER met3  ;
    PORT
      LAYER met3 ;
        RECT 37.980000 133.700000 45.180000 134.900000 ;
    END
  END io_out[37]
  PIN io_out[36]
    DIRECTION OUTPUT ;
    USE SIGNAL ;
    ANTENNAPARTIALMETALAREA 0.2364 LAYER met3  ;
    ANTENNAPARTIALMETALSIDEAREA 1.256 LAYER met3  ;
    PORT
      LAYER met3 ;
        RECT 37.980000 329.540000 45.180000 330.740000 ;
    END
  END io_out[36]
  PIN io_out[35]
    DIRECTION OUTPUT ;
    USE SIGNAL ;
    PORT
      LAYER met3 ;
        RECT 37.980000 524.700000 45.180000 525.900000 ;
    END
  END io_out[35]
  PIN io_out[34]
    DIRECTION OUTPUT ;
    USE SIGNAL ;
    PORT
      LAYER met3 ;
        RECT 37.980000 785.820000 45.180000 787.020000 ;
    END
  END io_out[34]
  PIN io_out[33]
    DIRECTION OUTPUT ;
    USE SIGNAL ;
    ANTENNADIFFAREA 0.714 LAYER met3  ;
    ANTENNAPARTIALMETALAREA 76.23 LAYER met3  ;
    ANTENNAPARTIALMETALSIDEAREA 407.976 LAYER met3  ;
    PORT
      LAYER met3 ;
        RECT 37.980000 1046.260000 45.180000 1047.460000 ;
    END
  END io_out[33]
  PIN io_out[32]
    DIRECTION OUTPUT ;
    USE SIGNAL ;
    ANTENNAPARTIALMETALAREA 87.4612 LAYER met3  ;
    ANTENNAPARTIALMETALSIDEAREA 467.872 LAYER met3  ;
    ANTENNAPARTIALCUTAREA 0.04 LAYER via3  ;
    ANTENNADIFFAREA 0.714 LAYER met4  ;
    ANTENNAPARTIALMETALAREA 2.1318 LAYER met4  ;
    ANTENNAPARTIALMETALSIDEAREA 11.84 LAYER met4  ;
    PORT
      LAYER met3 ;
        RECT 37.980000 1307.380000 45.180000 1308.580000 ;
    END
  END io_out[32]
  PIN io_out[31]
    DIRECTION OUTPUT ;
    USE SIGNAL ;
    ANTENNADIFFAREA 0.714 LAYER met3  ;
    ANTENNAPARTIALMETALAREA 21.7002 LAYER met3  ;
    ANTENNAPARTIALMETALSIDEAREA 116.68 LAYER met3  ;
    PORT
      LAYER met3 ;
        RECT 37.980000 1567.820000 45.180000 1569.020000 ;
    END
  END io_out[31]
  PIN io_out[30]
    DIRECTION OUTPUT ;
    USE SIGNAL ;
    ANTENNADIFFAREA 0.714 LAYER met3  ;
    ANTENNAPARTIALMETALAREA 14.3862 LAYER met3  ;
    ANTENNAPARTIALMETALSIDEAREA 77.672 LAYER met3  ;
    PORT
      LAYER met3 ;
        RECT 37.980000 1828.940000 45.180000 1830.140000 ;
    END
  END io_out[30]
  PIN io_out[29]
    DIRECTION OUTPUT ;
    USE SIGNAL ;
    ANTENNAPARTIALMETALAREA 9.5298 LAYER met3  ;
    ANTENNAPARTIALMETALSIDEAREA 51.776 LAYER met3  ;
    PORT
      LAYER met3 ;
        RECT 37.980000 2089.380000 45.180000 2090.580000 ;
    END
  END io_out[29]
  PIN io_out[28]
    DIRECTION OUTPUT ;
    USE SIGNAL ;
    ANTENNAPARTIALMETALAREA 9.6678 LAYER met3  ;
    ANTENNAPARTIALMETALSIDEAREA 52.512 LAYER met3  ;
    PORT
      LAYER met3 ;
        RECT 37.980000 2349.820000 45.180000 2351.020000 ;
    END
  END io_out[28]
  PIN io_out[27]
    DIRECTION OUTPUT ;
    USE SIGNAL ;
    ANTENNAPARTIALMETALAREA 9.8058 LAYER met3  ;
    ANTENNAPARTIALMETALSIDEAREA 53.248 LAYER met3  ;
    PORT
      LAYER met3 ;
        RECT 37.980000 2610.940000 45.180000 2612.140000 ;
    END
  END io_out[27]
  PIN io_out[26]
    DIRECTION OUTPUT ;
    USE SIGNAL ;
    ANTENNADIFFAREA 0.714 LAYER met3  ;
    ANTENNAPARTIALMETALAREA 10.5222 LAYER met3  ;
    ANTENNAPARTIALMETALSIDEAREA 57.064 LAYER met3  ;
    PORT
      LAYER met3 ;
        RECT 37.980000 2871.380000 45.180000 2872.580000 ;
    END
  END io_out[26]
  PIN io_out[25]
    DIRECTION OUTPUT ;
    USE SIGNAL ;
    ANTENNADIFFAREA 0.43675 LAYER met3  ;
    ANTENNAPARTIALMETALAREA 17.6982 LAYER met3  ;
    ANTENNAPARTIALMETALSIDEAREA 95.336 LAYER met3  ;
    PORT
      LAYER met3 ;
        RECT 37.980000 3132.500000 45.180000 3133.700000 ;
    END
  END io_out[25]
  PIN io_out[24]
    DIRECTION OUTPUT ;
    USE SIGNAL ;
    ANTENNADIFFAREA 0.43675 LAYER met3  ;
    ANTENNAPARTIALMETALAREA 18.6834 LAYER met3  ;
    ANTENNAPARTIALMETALSIDEAREA 100.12 LAYER met3  ;
    PORT
      LAYER met3 ;
        RECT 37.980000 3392.940000 45.180000 3394.140000 ;
    END
  END io_out[24]
  PIN io_out[23]
    DIRECTION OUTPUT ;
    USE SIGNAL ;
    ANTENNADIFFAREA 0.714 LAYER met3  ;
    ANTENNAPARTIALMETALAREA 4.0614 LAYER met3  ;
    ANTENNAPARTIALMETALSIDEAREA 22.136 LAYER met3  ;
    PORT
      LAYER met3 ;
        RECT 164.170000 3555.000000 171.370000 3556.200000 ;
    END
  END io_out[23]
  PIN io_out[22]
    DIRECTION OUTPUT ;
    USE SIGNAL ;
    ANTENNADIFFAREA 0.714 LAYER met3  ;
    ANTENNAPARTIALMETALAREA 4.3374 LAYER met3  ;
    ANTENNAPARTIALMETALSIDEAREA 23.608 LAYER met3  ;
    PORT
      LAYER met3 ;
        RECT 488.470000 3555.000000 495.670000 3556.200000 ;
    END
  END io_out[22]
  PIN io_out[21]
    DIRECTION OUTPUT ;
    USE SIGNAL ;
    ANTENNADIFFAREA 0.714 LAYER met3  ;
    ANTENNAPARTIALMETALAREA 5.0274 LAYER met3  ;
    ANTENNAPARTIALMETALSIDEAREA 27.288 LAYER met3  ;
    PORT
      LAYER met3 ;
        RECT 813.230000 3555.000000 820.430000 3556.200000 ;
    END
  END io_out[21]
  PIN io_out[20]
    DIRECTION OUTPUT ;
    USE SIGNAL ;
    ANTENNAPARTIALMETALAREA 18.6064 LAYER met3  ;
    ANTENNAPARTIALMETALSIDEAREA 100.176 LAYER met3  ;
    ANTENNAPARTIALCUTAREA 0.04 LAYER via3  ;
    ANTENNADIFFAREA 0.714 LAYER met4  ;
    ANTENNAPARTIALMETALAREA 68.6808 LAYER met4  ;
    ANTENNAPARTIALMETALSIDEAREA 366.768 LAYER met4  ;
    PORT
      LAYER met3 ;
        RECT 1137.530000 3555.000000 1144.730000 3556.200000 ;
    END
  END io_out[20]
  PIN io_out[19]
    DIRECTION OUTPUT ;
    USE SIGNAL ;
    ANTENNAPARTIALMETALAREA 11.8444 LAYER met3  ;
    ANTENNAPARTIALMETALSIDEAREA 64.112 LAYER met3  ;
    ANTENNAPARTIALCUTAREA 0.04 LAYER via3  ;
    ANTENNADIFFAREA 0.714 LAYER met4  ;
    ANTENNAPARTIALMETALAREA 225.496 LAYER met4  ;
    ANTENNAPARTIALMETALSIDEAREA 1203.58 LAYER met4  ;
    PORT
      LAYER met3 ;
        RECT 1461.830000 3555.000000 1469.030000 3556.200000 ;
    END
  END io_out[19]
  PIN io_out[18]
    DIRECTION OUTPUT ;
    USE SIGNAL ;
    ANTENNAPARTIALMETALAREA 7.3594 LAYER met3  ;
    ANTENNAPARTIALMETALSIDEAREA 40.192 LAYER met3  ;
    ANTENNAPARTIALCUTAREA 0.04 LAYER via3  ;
    ANTENNADIFFAREA 0.714 LAYER met4  ;
    ANTENNAPARTIALMETALAREA 201.162 LAYER met4  ;
    ANTENNAPARTIALMETALSIDEAREA 1075.22 LAYER met4  ;
    PORT
      LAYER met3 ;
        RECT 1786.590000 3555.000000 1793.790000 3556.200000 ;
    END
  END io_out[18]
  PIN io_out[17]
    DIRECTION OUTPUT ;
    USE SIGNAL ;
    ANTENNADIFFAREA 0.714 LAYER met3  ;
    ANTENNAPARTIALMETALAREA 6.9594 LAYER met3  ;
    ANTENNAPARTIALMETALSIDEAREA 37.592 LAYER met3  ;
    PORT
      LAYER met3 ;
        RECT 2110.890000 3555.000000 2118.090000 3556.200000 ;
    END
  END io_out[17]
  PIN io_out[16]
    DIRECTION OUTPUT ;
    USE SIGNAL ;
    ANTENNAPARTIALMETALAREA 25.9894 LAYER met3  ;
    ANTENNAPARTIALMETALSIDEAREA 139.552 LAYER met3  ;
    ANTENNAPARTIALCUTAREA 0.04 LAYER via3  ;
    ANTENNADIFFAREA 0.891 LAYER met4  ;
    ANTENNAPARTIALMETALAREA 148.834 LAYER met4  ;
    ANTENNAPARTIALMETALSIDEAREA 795.664 LAYER met4  ;
    PORT
      LAYER met3 ;
        RECT 2435.190000 3555.000000 2442.390000 3556.200000 ;
    END
  END io_out[16]
  PIN io_out[15]
    DIRECTION OUTPUT ;
    USE SIGNAL ;
    ANTENNADIFFAREA 0.714 LAYER met3  ;
    ANTENNAPARTIALMETALAREA 7.9254 LAYER met3  ;
    ANTENNAPARTIALMETALSIDEAREA 42.744 LAYER met3  ;
    PORT
      LAYER met3 ;
        RECT 2759.950000 3555.000000 2767.150000 3556.200000 ;
    END
  END io_out[15]
  PIN io_out[14]
    DIRECTION OUTPUT ;
    USE SIGNAL ;
    ANTENNADIFFAREA 0.891 LAYER met3  ;
    ANTENNAPARTIALMETALAREA 40.4292 LAYER met3  ;
    ANTENNAPARTIALMETALSIDEAREA 216.568 LAYER met3  ;
    PORT
      LAYER met3 ;
        RECT 2960.380000 3456.180000 2967.580000 3457.380000 ;
    END
  END io_out[14]
  PIN io_out[13]
    DIRECTION OUTPUT ;
    USE SIGNAL ;
    ANTENNADIFFAREA 0.714 LAYER met3  ;
    ANTENNAPARTIALMETALAREA 27.3192 LAYER met3  ;
    ANTENNAPARTIALMETALSIDEAREA 146.648 LAYER met3  ;
    PORT
      LAYER met3 ;
        RECT 2960.380000 3190.980000 2967.580000 3192.180000 ;
    END
  END io_out[13]
  PIN io_out[12]
    DIRECTION OUTPUT ;
    USE SIGNAL ;
    ANTENNADIFFAREA 0.714 LAYER met3  ;
    ANTENNAPARTIALMETALAREA 31.1172 LAYER met3  ;
    ANTENNAPARTIALMETALSIDEAREA 166.904 LAYER met3  ;
    PORT
      LAYER met3 ;
        RECT 2960.380000 2925.100000 2967.580000 2926.300000 ;
    END
  END io_out[12]
  PIN io_out[11]
    DIRECTION OUTPUT ;
    USE SIGNAL ;
    ANTENNADIFFAREA 0.714 LAYER met3  ;
    ANTENNAPARTIALMETALAREA 18.8202 LAYER met3  ;
    ANTENNAPARTIALMETALSIDEAREA 101.32 LAYER met3  ;
    PORT
      LAYER met3 ;
        RECT 2960.380000 2659.220000 2967.580000 2660.420000 ;
    END
  END io_out[11]
  PIN io_out[10]
    DIRECTION OUTPUT ;
    USE SIGNAL ;
    ANTENNADIFFAREA 0.714 LAYER met3  ;
    ANTENNAPARTIALMETALAREA 19.2042 LAYER met3  ;
    ANTENNAPARTIALMETALSIDEAREA 103.368 LAYER met3  ;
    PORT
      LAYER met3 ;
        RECT 2960.380000 2394.020000 2967.580000 2395.220000 ;
    END
  END io_out[10]
  PIN io_out[9]
    DIRECTION OUTPUT ;
    USE SIGNAL ;
    ANTENNAPARTIALMETALAREA 93.361 LAYER met3  ;
    ANTENNAPARTIALMETALSIDEAREA 499.808 LAYER met3  ;
    ANTENNAPARTIALCUTAREA 0.04 LAYER via3  ;
    ANTENNAPARTIALMETALAREA 14.3398 LAYER met4  ;
    ANTENNAPARTIALMETALSIDEAREA 72.824 LAYER met4  ;
    ANTENNAPARTIALCUTAREA 0.64 LAYER via4  ;
    ANTENNADIFFAREA 0.4455 LAYER met5  ;
    ANTENNAPARTIALMETALAREA 46.72 LAYER met5  ;
    ANTENNAPARTIALMETALSIDEAREA 73.92 LAYER met5  ;
    PORT
      LAYER met3 ;
        RECT 2960.380000 2128.140000 2967.580000 2129.340000 ;
    END
  END io_out[9]
  PIN io_out[8]
    DIRECTION OUTPUT ;
    USE SIGNAL ;
    ANTENNAPARTIALMETALAREA 15.8116 LAYER met3  ;
    ANTENNAPARTIALMETALSIDEAREA 84.32 LAYER met3  ;
    ANTENNAPARTIALCUTAREA 0.04 LAYER via3  ;
    ANTENNAPARTIALMETALAREA 46.8078 LAYER met4  ;
    ANTENNAPARTIALMETALSIDEAREA 250.112 LAYER met4  ;
    PORT
      LAYER met3 ;
        RECT 2960.380000 1862.260000 2967.580000 1863.460000 ;
    END
  END io_out[8]
  PIN io_out[7]
    DIRECTION OUTPUT ;
    USE SIGNAL ;
    ANTENNAPARTIALMETALAREA 16.0186 LAYER met3  ;
    ANTENNAPARTIALMETALSIDEAREA 85.424 LAYER met3  ;
    ANTENNAPARTIALCUTAREA 0.04 LAYER via3  ;
    ANTENNAPARTIALMETALAREA 57.3978 LAYER met4  ;
    ANTENNAPARTIALMETALSIDEAREA 306.592 LAYER met4  ;
    PORT
      LAYER met3 ;
        RECT 2960.380000 1597.060000 2967.580000 1598.260000 ;
    END
  END io_out[7]
  PIN io_out[6]
    DIRECTION OUTPUT ;
    USE SIGNAL ;
    ANTENNAPARTIALMETALAREA 16.8466 LAYER met3  ;
    ANTENNAPARTIALMETALSIDEAREA 89.84 LAYER met3  ;
    ANTENNAPARTIALCUTAREA 0.04 LAYER via3  ;
    ANTENNAPARTIALMETALAREA 67.8288 LAYER met4  ;
    ANTENNAPARTIALMETALSIDEAREA 362.224 LAYER met4  ;
    PORT
      LAYER met3 ;
        RECT 2960.380000 1331.180000 2967.580000 1332.380000 ;
    END
  END io_out[6]
  PIN io_out[5]
    DIRECTION OUTPUT ;
    USE SIGNAL ;
    ANTENNAPARTIALMETALAREA 16.4326 LAYER met3  ;
    ANTENNAPARTIALMETALSIDEAREA 87.632 LAYER met3  ;
    ANTENNAPARTIALCUTAREA 0.04 LAYER via3  ;
    ANTENNAPARTIALMETALAREA 59.2758 LAYER met4  ;
    ANTENNAPARTIALMETALSIDEAREA 316.608 LAYER met4  ;
    PORT
      LAYER met3 ;
        RECT 2960.380000 1131.940000 2967.580000 1133.140000 ;
    END
  END io_out[5]
  PIN io_out[4]
    DIRECTION OUTPUT ;
    USE SIGNAL ;
    ANTENNAPARTIALMETALAREA 18.0738 LAYER met3  ;
    ANTENNAPARTIALMETALSIDEAREA 97.344 LAYER met3  ;
    PORT
      LAYER met3 ;
        RECT 2960.380000 932.700000 2967.580000 933.900000 ;
    END
  END io_out[4]
  PIN io_out[3]
    DIRECTION OUTPUT ;
    USE SIGNAL ;
    ANTENNAPARTIALMETALAREA 18.9888 LAYER met3  ;
    ANTENNAPARTIALMETALSIDEAREA 102.224 LAYER met3  ;
    PORT
      LAYER met3 ;
        RECT 2960.380000 733.460000 2967.580000 734.660000 ;
    END
  END io_out[3]
  PIN io_out[2]
    DIRECTION OUTPUT ;
    USE SIGNAL ;
    ANTENNAPARTIALMETALAREA 18.0738 LAYER met3  ;
    ANTENNAPARTIALMETALSIDEAREA 97.344 LAYER met3  ;
    PORT
      LAYER met3 ;
        RECT 2960.380000 534.220000 2967.580000 535.420000 ;
    END
  END io_out[2]
  PIN io_out[1]
    DIRECTION OUTPUT ;
    USE SIGNAL ;
    ANTENNAPARTIALMETALAREA 17.8908 LAYER met3  ;
    ANTENNAPARTIALMETALSIDEAREA 96.368 LAYER met3  ;
    PORT
      LAYER met3 ;
        RECT 2960.380000 334.980000 2967.580000 336.180000 ;
    END
  END io_out[1]
  PIN io_out[0]
    DIRECTION OUTPUT ;
    USE SIGNAL ;
    ANTENNAPARTIALMETALAREA 18.4398 LAYER met3  ;
    ANTENNAPARTIALMETALSIDEAREA 99.296 LAYER met3  ;
    PORT
      LAYER met3 ;
        RECT 2960.380000 135.740000 2967.580000 136.940000 ;
    END
  END io_out[0]
  PIN io_oeb[37]
    DIRECTION OUTPUT ;
    USE SIGNAL ;
    ANTENNAPARTIALMETALAREA 0.2364 LAYER met3  ;
    ANTENNAPARTIALMETALSIDEAREA 1.256 LAYER met3  ;
    PORT
      LAYER met3 ;
        RECT 37.980000 69.100000 45.180000 70.300000 ;
    END
  END io_oeb[37]
  PIN io_oeb[36]
    DIRECTION OUTPUT ;
    USE SIGNAL ;
    ANTENNAPARTIALMETALAREA 0.2364 LAYER met3  ;
    ANTENNAPARTIALMETALSIDEAREA 1.256 LAYER met3  ;
    PORT
      LAYER met3 ;
        RECT 37.980000 264.260000 45.180000 265.460000 ;
    END
  END io_oeb[36]
  PIN io_oeb[35]
    DIRECTION OUTPUT ;
    USE SIGNAL ;
    ANTENNAPARTIALMETALAREA 0.2364 LAYER met3  ;
    ANTENNAPARTIALMETALSIDEAREA 1.256 LAYER met3  ;
    PORT
      LAYER met3 ;
        RECT 37.980000 460.100000 45.180000 461.300000 ;
    END
  END io_oeb[35]
  PIN io_oeb[34]
    DIRECTION OUTPUT ;
    USE SIGNAL ;
    PORT
      LAYER met3 ;
        RECT 37.980000 720.540000 45.180000 721.740000 ;
    END
  END io_oeb[34]
  PIN io_oeb[33]
    DIRECTION OUTPUT ;
    USE SIGNAL ;
    ANTENNADIFFAREA 0.714 LAYER met3  ;
    ANTENNAPARTIALMETALAREA 46.5774 LAYER met3  ;
    ANTENNAPARTIALMETALSIDEAREA 250.784 LAYER met3  ;
    PORT
      LAYER met3 ;
        RECT 37.980000 980.980000 45.180000 982.180000 ;
    END
  END io_oeb[33]
  PIN io_oeb[32]
    DIRECTION OUTPUT ;
    USE SIGNAL ;
    ANTENNADIFFAREA 0.714 LAYER met3  ;
    ANTENNAPARTIALMETALAREA 45.5034 LAYER met3  ;
    ANTENNAPARTIALMETALSIDEAREA 245.056 LAYER met3  ;
    PORT
      LAYER met3 ;
        RECT 37.980000 1242.100000 45.180000 1243.300000 ;
    END
  END io_oeb[32]
  PIN io_oeb[31]
    DIRECTION OUTPUT ;
    USE SIGNAL ;
    ANTENNAPARTIALMETALAREA 10.6912 LAYER met3  ;
    ANTENNAPARTIALMETALSIDEAREA 58.432 LAYER met3  ;
    ANTENNAPARTIALCUTAREA 0.04 LAYER via3  ;
    ANTENNAPARTIALMETALAREA 4.2028 LAYER met4  ;
    ANTENNAPARTIALMETALSIDEAREA 18.76 LAYER met4  ;
    ANTENNAPARTIALCUTAREA 0.64 LAYER via4  ;
    ANTENNADIFFAREA 0.714 LAYER met5  ;
    ANTENNAPARTIALMETALAREA 251.296 LAYER met5  ;
    ANTENNAPARTIALMETALSIDEAREA 380.784 LAYER met5  ;
    PORT
      LAYER met3 ;
        RECT 37.980000 1502.540000 45.180000 1503.740000 ;
    END
  END io_oeb[31]
  PIN io_oeb[30]
    DIRECTION OUTPUT ;
    USE SIGNAL ;
    ANTENNADIFFAREA 0.714 LAYER met3  ;
    ANTENNAPARTIALMETALAREA 25.0572 LAYER met3  ;
    ANTENNAPARTIALMETALSIDEAREA 134.584 LAYER met3  ;
    PORT
      LAYER met3 ;
        RECT 37.980000 1763.660000 45.180000 1764.860000 ;
    END
  END io_oeb[30]
  PIN io_oeb[29]
    DIRECTION OUTPUT ;
    USE SIGNAL ;
    ANTENNADIFFAREA 0.714 LAYER met3  ;
    ANTENNAPARTIALMETALAREA 11.1546 LAYER met3  ;
    ANTENNAPARTIALMETALSIDEAREA 60.912 LAYER met3  ;
    PORT
      LAYER met3 ;
        RECT 37.980000 2024.100000 45.180000 2025.300000 ;
    END
  END io_oeb[29]
  PIN io_oeb[28]
    DIRECTION OUTPUT ;
    USE SIGNAL ;
    ANTENNADIFFAREA 0.714 LAYER met3  ;
    ANTENNAPARTIALMETALAREA 11.1186 LAYER met3  ;
    ANTENNAPARTIALMETALSIDEAREA 61.2 LAYER met3  ;
    PORT
      LAYER met3 ;
        RECT 37.980000 2284.540000 45.180000 2285.740000 ;
    END
  END io_oeb[28]
  PIN io_oeb[27]
    DIRECTION OUTPUT ;
    USE SIGNAL ;
    ANTENNADIFFAREA 0.714 LAYER met3  ;
    ANTENNAPARTIALMETALAREA 19.3512 LAYER met3  ;
    ANTENNAPARTIALMETALSIDEAREA 104.152 LAYER met3  ;
    PORT
      LAYER met3 ;
        RECT 37.980000 2545.660000 45.180000 2546.860000 ;
    END
  END io_oeb[27]
  PIN io_oeb[26]
    DIRECTION OUTPUT ;
    USE SIGNAL ;
    ANTENNADIFFAREA 0.43675 LAYER met3  ;
    ANTENNAPARTIALMETALAREA 11.5782 LAYER met3  ;
    ANTENNAPARTIALMETALSIDEAREA 62.696 LAYER met3  ;
    PORT
      LAYER met3 ;
        RECT 37.980000 2806.100000 45.180000 2807.300000 ;
    END
  END io_oeb[26]
  PIN io_oeb[25]
    DIRECTION OUTPUT ;
    USE SIGNAL ;
    ANTENNAPARTIALMETALAREA 9.936 LAYER met3  ;
    ANTENNAPARTIALMETALSIDEAREA 53.472 LAYER met3  ;
    PORT
      LAYER met3 ;
        RECT 37.980000 3067.220000 45.180000 3068.420000 ;
    END
  END io_oeb[25]
  PIN io_oeb[24]
    DIRECTION OUTPUT ;
    USE SIGNAL ;
    ANTENNAPARTIALMETALAREA 9.6888 LAYER met3  ;
    ANTENNAPARTIALMETALSIDEAREA 52.624 LAYER met3  ;
    PORT
      LAYER met3 ;
        RECT 37.980000 3327.660000 45.180000 3328.860000 ;
    END
  END io_oeb[24]
  PIN io_oeb[23]
    DIRECTION OUTPUT ;
    USE SIGNAL ;
    ANTENNADIFFAREA 0.43675 LAYER met3  ;
    ANTENNAPARTIALMETALAREA 2.6814 LAYER met3  ;
    ANTENNAPARTIALMETALSIDEAREA 14.776 LAYER met3  ;
    PORT
      LAYER met3 ;
        RECT 83.210000 3555.000000 90.410000 3556.200000 ;
    END
  END io_oeb[23]
  PIN io_oeb[22]
    DIRECTION OUTPUT ;
    USE SIGNAL ;
    ANTENNADIFFAREA 0.43675 LAYER met3  ;
    ANTENNAPARTIALMETALAREA 2.2884 LAYER met3  ;
    ANTENNAPARTIALMETALSIDEAREA 12.68 LAYER met3  ;
    PORT
      LAYER met3 ;
        RECT 407.510000 3555.000000 414.710000 3556.200000 ;
    END
  END io_oeb[22]
  PIN io_oeb[21]
    DIRECTION OUTPUT ;
    USE SIGNAL ;
    ANTENNADIFFAREA 0.43675 LAYER met3  ;
    ANTENNAPARTIALMETALAREA 1.7154 LAYER met3  ;
    ANTENNAPARTIALMETALSIDEAREA 9.624 LAYER met3  ;
    PORT
      LAYER met3 ;
        RECT 731.810000 3555.000000 739.010000 3556.200000 ;
    END
  END io_oeb[21]
  PIN io_oeb[20]
    DIRECTION OUTPUT ;
    USE SIGNAL ;
    ANTENNADIFFAREA 0.43675 LAYER met3  ;
    ANTENNAPARTIALMETALAREA 1.3224 LAYER met3  ;
    ANTENNAPARTIALMETALSIDEAREA 7.528 LAYER met3  ;
    PORT
      LAYER met3 ;
        RECT 1056.570000 3555.000000 1063.770000 3556.200000 ;
    END
  END io_oeb[20]
  PIN io_oeb[19]
    DIRECTION OUTPUT ;
    USE SIGNAL ;
    ANTENNADIFFAREA 0.43675 LAYER met3  ;
    ANTENNAPARTIALMETALAREA 0.7704 LAYER met3  ;
    ANTENNAPARTIALMETALSIDEAREA 4.584 LAYER met3  ;
    PORT
      LAYER met3 ;
        RECT 1380.870000 3555.000000 1388.070000 3556.200000 ;
    END
  END io_oeb[19]
  PIN io_oeb[18]
    DIRECTION OUTPUT ;
    USE SIGNAL ;
    ANTENNADIFFAREA 0.43675 LAYER met3  ;
    ANTENNAPARTIALMETALAREA 0.3564 LAYER met3  ;
    ANTENNAPARTIALMETALSIDEAREA 2.376 LAYER met3  ;
    PORT
      LAYER met3 ;
        RECT 1705.170000 3555.000000 1712.370000 3556.200000 ;
    END
  END io_oeb[18]
  PIN io_oeb[17]
    DIRECTION OUTPUT ;
    USE SIGNAL ;
    ANTENNADIFFAREA 0.43675 LAYER met3  ;
    ANTENNAPARTIALMETALAREA 0.3564 LAYER met3  ;
    ANTENNAPARTIALMETALSIDEAREA 2.376 LAYER met3  ;
    PORT
      LAYER met3 ;
        RECT 2029.930000 3555.000000 2037.130000 3556.200000 ;
    END
  END io_oeb[17]
  PIN io_oeb[16]
    DIRECTION OUTPUT ;
    USE SIGNAL ;
    ANTENNADIFFAREA 0.43675 LAYER met3  ;
    ANTENNAPARTIALMETALAREA 0.3564 LAYER met3  ;
    ANTENNAPARTIALMETALSIDEAREA 2.376 LAYER met3  ;
    PORT
      LAYER met3 ;
        RECT 2354.230000 3555.000000 2361.430000 3556.200000 ;
    END
  END io_oeb[16]
  PIN io_oeb[15]
    DIRECTION OUTPUT ;
    USE SIGNAL ;
    ANTENNADIFFAREA 0.43675 LAYER met3  ;
    ANTENNAPARTIALMETALAREA 0.3564 LAYER met3  ;
    ANTENNAPARTIALMETALSIDEAREA 2.376 LAYER met3  ;
    PORT
      LAYER met3 ;
        RECT 2678.530000 3555.000000 2685.730000 3556.200000 ;
    END
  END io_oeb[15]
  PIN io_oeb[14]
    DIRECTION OUTPUT ;
    USE SIGNAL ;
    ANTENNADIFFAREA 0.43675 LAYER met3  ;
    ANTENNAPARTIALMETALAREA 27.2292 LAYER met3  ;
    ANTENNAPARTIALMETALSIDEAREA 146.168 LAYER met3  ;
    PORT
      LAYER met3 ;
        RECT 2960.380000 3522.820000 2967.580000 3524.020000 ;
    END
  END io_oeb[14]
  PIN io_oeb[13]
    DIRECTION OUTPUT ;
    USE SIGNAL ;
    ANTENNADIFFAREA 0.43675 LAYER met3  ;
    ANTENNAPARTIALMETALAREA 27.2292 LAYER met3  ;
    ANTENNAPARTIALMETALSIDEAREA 146.168 LAYER met3  ;
    PORT
      LAYER met3 ;
        RECT 2960.380000 3256.940000 2967.580000 3258.140000 ;
    END
  END io_oeb[13]
  PIN io_oeb[12]
    DIRECTION OUTPUT ;
    USE SIGNAL ;
    ANTENNADIFFAREA 0.43675 LAYER met3  ;
    ANTENNAPARTIALMETALAREA 27.3462 LAYER met3  ;
    ANTENNAPARTIALMETALSIDEAREA 146.792 LAYER met3  ;
    PORT
      LAYER met3 ;
        RECT 2960.380000 2991.740000 2967.580000 2992.940000 ;
    END
  END io_oeb[12]
  PIN io_oeb[11]
    DIRECTION OUTPUT ;
    USE SIGNAL ;
    ANTENNADIFFAREA 0.43675 LAYER met3  ;
    ANTENNAPARTIALMETALAREA 19.1082 LAYER met3  ;
    ANTENNAPARTIALMETALSIDEAREA 102.856 LAYER met3  ;
    PORT
      LAYER met3 ;
        RECT 2960.380000 2725.860000 2967.580000 2727.060000 ;
    END
  END io_oeb[11]
  PIN io_oeb[10]
    DIRECTION OUTPUT ;
    USE SIGNAL ;
    ANTENNADIFFAREA 0.43675 LAYER met3  ;
    ANTENNAPARTIALMETALAREA 27.5742 LAYER met3  ;
    ANTENNAPARTIALMETALSIDEAREA 148.008 LAYER met3  ;
    PORT
      LAYER met3 ;
        RECT 2960.380000 2459.980000 2967.580000 2461.180000 ;
    END
  END io_oeb[10]
  PIN io_oeb[9]
    DIRECTION OUTPUT ;
    USE SIGNAL ;
    ANTENNADIFFAREA 0.43675 LAYER met3  ;
    ANTENNAPARTIALMETALAREA 18.3762 LAYER met3  ;
    ANTENNAPARTIALMETALSIDEAREA 98.952 LAYER met3  ;
    PORT
      LAYER met3 ;
        RECT 2960.380000 2194.780000 2967.580000 2195.980000 ;
    END
  END io_oeb[9]
  PIN io_oeb[8]
    DIRECTION OUTPUT ;
    USE SIGNAL ;
    ANTENNAPARTIALMETALAREA 16.8466 LAYER met3  ;
    ANTENNAPARTIALMETALSIDEAREA 89.84 LAYER met3  ;
    ANTENNAPARTIALCUTAREA 0.04 LAYER via3  ;
    ANTENNADIFFAREA 0.43675 LAYER met4  ;
    ANTENNAPARTIALMETALAREA 49.7118 LAYER met4  ;
    ANTENNAPARTIALMETALSIDEAREA 265.6 LAYER met4  ;
    PORT
      LAYER met3 ;
        RECT 2960.380000 1928.900000 2967.580000 1930.100000 ;
    END
  END io_oeb[8]
  PIN io_oeb[7]
    DIRECTION OUTPUT ;
    USE SIGNAL ;
    ANTENNAPARTIALMETALAREA 16.8466 LAYER met3  ;
    ANTENNAPARTIALMETALSIDEAREA 89.84 LAYER met3  ;
    ANTENNAPARTIALCUTAREA 0.04 LAYER via3  ;
    ANTENNADIFFAREA 0.43675 LAYER met4  ;
    ANTENNAPARTIALMETALAREA 60.6918 LAYER met4  ;
    ANTENNAPARTIALMETALSIDEAREA 324.16 LAYER met4  ;
    PORT
      LAYER met3 ;
        RECT 2960.380000 1663.020000 2967.580000 1664.220000 ;
    END
  END io_oeb[7]
  PIN io_oeb[6]
    DIRECTION OUTPUT ;
    USE SIGNAL ;
    ANTENNAPARTIALMETALAREA 0.2776 LAYER met3  ;
    ANTENNAPARTIALMETALSIDEAREA 1.472 LAYER met3  ;
    ANTENNAPARTIALCUTAREA 0.04 LAYER via3  ;
    ANTENNADIFFAREA 0.43675 LAYER met4  ;
    ANTENNAPARTIALMETALAREA 70.9398 LAYER met4  ;
    ANTENNAPARTIALMETALSIDEAREA 378.816 LAYER met4  ;
    PORT
      LAYER met3 ;
        RECT 2960.380000 1397.820000 2967.580000 1399.020000 ;
    END
  END io_oeb[6]
  PIN io_oeb[5]
    DIRECTION OUTPUT ;
    USE SIGNAL ;
    ANTENNAPARTIALMETALAREA 15.1906 LAYER met3  ;
    ANTENNAPARTIALMETALSIDEAREA 81.008 LAYER met3  ;
    ANTENNAPARTIALCUTAREA 0.04 LAYER via3  ;
    ANTENNADIFFAREA 0.43675 LAYER met4  ;
    ANTENNAPARTIALMETALAREA 61.9728 LAYER met4  ;
    ANTENNAPARTIALMETALSIDEAREA 330.992 LAYER met4  ;
    PORT
      LAYER met3 ;
        RECT 2960.380000 1198.580000 2967.580000 1199.780000 ;
    END
  END io_oeb[5]
  PIN io_oeb[4]
    DIRECTION OUTPUT ;
    USE SIGNAL ;
    ANTENNADIFFAREA 0.43675 LAYER met3  ;
    ANTENNAPARTIALMETALAREA 18.7422 LAYER met3  ;
    ANTENNAPARTIALMETALSIDEAREA 100.904 LAYER met3  ;
    PORT
      LAYER met3 ;
        RECT 2960.380000 999.340000 2967.580000 1000.540000 ;
    END
  END io_oeb[4]
  PIN io_oeb[3]
    DIRECTION OUTPUT ;
    USE SIGNAL ;
    ANTENNADIFFAREA 0.43675 LAYER met3  ;
    ANTENNAPARTIALMETALAREA 27.2982 LAYER met3  ;
    ANTENNAPARTIALMETALSIDEAREA 146.536 LAYER met3  ;
    PORT
      LAYER met3 ;
        RECT 2960.380000 800.100000 2967.580000 801.300000 ;
    END
  END io_oeb[3]
  PIN io_oeb[2]
    DIRECTION OUTPUT ;
    USE SIGNAL ;
    ANTENNADIFFAREA 0.43675 LAYER met3  ;
    ANTENNAPARTIALMETALAREA 18.5142 LAYER met3  ;
    ANTENNAPARTIALMETALSIDEAREA 99.688 LAYER met3  ;
    PORT
      LAYER met3 ;
        RECT 2960.380000 600.860000 2967.580000 602.060000 ;
    END
  END io_oeb[2]
  PIN io_oeb[1]
    DIRECTION OUTPUT ;
    USE SIGNAL ;
    ANTENNADIFFAREA 0.43675 LAYER met3  ;
    ANTENNAPARTIALMETALAREA 27.0702 LAYER met3  ;
    ANTENNAPARTIALMETALSIDEAREA 145.32 LAYER met3  ;
    PORT
      LAYER met3 ;
        RECT 2960.380000 401.620000 2967.580000 402.820000 ;
    END
  END io_oeb[1]
  PIN io_oeb[0]
    DIRECTION OUTPUT ;
    USE SIGNAL ;
    ANTENNADIFFAREA 0.43675 LAYER met3  ;
    ANTENNAPARTIALMETALAREA 18.5592 LAYER met3  ;
    ANTENNAPARTIALMETALSIDEAREA 99.928 LAYER met3  ;
    PORT
      LAYER met3 ;
        RECT 2960.380000 202.380000 2967.580000 203.580000 ;
    END
  END io_oeb[0]
  PIN analog_io[28]
    DIRECTION INOUT ;
    USE SIGNAL ;
    PORT
      LAYER met3 ;
        RECT 37.980000 655.260000 45.180000 656.460000 ;
    END
  END analog_io[28]
  PIN analog_io[27]
    DIRECTION INOUT ;
    USE SIGNAL ;
    PORT
      LAYER met3 ;
        RECT 37.980000 916.380000 45.180000 917.580000 ;
    END
  END analog_io[27]
  PIN analog_io[26]
    DIRECTION INOUT ;
    USE SIGNAL ;
    PORT
      LAYER met3 ;
        RECT 37.980000 1176.820000 45.180000 1178.020000 ;
    END
  END analog_io[26]
  PIN analog_io[25]
    DIRECTION INOUT ;
    USE SIGNAL ;
    PORT
      LAYER met3 ;
        RECT 37.980000 1437.260000 45.180000 1438.460000 ;
    END
  END analog_io[25]
  PIN analog_io[24]
    DIRECTION INOUT ;
    USE SIGNAL ;
    PORT
      LAYER met3 ;
        RECT 37.980000 1698.380000 45.180000 1699.580000 ;
    END
  END analog_io[24]
  PIN analog_io[23]
    DIRECTION INOUT ;
    USE SIGNAL ;
    PORT
      LAYER met3 ;
        RECT 37.980000 1958.820000 45.180000 1960.020000 ;
    END
  END analog_io[23]
  PIN analog_io[22]
    DIRECTION INOUT ;
    USE SIGNAL ;
    PORT
      LAYER met3 ;
        RECT 37.980000 2219.940000 45.180000 2221.140000 ;
    END
  END analog_io[22]
  PIN analog_io[21]
    DIRECTION INOUT ;
    USE SIGNAL ;
    PORT
      LAYER met3 ;
        RECT 37.980000 2480.380000 45.180000 2481.580000 ;
    END
  END analog_io[21]
  PIN analog_io[20]
    DIRECTION INOUT ;
    USE SIGNAL ;
    PORT
      LAYER met3 ;
        RECT 37.980000 2740.820000 45.180000 2742.020000 ;
    END
  END analog_io[20]
  PIN analog_io[19]
    DIRECTION INOUT ;
    USE SIGNAL ;
    PORT
      LAYER met3 ;
        RECT 37.980000 3001.940000 45.180000 3003.140000 ;
    END
  END analog_io[19]
  PIN analog_io[18]
    DIRECTION INOUT ;
    USE SIGNAL ;
    PORT
      LAYER met3 ;
        RECT 37.980000 3262.380000 45.180000 3263.580000 ;
    END
  END analog_io[18]
  PIN analog_io[17]
    DIRECTION INOUT ;
    USE SIGNAL ;
    PORT
      LAYER met3 ;
        RECT 37.980000 3523.500000 45.180000 3524.700000 ;
    END
  END analog_io[17]
  PIN analog_io[16]
    DIRECTION INOUT ;
    USE SIGNAL ;
    PORT
      LAYER met3 ;
        RECT 326.550000 3555.000000 333.750000 3556.200000 ;
    END
  END analog_io[16]
  PIN analog_io[15]
    DIRECTION INOUT ;
    USE SIGNAL ;
    PORT
      LAYER met3 ;
        RECT 650.850000 3555.000000 658.050000 3556.200000 ;
    END
  END analog_io[15]
  PIN analog_io[14]
    DIRECTION INOUT ;
    USE SIGNAL ;
    PORT
      LAYER met3 ;
        RECT 975.150000 3555.000000 982.350000 3556.200000 ;
    END
  END analog_io[14]
  PIN analog_io[13]
    DIRECTION INOUT ;
    USE SIGNAL ;
    PORT
      LAYER met3 ;
        RECT 1299.910000 3555.000000 1307.110000 3556.200000 ;
    END
  END analog_io[13]
  PIN analog_io[12]
    DIRECTION INOUT ;
    USE SIGNAL ;
    PORT
      LAYER met3 ;
        RECT 1624.210000 3555.000000 1631.410000 3556.200000 ;
    END
  END analog_io[12]
  PIN analog_io[11]
    DIRECTION INOUT ;
    USE SIGNAL ;
    PORT
      LAYER met3 ;
        RECT 1948.510000 3555.000000 1955.710000 3556.200000 ;
    END
  END analog_io[11]
  PIN analog_io[10]
    DIRECTION INOUT ;
    USE SIGNAL ;
    PORT
      LAYER met3 ;
        RECT 2273.270000 3555.000000 2280.470000 3556.200000 ;
    END
  END analog_io[10]
  PIN analog_io[9]
    DIRECTION INOUT ;
    USE SIGNAL ;
    PORT
      LAYER met3 ;
        RECT 2597.570000 3555.000000 2604.770000 3556.200000 ;
    END
  END analog_io[9]
  PIN analog_io[8]
    DIRECTION INOUT ;
    USE SIGNAL ;
    PORT
      LAYER met3 ;
        RECT 2921.870000 3555.000000 2929.070000 3556.200000 ;
    END
  END analog_io[8]
  PIN analog_io[7]
    DIRECTION INOUT ;
    USE SIGNAL ;
    PORT
      LAYER met3 ;
        RECT 2960.380000 3323.580000 2967.580000 3324.780000 ;
    END
  END analog_io[7]
  PIN analog_io[6]
    DIRECTION INOUT ;
    USE SIGNAL ;
    PORT
      LAYER met3 ;
        RECT 2960.380000 3057.700000 2967.580000 3058.900000 ;
    END
  END analog_io[6]
  PIN analog_io[5]
    DIRECTION INOUT ;
    USE SIGNAL ;
    PORT
      LAYER met3 ;
        RECT 2960.380000 2792.500000 2967.580000 2793.700000 ;
    END
  END analog_io[5]
  PIN analog_io[4]
    DIRECTION INOUT ;
    USE SIGNAL ;
    PORT
      LAYER met3 ;
        RECT 2960.380000 2526.620000 2967.580000 2527.820000 ;
    END
  END analog_io[4]
  PIN analog_io[3]
    DIRECTION INOUT ;
    USE SIGNAL ;
    PORT
      LAYER met3 ;
        RECT 2960.380000 2260.740000 2967.580000 2261.940000 ;
    END
  END analog_io[3]
  PIN analog_io[2]
    DIRECTION INOUT ;
    USE SIGNAL ;
    PORT
      LAYER met3 ;
        RECT 2960.380000 1995.540000 2967.580000 1996.740000 ;
    END
  END analog_io[2]
  PIN analog_io[1]
    DIRECTION INOUT ;
    USE SIGNAL ;
    PORT
      LAYER met3 ;
        RECT 2960.380000 1729.660000 2967.580000 1730.860000 ;
    END
  END analog_io[1]
  PIN analog_io[0]
    DIRECTION INOUT ;
    USE SIGNAL ;
    PORT
      LAYER met3 ;
        RECT 2960.380000 1463.780000 2967.580000 1464.980000 ;
    END
  END analog_io[0]
  PIN user_clock2
    DIRECTION INPUT ;
    USE SIGNAL ;
    PORT
      LAYER met3 ;
        RECT 2941.650000 32.600000 2948.850000 33.800000 ;
    END
  END user_clock2
  PIN user_irq[2]
    DIRECTION OUTPUT ;
    USE SIGNAL ;
    ANTENNAPARTIALMETALAREA 18.8424 LAYER met3  ;
    ANTENNAPARTIALMETALSIDEAREA 100.488 LAYER met3  ;
    PORT
      LAYER met3 ;
        RECT 2959.590000 32.600000 2966.790000 33.800000 ;
    END
  END user_irq[2]
  PIN user_irq[1]
    DIRECTION OUTPUT ;
    USE SIGNAL ;
    ANTENNAPARTIALMETALAREA 5.8374 LAYER met3  ;
    ANTENNAPARTIALMETALSIDEAREA 31.128 LAYER met3  ;
    PORT
      LAYER met3 ;
        RECT 2953.610000 32.600000 2960.810000 33.800000 ;
    END
  END user_irq[1]
  PIN user_irq[0]
    DIRECTION OUTPUT ;
    USE SIGNAL ;
    ANTENNAPARTIALMETALAREA 1.5174 LAYER met3  ;
    ANTENNAPARTIALMETALSIDEAREA 8.088 LAYER met3  ;
    PORT
      LAYER met3 ;
        RECT 2947.630000 32.600000 2954.830000 33.800000 ;
    END
  END user_irq[0]
  PIN VSS
    DIRECTION INOUT ;
    USE GROUND ;

# P/G power stripe data as pin
    PORT
      LAYER met4 ;
        RECT 2974.080000 28.080000 2977.080000 3566.400000 ;
        RECT 28.100000 28.080000 31.100000 3566.400000 ;
        RECT 81.620000 28.080000 84.620000 104.080000 ;
        RECT 2892.540000 28.080000 2895.540000 104.080000 ;
        RECT 81.620000 3473.140000 84.620000 3566.400000 ;
        RECT 2892.540000 3473.140000 2895.540000 3566.400000 ;
      LAYER met5 ;
        RECT 28.100000 28.080000 2977.080000 31.080000 ;
        RECT 28.100000 106.660000 79.080000 109.660000 ;
        RECT 2898.080000 106.660000 2977.080000 109.660000 ;
        RECT 28.100000 3563.400000 2977.080000 3566.400000 ;
        RECT 28.100000 3465.860000 79.080000 3468.860000 ;
        RECT 2898.080000 3465.860000 2977.080000 3468.860000 ;
    END
# end of P/G power stripe data as pin

  END VSS
  PIN VDD
    DIRECTION INOUT ;
    USE POWER ;

# P/G power stripe data as pin
    PORT
      LAYER met4 ;
        RECT 2969.380000 32.780000 2972.380000 3561.700000 ;
        RECT 32.800000 32.780000 35.800000 3561.700000 ;
        RECT 2880.300000 32.780000 2883.300000 104.080000 ;
        RECT 93.860000 32.780000 96.860000 104.080000 ;
        RECT 2880.300000 3473.140000 2883.300000 3561.700000 ;
        RECT 93.860000 3473.140000 96.860000 3561.700000 ;
      LAYER met5 ;
        RECT 2898.080000 118.900000 2972.380000 121.900000 ;
        RECT 32.800000 32.780000 2972.380000 35.780000 ;
        RECT 32.800000 118.900000 79.080000 121.900000 ;
        RECT 2898.080000 3453.620000 2972.380000 3456.620000 ;
        RECT 32.800000 3558.700000 2972.380000 3561.700000 ;
        RECT 32.800000 3453.620000 79.080000 3456.620000 ;
    END
# end of P/G power stripe data as pin

  END VDD
  OBS
    LAYER li1 ;
      RECT 0.000000 0.000000 3005.180000 3594.480000 ;
    LAYER met1 ;
      RECT 0.000000 0.000000 3005.180000 3594.480000 ;
    LAYER met2 ;
      RECT 0.000000 0.000000 3005.180000 3594.480000 ;
    LAYER met3 ;
      RECT 0.000000 0.000000 3005.180000 3594.480000 ;
    LAYER met4 ;
      RECT 0.000000 0.000000 3005.180000 3594.480000 ;
    LAYER met5 ;
      RECT 0.000000 0.000000 3005.180000 3594.480000 ;
  END
END user_project_wrapper

END LIBRARY
